VERSION 5.7 ;
  NOWIREEXTENSIONATPIN ON ;
  DIVIDERCHAR "/" ;
  BUSBITCHARS "[]" ;
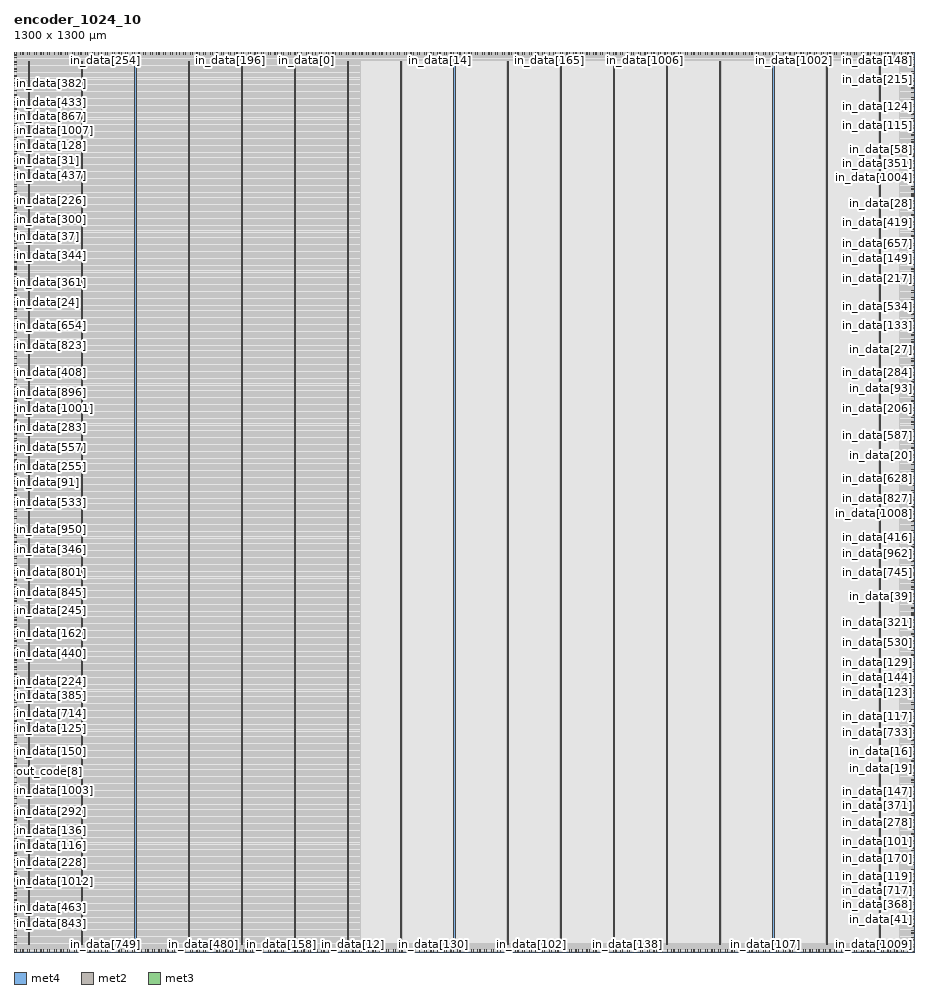
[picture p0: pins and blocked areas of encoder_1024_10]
MACRO encoder_1024_10
  CLASS BLOCK ;
  FOREIGN encoder_1024_10 ;
  ORIGIN 0.000 0.000 ;
  SIZE 1300.000 BY 1300.000 ;
  PIN VGND
    DIRECTION INOUT ;
    USE GROUND ;
    PORT
      LAYER met4 ;
        RECT 97.840 10.640 99.440 1286.800 ;
    END
    PORT
      LAYER met4 ;
        RECT 251.440 10.640 253.040 1286.800 ;
    END
    PORT
      LAYER met4 ;
        RECT 405.040 10.640 406.640 1286.800 ;
    END
    PORT
      LAYER met4 ;
        RECT 558.640 10.640 560.240 1286.800 ;
    END
    PORT
      LAYER met4 ;
        RECT 712.240 10.640 713.840 1286.800 ;
    END
    PORT
      LAYER met4 ;
        RECT 865.840 10.640 867.440 1286.800 ;
    END
    PORT
      LAYER met4 ;
        RECT 1019.440 10.640 1021.040 1286.800 ;
    END
    PORT
      LAYER met4 ;
        RECT 1173.040 10.640 1174.640 1286.800 ;
    END
  END VGND
  PIN VPWR
    DIRECTION INOUT ;
    USE POWER ;
    PORT
      LAYER met4 ;
        RECT 21.040 10.640 22.640 1286.800 ;
    END
    PORT
      LAYER met4 ;
        RECT 174.640 10.640 176.240 1286.800 ;
    END
    PORT
      LAYER met4 ;
        RECT 328.240 10.640 329.840 1286.800 ;
    END
    PORT
      LAYER met4 ;
        RECT 481.840 10.640 483.440 1286.800 ;
    END
    PORT
      LAYER met4 ;
        RECT 635.440 10.640 637.040 1286.800 ;
    END
    PORT
      LAYER met4 ;
        RECT 789.040 10.640 790.640 1286.800 ;
    END
    PORT
      LAYER met4 ;
        RECT 942.640 10.640 944.240 1286.800 ;
    END
    PORT
      LAYER met4 ;
        RECT 1096.240 10.640 1097.840 1286.800 ;
    END
    PORT
      LAYER met4 ;
        RECT 1249.840 10.640 1251.440 1286.800 ;
    END
  END VPWR
  PIN in_data[0]
    DIRECTION INPUT ;
    USE SIGNAL ;
    ANTENNAGATEAREA 0.426000 ;
    PORT
      LAYER met2 ;
        RECT 421.910 1296.000 422.190 1300.000 ;
    END
  END in_data[0]
  PIN in_data[1000]
    DIRECTION INPUT ;
    USE SIGNAL ;
    ANTENNAGATEAREA 0.742500 ;
    PORT
      LAYER met3 ;
        RECT 1296.000 10.240 1300.000 10.840 ;
    END
  END in_data[1000]
  PIN in_data[1001]
    DIRECTION INPUT ;
    USE SIGNAL ;
    ANTENNAGATEAREA 0.495000 ;
    PORT
      LAYER met3 ;
        RECT 0.000 785.440 4.000 786.040 ;
    END
  END in_data[1001]
  PIN in_data[1002]
    DIRECTION INPUT ;
    USE SIGNAL ;
    ANTENNAGATEAREA 0.742500 ;
    PORT
      LAYER met2 ;
        RECT 1127.090 1296.000 1127.370 1300.000 ;
    END
  END in_data[1002]
  PIN in_data[1003]
    DIRECTION INPUT ;
    USE SIGNAL ;
    ANTENNAGATEAREA 0.742500 ;
    PORT
      LAYER met3 ;
        RECT 0.000 244.840 4.000 245.440 ;
    END
  END in_data[1003]
  PIN in_data[1004]
    DIRECTION INPUT ;
    USE SIGNAL ;
    ANTENNAGATEAREA 0.742500 ;
    PORT
      LAYER met3 ;
        RECT 1296.000 1118.640 1300.000 1119.240 ;
    END
  END in_data[1004]
  PIN in_data[1005]
    DIRECTION INPUT ;
    USE SIGNAL ;
    ANTENNAGATEAREA 0.426000 ;
    PORT
      LAYER met3 ;
        RECT 0.000 601.840 4.000 602.440 ;
    END
  END in_data[1005]
  PIN in_data[1006]
    DIRECTION INPUT ;
    USE SIGNAL ;
    ANTENNAGATEAREA 0.495000 ;
    PORT
      LAYER met2 ;
        RECT 911.350 1296.000 911.630 1300.000 ;
    END
  END in_data[1006]
  PIN in_data[1007]
    DIRECTION INPUT ;
    USE SIGNAL ;
    ANTENNAGATEAREA 0.852000 ;
    PORT
      LAYER met3 ;
        RECT 0.000 1186.640 4.000 1187.240 ;
    END
  END in_data[1007]
  PIN in_data[1008]
    DIRECTION INPUT ;
    USE SIGNAL ;
    ANTENNAGATEAREA 0.247500 ;
    PORT
      LAYER met3 ;
        RECT 1296.000 632.440 1300.000 633.040 ;
    END
  END in_data[1008]
  PIN in_data[1009]
    DIRECTION INPUT ;
    USE SIGNAL ;
    ANTENNAGATEAREA 0.742500 ;
    PORT
      LAYER met2 ;
        RECT 1255.890 0.000 1256.170 4.000 ;
    END
  END in_data[1009]
  PIN in_data[100]
    DIRECTION INPUT ;
    USE SIGNAL ;
    ANTENNAGATEAREA 0.852000 ;
    PORT
      LAYER met2 ;
        RECT 0.090 1296.000 0.370 1300.000 ;
    END
  END in_data[100]
  PIN in_data[1010]
    DIRECTION INPUT ;
    USE SIGNAL ;
    ANTENNAGATEAREA 0.495000 ;
    PORT
      LAYER met3 ;
        RECT 1296.000 319.640 1300.000 320.240 ;
    END
  END in_data[1010]
  PIN in_data[1011]
    DIRECTION INPUT ;
    USE SIGNAL ;
    ANTENNAGATEAREA 0.742500 ;
    PORT
      LAYER met3 ;
        RECT 0.000 200.640 4.000 201.240 ;
    END
  END in_data[1011]
  PIN in_data[1012]
    DIRECTION INPUT ;
    USE SIGNAL ;
    ANTENNAGATEAREA 0.742500 ;
    PORT
      LAYER met3 ;
        RECT 0.000 102.040 4.000 102.640 ;
    END
  END in_data[1012]
  PIN in_data[1013]
    DIRECTION INPUT ;
    USE SIGNAL ;
    ANTENNAGATEAREA 0.742500 ;
    PORT
      LAYER met2 ;
        RECT 144.990 0.000 145.270 4.000 ;
    END
  END in_data[1013]
  PIN in_data[1014]
    DIRECTION INPUT ;
    USE SIGNAL ;
    ANTENNAGATEAREA 0.852000 ;
    PORT
      LAYER met2 ;
        RECT 1259.110 1296.000 1259.390 1300.000 ;
    END
  END in_data[1014]
  PIN in_data[1015]
    DIRECTION INPUT ;
    USE SIGNAL ;
    ANTENNAGATEAREA 0.247500 ;
    PORT
      LAYER met2 ;
        RECT 702.050 0.000 702.330 4.000 ;
    END
  END in_data[1015]
  PIN in_data[1016]
    DIRECTION INPUT ;
    USE SIGNAL ;
    ANTENNAGATEAREA 0.426000 ;
    PORT
      LAYER met3 ;
        RECT 1296.000 663.040 1300.000 663.640 ;
    END
  END in_data[1016]
  PIN in_data[1017]
    DIRECTION INPUT ;
    USE SIGNAL ;
    ANTENNAGATEAREA 0.742500 ;
    PORT
      LAYER met3 ;
        RECT 0.000 1037.040 4.000 1037.640 ;
    END
  END in_data[1017]
  PIN in_data[1018]
    DIRECTION INPUT ;
    USE SIGNAL ;
    ANTENNAGATEAREA 0.852000 ;
    PORT
      LAYER met2 ;
        RECT 32.290 1296.000 32.570 1300.000 ;
    END
  END in_data[1018]
  PIN in_data[1019]
    DIRECTION INPUT ;
    USE SIGNAL ;
    ANTENNAGATEAREA 0.495000 ;
    PORT
      LAYER met3 ;
        RECT 1296.000 873.840 1300.000 874.440 ;
    END
  END in_data[1019]
  PIN in_data[101]
    DIRECTION INPUT ;
    USE SIGNAL ;
    ANTENNAGATEAREA 0.742500 ;
    PORT
      LAYER met3 ;
        RECT 1296.000 159.840 1300.000 160.440 ;
    END
  END in_data[101]
  PIN in_data[1020]
    DIRECTION INPUT ;
    USE SIGNAL ;
    ANTENNAGATEAREA 0.742500 ;
    PORT
      LAYER met3 ;
        RECT 1296.000 51.040 1300.000 51.640 ;
    END
  END in_data[1020]
  PIN in_data[1021]
    DIRECTION INPUT ;
    USE SIGNAL ;
    ANTENNAGATEAREA 0.495000 ;
    PORT
      LAYER met3 ;
        RECT 0.000 748.040 4.000 748.640 ;
    END
  END in_data[1021]
  PIN in_data[1022]
    DIRECTION INPUT ;
    USE SIGNAL ;
    ANTENNAGATEAREA 0.742500 ;
    PORT
      LAYER met3 ;
        RECT 0.000 183.640 4.000 184.240 ;
    END
  END in_data[1022]
  PIN in_data[1023]
    DIRECTION INPUT ;
    USE SIGNAL ;
    ANTENNAGATEAREA 0.742500 ;
    PORT
      LAYER met3 ;
        RECT 1296.000 275.440 1300.000 276.040 ;
    END
  END in_data[1023]
  PIN in_data[102]
    DIRECTION INPUT ;
    USE SIGNAL ;
    ANTENNAGATEAREA 0.426000 ;
    PORT
      LAYER met2 ;
        RECT 747.130 0.000 747.410 4.000 ;
    END
  END in_data[102]
  PIN in_data[103]
    DIRECTION INPUT ;
    USE SIGNAL ;
    ANTENNAGATEAREA 0.742500 ;
    PORT
      LAYER met2 ;
        RECT 164.310 1296.000 164.590 1300.000 ;
    END
  END in_data[103]
  PIN in_data[104]
    DIRECTION INPUT ;
    USE SIGNAL ;
    ANTENNAGATEAREA 0.495000 ;
    PORT
      LAYER met2 ;
        RECT 1156.070 1296.000 1156.350 1300.000 ;
    END
  END in_data[104]
  PIN in_data[105]
    DIRECTION INPUT ;
    USE SIGNAL ;
    ANTENNAGATEAREA 0.426000 ;
    PORT
      LAYER met3 ;
        RECT 1296.000 880.640 1300.000 881.240 ;
    END
  END in_data[105]
  PIN in_data[106]
    DIRECTION INPUT ;
    USE SIGNAL ;
    ANTENNAGATEAREA 0.426000 ;
    PORT
      LAYER met3 ;
        RECT 1296.000 935.040 1300.000 935.640 ;
    END
  END in_data[106]
  PIN in_data[107]
    DIRECTION INPUT ;
    USE SIGNAL ;
    ANTENNAGATEAREA 0.742500 ;
    PORT
      LAYER met2 ;
        RECT 1085.230 0.000 1085.510 4.000 ;
    END
  END in_data[107]
  PIN in_data[108]
    DIRECTION INPUT ;
    USE SIGNAL ;
    ANTENNAGATEAREA 0.495000 ;
    PORT
      LAYER met3 ;
        RECT 0.000 625.640 4.000 626.240 ;
    END
  END in_data[108]
  PIN in_data[109]
    DIRECTION INPUT ;
    USE SIGNAL ;
    ANTENNAGATEAREA 0.742500 ;
    PORT
      LAYER met2 ;
        RECT 1143.190 0.000 1143.470 4.000 ;
    END
  END in_data[109]
  PIN in_data[10]
    DIRECTION INPUT ;
    USE SIGNAL ;
    ANTENNAGATEAREA 0.742500 ;
    PORT
      LAYER met2 ;
        RECT 1082.010 1296.000 1082.290 1300.000 ;
    END
  END in_data[10]
  PIN in_data[110]
    DIRECTION INPUT ;
    USE SIGNAL ;
    ANTENNAGATEAREA 0.742500 ;
    PORT
      LAYER met2 ;
        RECT 209.390 1296.000 209.670 1300.000 ;
    END
  END in_data[110]
  PIN in_data[111]
    DIRECTION INPUT ;
    USE SIGNAL ;
    ANTENNAGATEAREA 0.742500 ;
    PORT
      LAYER met2 ;
        RECT 231.930 0.000 232.210 4.000 ;
    END
  END in_data[111]
  PIN in_data[112]
    DIRECTION INPUT ;
    USE SIGNAL ;
    ANTENNAGATEAREA 0.742500 ;
    PORT
      LAYER met2 ;
        RECT 219.050 1296.000 219.330 1300.000 ;
    END
  END in_data[112]
  PIN in_data[113]
    DIRECTION INPUT ;
    USE SIGNAL ;
    ANTENNAGATEAREA 0.426000 ;
    PORT
      LAYER met2 ;
        RECT 895.250 1296.000 895.530 1300.000 ;
    END
  END in_data[113]
  PIN in_data[114]
    DIRECTION INPUT ;
    USE SIGNAL ;
    ANTENNAGATEAREA 0.742500 ;
    PORT
      LAYER met2 ;
        RECT 1291.310 0.000 1291.590 4.000 ;
    END
  END in_data[114]
  PIN in_data[115]
    DIRECTION INPUT ;
    USE SIGNAL ;
    ANTENNAGATEAREA 0.742500 ;
    PORT
      LAYER met3 ;
        RECT 1296.000 1193.440 1300.000 1194.040 ;
    END
  END in_data[115]
  PIN in_data[116]
    DIRECTION INPUT ;
    USE SIGNAL ;
    ANTENNAGATEAREA 0.852000 ;
    PORT
      LAYER met3 ;
        RECT 0.000 153.040 4.000 153.640 ;
    END
  END in_data[116]
  PIN in_data[117]
    DIRECTION INPUT ;
    USE SIGNAL ;
    ANTENNAGATEAREA 0.742500 ;
    PORT
      LAYER met3 ;
        RECT 1296.000 340.040 1300.000 340.640 ;
    END
  END in_data[117]
  PIN in_data[118]
    DIRECTION INPUT ;
    USE SIGNAL ;
    ANTENNAGATEAREA 0.247500 ;
    PORT
      LAYER met3 ;
        RECT 1296.000 724.240 1300.000 724.840 ;
    END
  END in_data[118]
  PIN in_data[119]
    DIRECTION INPUT ;
    USE SIGNAL ;
    ANTENNAGATEAREA 0.742500 ;
    PORT
      LAYER met3 ;
        RECT 1296.000 108.840 1300.000 109.440 ;
    END
  END in_data[119]
  PIN in_data[11]
    DIRECTION INPUT ;
    USE SIGNAL ;
    ANTENNAGATEAREA 0.495000 ;
    PORT
      LAYER met2 ;
        RECT 924.230 1296.000 924.510 1300.000 ;
    END
  END in_data[11]
  PIN in_data[120]
    DIRECTION INPUT ;
    USE SIGNAL ;
    ANTENNAGATEAREA 0.742500 ;
    PORT
      LAYER met2 ;
        RECT 1130.310 0.000 1130.590 4.000 ;
    END
  END in_data[120]
  PIN in_data[121]
    DIRECTION INPUT ;
    USE SIGNAL ;
    ANTENNAGATEAREA 0.852000 ;
    PORT
      LAYER met2 ;
        RECT 41.950 0.000 42.230 4.000 ;
    END
  END in_data[121]
  PIN in_data[122]
    DIRECTION INPUT ;
    USE SIGNAL ;
    ANTENNAGATEAREA 0.495000 ;
    PORT
      LAYER met3 ;
        RECT 1296.000 394.440 1300.000 395.040 ;
    END
  END in_data[122]
  PIN in_data[123]
    DIRECTION INPUT ;
    USE SIGNAL ;
    ANTENNAGATEAREA 0.495000 ;
    PORT
      LAYER met3 ;
        RECT 1296.000 374.040 1300.000 374.640 ;
    END
  END in_data[123]
  PIN in_data[124]
    DIRECTION INPUT ;
    USE SIGNAL ;
    ANTENNAGATEAREA 0.742500 ;
    PORT
      LAYER met3 ;
        RECT 1296.000 1220.640 1300.000 1221.240 ;
    END
  END in_data[124]
  PIN in_data[125]
    DIRECTION INPUT ;
    USE SIGNAL ;
    ANTENNAGATEAREA 0.742500 ;
    PORT
      LAYER met3 ;
        RECT 0.000 323.040 4.000 323.640 ;
    END
  END in_data[125]
  PIN in_data[126]
    DIRECTION INPUT ;
    USE SIGNAL ;
    ANTENNAGATEAREA 0.852000 ;
    PORT
      LAYER met2 ;
        RECT 1297.750 0.000 1298.030 4.000 ;
    END
  END in_data[126]
  PIN in_data[127]
    DIRECTION INPUT ;
    USE SIGNAL ;
    ANTENNAGATEAREA 0.495000 ;
    PORT
      LAYER met3 ;
        RECT 1296.000 1071.040 1300.000 1071.640 ;
    END
  END in_data[127]
  PIN in_data[128]
    DIRECTION INPUT ;
    USE SIGNAL ;
    ANTENNAGATEAREA 0.742500 ;
    PORT
      LAYER met3 ;
        RECT 0.000 1176.440 4.000 1177.040 ;
    END
  END in_data[128]
  PIN in_data[129]
    DIRECTION INPUT ;
    USE SIGNAL ;
    ANTENNAGATEAREA 0.495000 ;
    PORT
      LAYER met3 ;
        RECT 1296.000 418.240 1300.000 418.840 ;
    END
  END in_data[129]
  PIN in_data[12]
    DIRECTION INPUT ;
    USE SIGNAL ;
    ANTENNAGATEAREA 0.495000 ;
    PORT
      LAYER met2 ;
        RECT 489.530 0.000 489.810 4.000 ;
    END
  END in_data[12]
  PIN in_data[130]
    DIRECTION INPUT ;
    USE SIGNAL ;
    ANTENNAGATEAREA 0.426000 ;
    PORT
      LAYER met2 ;
        RECT 605.450 0.000 605.730 4.000 ;
    END
  END in_data[130]
  PIN in_data[131]
    DIRECTION INPUT ;
    USE SIGNAL ;
    ANTENNAGATEAREA 0.742500 ;
    PORT
      LAYER met2 ;
        RECT 1178.610 0.000 1178.890 4.000 ;
    END
  END in_data[131]
  PIN in_data[132]
    DIRECTION INPUT ;
    USE SIGNAL ;
    ANTENNAGATEAREA 0.247500 ;
    PORT
      LAYER met3 ;
        RECT 1296.000 761.640 1300.000 762.240 ;
    END
  END in_data[132]
  PIN in_data[133]
    DIRECTION INPUT ;
    USE SIGNAL ;
    ANTENNAGATEAREA 0.426000 ;
    PORT
      LAYER met3 ;
        RECT 1296.000 904.440 1300.000 905.040 ;
    END
  END in_data[133]
  PIN in_data[134]
    DIRECTION INPUT ;
    USE SIGNAL ;
    ANTENNAGATEAREA 0.742500 ;
    PORT
      LAYER met2 ;
        RECT 1075.570 0.000 1075.850 4.000 ;
    END
  END in_data[134]
  PIN in_data[135]
    DIRECTION INPUT ;
    USE SIGNAL ;
    ANTENNAGATEAREA 0.426000 ;
    PORT
      LAYER met2 ;
        RECT 1043.370 1296.000 1043.650 1300.000 ;
    END
  END in_data[135]
  PIN in_data[136]
    DIRECTION INPUT ;
    USE SIGNAL ;
    ANTENNAGATEAREA 0.852000 ;
    PORT
      LAYER met3 ;
        RECT 0.000 163.240 4.000 163.840 ;
    END
  END in_data[136]
  PIN in_data[137]
    DIRECTION INPUT ;
    USE SIGNAL ;
    ANTENNAGATEAREA 0.742500 ;
    PORT
      LAYER met3 ;
        RECT 1296.000 1288.640 1300.000 1289.240 ;
    END
  END in_data[137]
  PIN in_data[138]
    DIRECTION INPUT ;
    USE SIGNAL ;
    ANTENNAGATEAREA 0.495000 ;
    PORT
      LAYER met2 ;
        RECT 885.590 0.000 885.870 4.000 ;
    END
  END in_data[138]
  PIN in_data[139]
    DIRECTION INPUT ;
    USE SIGNAL ;
    ANTENNAGATEAREA 0.495000 ;
    PORT
      LAYER met2 ;
        RECT 360.730 1296.000 361.010 1300.000 ;
    END
  END in_data[139]
  PIN in_data[13]
    DIRECTION INPUT ;
    USE SIGNAL ;
    ANTENNAGATEAREA 0.742500 ;
    PORT
      LAYER met2 ;
        RECT 209.390 0.000 209.670 4.000 ;
    END
  END in_data[13]
  PIN in_data[140]
    DIRECTION INPUT ;
    USE SIGNAL ;
    ANTENNAGATEAREA 0.742500 ;
    PORT
      LAYER met3 ;
        RECT 0.000 448.840 4.000 449.440 ;
    END
  END in_data[140]
  PIN in_data[141]
    DIRECTION INPUT ;
    USE SIGNAL ;
    ANTENNAGATEAREA 0.742500 ;
    PORT
      LAYER met3 ;
        RECT 0.000 1213.840 4.000 1214.440 ;
    END
  END in_data[141]
  PIN in_data[142]
    DIRECTION INPUT ;
    USE SIGNAL ;
    ANTENNAGATEAREA 0.742500 ;
    PORT
      LAYER met2 ;
        RECT 41.950 1296.000 42.230 1300.000 ;
    END
  END in_data[142]
  PIN in_data[143]
    DIRECTION INPUT ;
    USE SIGNAL ;
    ANTENNAGATEAREA 0.742500 ;
    PORT
      LAYER met3 ;
        RECT 1296.000 329.840 1300.000 330.440 ;
    END
  END in_data[143]
  PIN in_data[144]
    DIRECTION INPUT ;
    USE SIGNAL ;
    ANTENNAGATEAREA 0.742500 ;
    PORT
      LAYER met3 ;
        RECT 1296.000 408.040 1300.000 408.640 ;
    END
  END in_data[144]
  PIN in_data[145]
    DIRECTION INPUT ;
    USE SIGNAL ;
    ANTENNAGATEAREA 0.742500 ;
    PORT
      LAYER met2 ;
        RECT 228.710 0.000 228.990 4.000 ;
    END
  END in_data[145]
  PIN in_data[146]
    DIRECTION INPUT ;
    USE SIGNAL ;
    ANTENNAGATEAREA 0.426000 ;
    PORT
      LAYER met2 ;
        RECT 463.770 1296.000 464.050 1300.000 ;
    END
  END in_data[146]
  PIN in_data[147]
    DIRECTION INPUT ;
    USE SIGNAL ;
    ANTENNAGATEAREA 0.742500 ;
    PORT
      LAYER met3 ;
        RECT 1296.000 231.240 1300.000 231.840 ;
    END
  END in_data[147]
  PIN in_data[148]
    DIRECTION INPUT ;
    USE SIGNAL ;
    ANTENNAGATEAREA 0.742500 ;
    PORT
      LAYER met2 ;
        RECT 1268.770 1296.000 1269.050 1300.000 ;
    END
  END in_data[148]
  PIN in_data[149]
    DIRECTION INPUT ;
    USE SIGNAL ;
    ANTENNAGATEAREA 0.495000 ;
    PORT
      LAYER met3 ;
        RECT 1296.000 1013.240 1300.000 1013.840 ;
    END
  END in_data[149]
  PIN in_data[14]
    DIRECTION INPUT ;
    USE SIGNAL ;
    ANTENNAGATEAREA 0.247500 ;
    PORT
      LAYER met2 ;
        RECT 615.110 1296.000 615.390 1300.000 ;
    END
  END in_data[14]
  PIN in_data[150]
    DIRECTION INPUT ;
    USE SIGNAL ;
    ANTENNAGATEAREA 0.742500 ;
    PORT
      LAYER met3 ;
        RECT 0.000 289.040 4.000 289.640 ;
    END
  END in_data[150]
  PIN in_data[151]
    DIRECTION INPUT ;
    USE SIGNAL ;
    ANTENNAGATEAREA 0.742500 ;
    PORT
      LAYER met2 ;
        RECT 1194.710 0.000 1194.990 4.000 ;
    END
  END in_data[151]
  PIN in_data[152]
    DIRECTION INPUT ;
    USE SIGNAL ;
    ANTENNAGATEAREA 0.495000 ;
    PORT
      LAYER met2 ;
        RECT 576.470 0.000 576.750 4.000 ;
    END
  END in_data[152]
  PIN in_data[153]
    DIRECTION INPUT ;
    USE SIGNAL ;
    ANTENNAGATEAREA 0.742500 ;
    PORT
      LAYER met2 ;
        RECT 1085.230 1296.000 1085.510 1300.000 ;
    END
  END in_data[153]
  PIN in_data[154]
    DIRECTION INPUT ;
    USE SIGNAL ;
    ANTENNAGATEAREA 0.426000 ;
    PORT
      LAYER met2 ;
        RECT 689.170 0.000 689.450 4.000 ;
    END
  END in_data[154]
  PIN in_data[155]
    DIRECTION INPUT ;
    USE SIGNAL ;
    ANTENNAGATEAREA 0.426000 ;
    PORT
      LAYER met3 ;
        RECT 1296.000 703.840 1300.000 704.440 ;
    END
  END in_data[155]
  PIN in_data[156]
    DIRECTION INPUT ;
    USE SIGNAL ;
    ANTENNAGATEAREA 0.742500 ;
    PORT
      LAYER met3 ;
        RECT 0.000 302.640 4.000 303.240 ;
    END
  END in_data[156]
  PIN in_data[157]
    DIRECTION INPUT ;
    USE SIGNAL ;
    ANTENNAGATEAREA 0.742500 ;
    PORT
      LAYER met2 ;
        RECT 64.490 1296.000 64.770 1300.000 ;
    END
  END in_data[157]
  PIN in_data[158]
    DIRECTION INPUT ;
    USE SIGNAL ;
    ANTENNAGATEAREA 0.742500 ;
    PORT
      LAYER met2 ;
        RECT 386.490 0.000 386.770 4.000 ;
    END
  END in_data[158]
  PIN in_data[159]
    DIRECTION INPUT ;
    USE SIGNAL ;
    ANTENNAGATEAREA 0.426000 ;
    PORT
      LAYER met3 ;
        RECT 1296.000 578.040 1300.000 578.640 ;
    END
  END in_data[159]
  PIN in_data[15]
    DIRECTION INPUT ;
    USE SIGNAL ;
    ANTENNAGATEAREA 0.426000 ;
    PORT
      LAYER met2 ;
        RECT 808.310 1296.000 808.590 1300.000 ;
    END
  END in_data[15]
  PIN in_data[160]
    DIRECTION INPUT ;
    USE SIGNAL ;
    ANTENNAGATEAREA 0.742500 ;
    PORT
      LAYER met2 ;
        RECT 248.030 0.000 248.310 4.000 ;
    END
  END in_data[160]
  PIN in_data[161]
    DIRECTION INPUT ;
    USE SIGNAL ;
    ANTENNAGATEAREA 0.495000 ;
    PORT
      LAYER met2 ;
        RECT 1024.050 1296.000 1024.330 1300.000 ;
    END
  END in_data[161]
  PIN in_data[162]
    DIRECTION INPUT ;
    USE SIGNAL ;
    ANTENNAGATEAREA 0.742500 ;
    PORT
      LAYER met3 ;
        RECT 0.000 459.040 4.000 459.640 ;
    END
  END in_data[162]
  PIN in_data[163]
    DIRECTION INPUT ;
    USE SIGNAL ;
    ANTENNAGATEAREA 0.742500 ;
    PORT
      LAYER met3 ;
        RECT 1296.000 248.240 1300.000 248.840 ;
    END
  END in_data[163]
  PIN in_data[164]
    DIRECTION INPUT ;
    USE SIGNAL ;
    ANTENNAGATEAREA 0.742500 ;
    PORT
      LAYER met2 ;
        RECT 376.830 0.000 377.110 4.000 ;
    END
  END in_data[164]
  PIN in_data[165]
    DIRECTION INPUT ;
    USE SIGNAL ;
    ANTENNAGATEAREA 0.247500 ;
    PORT
      LAYER met2 ;
        RECT 772.890 1296.000 773.170 1300.000 ;
    END
  END in_data[165]
  PIN in_data[166]
    DIRECTION INPUT ;
    USE SIGNAL ;
    ANTENNAGATEAREA 0.247500 ;
    PORT
      LAYER met2 ;
        RECT 811.530 1296.000 811.810 1300.000 ;
    END
  END in_data[166]
  PIN in_data[167]
    DIRECTION INPUT ;
    USE SIGNAL ;
    ANTENNAGATEAREA 0.742500 ;
    PORT
      LAYER met2 ;
        RECT 1091.670 0.000 1091.950 4.000 ;
    END
  END in_data[167]
  PIN in_data[168]
    DIRECTION INPUT ;
    USE SIGNAL ;
    ANTENNAGATEAREA 0.495000 ;
    PORT
      LAYER met3 ;
        RECT 1296.000 414.840 1300.000 415.440 ;
    END
  END in_data[168]
  PIN in_data[169]
    DIRECTION INPUT ;
    USE SIGNAL ;
    ANTENNAGATEAREA 0.742500 ;
    PORT
      LAYER met2 ;
        RECT 215.830 1296.000 216.110 1300.000 ;
    END
  END in_data[169]
  PIN in_data[16]
    DIRECTION INPUT ;
    USE SIGNAL ;
    ANTENNAGATEAREA 0.742500 ;
    PORT
      LAYER met3 ;
        RECT 1296.000 289.040 1300.000 289.640 ;
    END
  END in_data[16]
  PIN in_data[170]
    DIRECTION INPUT ;
    USE SIGNAL ;
    ANTENNAGATEAREA 0.742500 ;
    PORT
      LAYER met3 ;
        RECT 1296.000 146.240 1300.000 146.840 ;
    END
  END in_data[170]
  PIN in_data[171]
    DIRECTION INPUT ;
    USE SIGNAL ;
    ANTENNAGATEAREA 0.742500 ;
    PORT
      LAYER met2 ;
        RECT 1094.890 0.000 1095.170 4.000 ;
    END
  END in_data[171]
  PIN in_data[172]
    DIRECTION INPUT ;
    USE SIGNAL ;
    ANTENNAGATEAREA 0.426000 ;
    PORT
      LAYER met2 ;
        RECT 409.030 1296.000 409.310 1300.000 ;
    END
  END in_data[172]
  PIN in_data[173]
    DIRECTION INPUT ;
    USE SIGNAL ;
    ANTENNAGATEAREA 0.426000 ;
    PORT
      LAYER met3 ;
        RECT 0.000 686.840 4.000 687.440 ;
    END
  END in_data[173]
  PIN in_data[174]
    DIRECTION INPUT ;
    USE SIGNAL ;
    ANTENNAGATEAREA 0.742500 ;
    PORT
      LAYER met2 ;
        RECT 1204.370 1296.000 1204.650 1300.000 ;
    END
  END in_data[174]
  PIN in_data[175]
    DIRECTION INPUT ;
    USE SIGNAL ;
    ANTENNAGATEAREA 0.495000 ;
    PORT
      LAYER met3 ;
        RECT 1296.000 489.640 1300.000 490.240 ;
    END
  END in_data[175]
  PIN in_data[176]
    DIRECTION INPUT ;
    USE SIGNAL ;
    ANTENNAGATEAREA 0.742500 ;
    PORT
      LAYER met2 ;
        RECT 1297.750 1296.000 1298.030 1300.000 ;
    END
  END in_data[176]
  PIN in_data[177]
    DIRECTION INPUT ;
    USE SIGNAL ;
    ANTENNAGATEAREA 0.742500 ;
    PORT
      LAYER met3 ;
        RECT 0.000 1224.040 4.000 1224.640 ;
    END
  END in_data[177]
  PIN in_data[178]
    DIRECTION INPUT ;
    USE SIGNAL ;
    ANTENNAGATEAREA 0.742500 ;
    PORT
      LAYER met2 ;
        RECT 399.370 0.000 399.650 4.000 ;
    END
  END in_data[178]
  PIN in_data[179]
    DIRECTION INPUT ;
    USE SIGNAL ;
    ANTENNAGATEAREA 0.426000 ;
    PORT
      LAYER met3 ;
        RECT 0.000 856.840 4.000 857.440 ;
    END
  END in_data[179]
  PIN in_data[17]
    DIRECTION INPUT ;
    USE SIGNAL ;
    ANTENNAGATEAREA 0.742500 ;
    PORT
      LAYER met2 ;
        RECT 357.510 0.000 357.790 4.000 ;
    END
  END in_data[17]
  PIN in_data[180]
    DIRECTION INPUT ;
    USE SIGNAL ;
    ANTENNAGATEAREA 0.247500 ;
    PORT
      LAYER met2 ;
        RECT 573.250 1296.000 573.530 1300.000 ;
    END
  END in_data[180]
  PIN in_data[181]
    DIRECTION INPUT ;
    USE SIGNAL ;
    ANTENNAGATEAREA 0.742500 ;
    PORT
      LAYER met2 ;
        RECT 87.030 1296.000 87.310 1300.000 ;
    END
  END in_data[181]
  PIN in_data[182]
    DIRECTION INPUT ;
    USE SIGNAL ;
    ANTENNAGATEAREA 0.852000 ;
    PORT
      LAYER met2 ;
        RECT 1214.030 0.000 1214.310 4.000 ;
    END
  END in_data[182]
  PIN in_data[183]
    DIRECTION INPUT ;
    USE SIGNAL ;
    ANTENNAGATEAREA 0.426000 ;
    PORT
      LAYER met3 ;
        RECT 1296.000 642.640 1300.000 643.240 ;
    END
  END in_data[183]
  PIN in_data[184]
    DIRECTION INPUT ;
    USE SIGNAL ;
    ANTENNAGATEAREA 0.742500 ;
    PORT
      LAYER met2 ;
        RECT 425.130 0.000 425.410 4.000 ;
    END
  END in_data[184]
  PIN in_data[185]
    DIRECTION INPUT ;
    USE SIGNAL ;
    ANTENNAGATEAREA 0.426000 ;
    PORT
      LAYER met3 ;
        RECT 1296.000 975.840 1300.000 976.440 ;
    END
  END in_data[185]
  PIN in_data[186]
    DIRECTION INPUT ;
    USE SIGNAL ;
    ANTENNAGATEAREA 0.742500 ;
    PORT
      LAYER met3 ;
        RECT 0.000 1281.840 4.000 1282.440 ;
    END
  END in_data[186]
  PIN in_data[187]
    DIRECTION INPUT ;
    USE SIGNAL ;
    ANTENNAGATEAREA 0.495000 ;
    PORT
      LAYER met3 ;
        RECT 0.000 924.840 4.000 925.440 ;
    END
  END in_data[187]
  PIN in_data[188]
    DIRECTION INPUT ;
    USE SIGNAL ;
    ANTENNAGATEAREA 0.495000 ;
    PORT
      LAYER met2 ;
        RECT 679.510 0.000 679.790 4.000 ;
    END
  END in_data[188]
  PIN in_data[189]
    DIRECTION INPUT ;
    USE SIGNAL ;
    ANTENNAGATEAREA 0.852000 ;
    PORT
      LAYER met2 ;
        RECT 3.310 0.000 3.590 4.000 ;
    END
  END in_data[189]
  PIN in_data[18]
    DIRECTION INPUT ;
    USE SIGNAL ;
    ANTENNAGATEAREA 0.742500 ;
    PORT
      LAYER met2 ;
        RECT 151.430 0.000 151.710 4.000 ;
    END
  END in_data[18]
  PIN in_data[190]
    DIRECTION INPUT ;
    USE SIGNAL ;
    ANTENNAGATEAREA 0.742500 ;
    PORT
      LAYER met2 ;
        RECT 296.330 0.000 296.610 4.000 ;
    END
  END in_data[190]
  PIN in_data[191]
    DIRECTION INPUT ;
    USE SIGNAL ;
    ANTENNAGATEAREA 0.742500 ;
    PORT
      LAYER met2 ;
        RECT 264.130 0.000 264.410 4.000 ;
    END
  END in_data[191]
  PIN in_data[192]
    DIRECTION INPUT ;
    USE SIGNAL ;
    ANTENNAGATEAREA 0.742500 ;
    PORT
      LAYER met3 ;
        RECT 0.000 421.640 4.000 422.240 ;
    END
  END in_data[192]
  PIN in_data[193]
    DIRECTION INPUT ;
    USE SIGNAL ;
    ANTENNAGATEAREA 0.495000 ;
    PORT
      LAYER met2 ;
        RECT 1033.710 1296.000 1033.990 1300.000 ;
    END
  END in_data[193]
  PIN in_data[194]
    DIRECTION INPUT ;
    USE SIGNAL ;
    ANTENNAGATEAREA 0.247500 ;
    PORT
      LAYER met2 ;
        RECT 850.170 1296.000 850.450 1300.000 ;
    END
  END in_data[194]
  PIN in_data[195]
    DIRECTION INPUT ;
    USE SIGNAL ;
    ANTENNAGATEAREA 0.247500 ;
    PORT
      LAYER met2 ;
        RECT 734.250 1296.000 734.530 1300.000 ;
    END
  END in_data[195]
  PIN in_data[196]
    DIRECTION INPUT ;
    USE SIGNAL ;
    ANTENNAGATEAREA 0.495000 ;
    PORT
      LAYER met2 ;
        RECT 312.430 1296.000 312.710 1300.000 ;
    END
  END in_data[196]
  PIN in_data[197]
    DIRECTION INPUT ;
    USE SIGNAL ;
    ANTENNAGATEAREA 0.742500 ;
    PORT
      LAYER met3 ;
        RECT 1296.000 278.840 1300.000 279.440 ;
    END
  END in_data[197]
  PIN in_data[198]
    DIRECTION INPUT ;
    USE SIGNAL ;
    ANTENNAGATEAREA 0.742500 ;
    PORT
      LAYER met3 ;
        RECT 0.000 1156.040 4.000 1156.640 ;
    END
  END in_data[198]
  PIN in_data[199]
    DIRECTION INPUT ;
    USE SIGNAL ;
    ANTENNAGATEAREA 0.426000 ;
    PORT
      LAYER met2 ;
        RECT 370.390 1296.000 370.670 1300.000 ;
    END
  END in_data[199]
  PIN in_data[19]
    DIRECTION INPUT ;
    USE SIGNAL ;
    ANTENNAGATEAREA 0.742500 ;
    PORT
      LAYER met3 ;
        RECT 1296.000 265.240 1300.000 265.840 ;
    END
  END in_data[19]
  PIN in_data[1]
    DIRECTION INPUT ;
    USE SIGNAL ;
    ANTENNAGATEAREA 0.247500 ;
    PORT
      LAYER met2 ;
        RECT 479.870 1296.000 480.150 1300.000 ;
    END
  END in_data[1]
  PIN in_data[200]
    DIRECTION INPUT ;
    USE SIGNAL ;
    ANTENNAGATEAREA 0.247500 ;
    PORT
      LAYER met2 ;
        RECT 611.890 1296.000 612.170 1300.000 ;
    END
  END in_data[200]
  PIN in_data[201]
    DIRECTION INPUT ;
    USE SIGNAL ;
    ANTENNAGATEAREA 0.495000 ;
    PORT
      LAYER met2 ;
        RECT 473.430 0.000 473.710 4.000 ;
    END
  END in_data[201]
  PIN in_data[202]
    DIRECTION INPUT ;
    USE SIGNAL ;
    ANTENNAGATEAREA 0.742500 ;
    PORT
      LAYER met2 ;
        RECT 254.470 0.000 254.750 4.000 ;
    END
  END in_data[202]
  PIN in_data[203]
    DIRECTION INPUT ;
    USE SIGNAL ;
    ANTENNAGATEAREA 0.742500 ;
    PORT
      LAYER met2 ;
        RECT 125.670 1296.000 125.950 1300.000 ;
    END
  END in_data[203]
  PIN in_data[204]
    DIRECTION INPUT ;
    USE SIGNAL ;
    ANTENNAGATEAREA 0.426000 ;
    PORT
      LAYER met2 ;
        RECT 859.830 1296.000 860.110 1300.000 ;
    END
  END in_data[204]
  PIN in_data[205]
    DIRECTION INPUT ;
    USE SIGNAL ;
    ANTENNAGATEAREA 0.852000 ;
    PORT
      LAYER met2 ;
        RECT 1204.370 0.000 1204.650 4.000 ;
    END
  END in_data[205]
  PIN in_data[206]
    DIRECTION INPUT ;
    USE SIGNAL ;
    ANTENNAGATEAREA 0.426000 ;
    PORT
      LAYER met3 ;
        RECT 1296.000 785.440 1300.000 786.040 ;
    END
  END in_data[206]
  PIN in_data[207]
    DIRECTION INPUT ;
    USE SIGNAL ;
    ANTENNAGATEAREA 0.495000 ;
    PORT
      LAYER met2 ;
        RECT 827.630 0.000 827.910 4.000 ;
    END
  END in_data[207]
  PIN in_data[208]
    DIRECTION INPUT ;
    USE SIGNAL ;
    ANTENNAGATEAREA 0.742500 ;
    PORT
      LAYER met3 ;
        RECT 1296.000 1128.840 1300.000 1129.440 ;
    END
  END in_data[208]
  PIN in_data[209]
    DIRECTION INPUT ;
    USE SIGNAL ;
    ANTENNAGATEAREA 0.742500 ;
    PORT
      LAYER met3 ;
        RECT 0.000 1193.440 4.000 1194.040 ;
    END
  END in_data[209]
  PIN in_data[20]
    DIRECTION INPUT ;
    USE SIGNAL ;
    ANTENNAGATEAREA 0.247500 ;
    PORT
      LAYER met3 ;
        RECT 1296.000 717.440 1300.000 718.040 ;
    END
  END in_data[20]
  PIN in_data[210]
    DIRECTION INPUT ;
    USE SIGNAL ;
    ANTENNAGATEAREA 0.426000 ;
    PORT
      LAYER met2 ;
        RECT 1007.950 1296.000 1008.230 1300.000 ;
    END
  END in_data[210]
  PIN in_data[211]
    DIRECTION INPUT ;
    USE SIGNAL ;
    ANTENNAGATEAREA 0.426000 ;
    PORT
      LAYER met2 ;
        RECT 943.550 1296.000 943.830 1300.000 ;
    END
  END in_data[211]
  PIN in_data[212]
    DIRECTION INPUT ;
    USE SIGNAL ;
    ANTENNAGATEAREA 0.742500 ;
    PORT
      LAYER met3 ;
        RECT 0.000 1292.040 4.000 1292.640 ;
    END
  END in_data[212]
  PIN in_data[213]
    DIRECTION INPUT ;
    USE SIGNAL ;
    ANTENNAGATEAREA 0.742500 ;
    PORT
      LAYER met2 ;
        RECT 1149.630 0.000 1149.910 4.000 ;
    END
  END in_data[213]
  PIN in_data[214]
    DIRECTION INPUT ;
    USE SIGNAL ;
    ANTENNAGATEAREA 0.426000 ;
    PORT
      LAYER met3 ;
        RECT 1296.000 707.240 1300.000 707.840 ;
    END
  END in_data[214]
  PIN in_data[215]
    DIRECTION INPUT ;
    USE SIGNAL ;
    ANTENNAGATEAREA 0.742500 ;
    PORT
      LAYER met3 ;
        RECT 1296.000 1271.640 1300.000 1272.240 ;
    END
  END in_data[215]
  PIN in_data[216]
    DIRECTION INPUT ;
    USE SIGNAL ;
    ANTENNAGATEAREA 0.852000 ;
    PORT
      LAYER met2 ;
        RECT 170.750 0.000 171.030 4.000 ;
    END
  END in_data[216]
  PIN in_data[217]
    DIRECTION INPUT ;
    USE SIGNAL ;
    ANTENNAGATEAREA 0.495000 ;
    PORT
      LAYER met3 ;
        RECT 1296.000 972.440 1300.000 973.040 ;
    END
  END in_data[217]
  PIN in_data[218]
    DIRECTION INPUT ;
    USE SIGNAL ;
    ANTENNAGATEAREA 0.742500 ;
    PORT
      LAYER met3 ;
        RECT 1296.000 1281.840 1300.000 1282.440 ;
    END
  END in_data[218]
  PIN in_data[219]
    DIRECTION INPUT ;
    USE SIGNAL ;
    ANTENNAGATEAREA 0.426000 ;
    PORT
      LAYER met3 ;
        RECT 0.000 754.840 4.000 755.440 ;
    END
  END in_data[219]
  PIN in_data[21]
    DIRECTION INPUT ;
    USE SIGNAL ;
    ANTENNAGATEAREA 0.495000 ;
    PORT
      LAYER met3 ;
        RECT 1296.000 397.840 1300.000 398.440 ;
    END
  END in_data[21]
  PIN in_data[220]
    DIRECTION INPUT ;
    USE SIGNAL ;
    ANTENNAGATEAREA 0.426000 ;
    PORT
      LAYER met3 ;
        RECT 1296.000 775.240 1300.000 775.840 ;
    END
  END in_data[220]
  PIN in_data[221]
    DIRECTION INPUT ;
    USE SIGNAL ;
    ANTENNAGATEAREA 0.742500 ;
    PORT
      LAYER met2 ;
        RECT 1165.730 1296.000 1166.010 1300.000 ;
    END
  END in_data[221]
  PIN in_data[222]
    DIRECTION INPUT ;
    USE SIGNAL ;
    ANTENNAGATEAREA 0.426000 ;
    PORT
      LAYER met2 ;
        RECT 644.090 0.000 644.370 4.000 ;
    END
  END in_data[222]
  PIN in_data[223]
    DIRECTION INPUT ;
    USE SIGNAL ;
    ANTENNAGATEAREA 0.742500 ;
    PORT
      LAYER met2 ;
        RECT 312.430 0.000 312.710 4.000 ;
    END
  END in_data[223]
  PIN in_data[224]
    DIRECTION INPUT ;
    USE SIGNAL ;
    ANTENNAGATEAREA 0.742500 ;
    PORT
      LAYER met3 ;
        RECT 0.000 391.040 4.000 391.640 ;
    END
  END in_data[224]
  PIN in_data[225]
    DIRECTION INPUT ;
    USE SIGNAL ;
    ANTENNAGATEAREA 0.426000 ;
    PORT
      LAYER met2 ;
        RECT 724.590 1296.000 724.870 1300.000 ;
    END
  END in_data[225]
  PIN in_data[226]
    DIRECTION INPUT ;
    USE SIGNAL ;
    ANTENNAGATEAREA 0.742500 ;
    PORT
      LAYER met3 ;
        RECT 0.000 1084.640 4.000 1085.240 ;
    END
  END in_data[226]
  PIN in_data[227]
    DIRECTION INPUT ;
    USE SIGNAL ;
    ANTENNAGATEAREA 0.742500 ;
    PORT
      LAYER met2 ;
        RECT 341.410 0.000 341.690 4.000 ;
    END
  END in_data[227]
  PIN in_data[228]
    DIRECTION INPUT ;
    USE SIGNAL ;
    ANTENNAGATEAREA 0.742500 ;
    PORT
      LAYER met3 ;
        RECT 0.000 129.240 4.000 129.840 ;
    END
  END in_data[228]
  PIN in_data[229]
    DIRECTION INPUT ;
    USE SIGNAL ;
    ANTENNAGATEAREA 0.247500 ;
    PORT
      LAYER met2 ;
        RECT 547.490 1296.000 547.770 1300.000 ;
    END
  END in_data[229]
  PIN in_data[22]
    DIRECTION INPUT ;
    USE SIGNAL ;
    ANTENNAGATEAREA 0.426000 ;
    PORT
      LAYER met2 ;
        RECT 921.010 1296.000 921.290 1300.000 ;
    END
  END in_data[22]
  PIN in_data[230]
    DIRECTION INPUT ;
    USE SIGNAL ;
    ANTENNAGATEAREA 0.742500 ;
    PORT
      LAYER met3 ;
        RECT 1296.000 1251.240 1300.000 1251.840 ;
    END
  END in_data[230]
  PIN in_data[231]
    DIRECTION INPUT ;
    USE SIGNAL ;
    ANTENNAGATEAREA 0.742500 ;
    PORT
      LAYER met3 ;
        RECT 0.000 122.440 4.000 123.040 ;
    END
  END in_data[231]
  PIN in_data[232]
    DIRECTION INPUT ;
    USE SIGNAL ;
    ANTENNAGATEAREA 0.742500 ;
    PORT
      LAYER met2 ;
        RECT 1030.490 0.000 1030.770 4.000 ;
    END
  END in_data[232]
  PIN in_data[233]
    DIRECTION INPUT ;
    USE SIGNAL ;
    ANTENNAGATEAREA 0.742500 ;
    PORT
      LAYER met2 ;
        RECT 1207.590 1296.000 1207.870 1300.000 ;
    END
  END in_data[233]
  PIN in_data[234]
    DIRECTION INPUT ;
    USE SIGNAL ;
    ANTENNAGATEAREA 0.742500 ;
    PORT
      LAYER met2 ;
        RECT 1185.050 0.000 1185.330 4.000 ;
    END
  END in_data[234]
  PIN in_data[235]
    DIRECTION INPUT ;
    USE SIGNAL ;
    ANTENNAGATEAREA 0.742500 ;
    PORT
      LAYER met2 ;
        RECT 122.450 0.000 122.730 4.000 ;
    END
  END in_data[235]
  PIN in_data[236]
    DIRECTION INPUT ;
    USE SIGNAL ;
    ANTENNAGATEAREA 0.247500 ;
    PORT
      LAYER met2 ;
        RECT 528.170 1296.000 528.450 1300.000 ;
    END
  END in_data[236]
  PIN in_data[237]
    DIRECTION INPUT ;
    USE SIGNAL ;
    ANTENNAGATEAREA 0.742500 ;
    PORT
      LAYER met3 ;
        RECT 1296.000 102.040 1300.000 102.640 ;
    END
  END in_data[237]
  PIN in_data[238]
    DIRECTION INPUT ;
    USE SIGNAL ;
    ANTENNAGATEAREA 0.247500 ;
    PORT
      LAYER met2 ;
        RECT 611.890 0.000 612.170 4.000 ;
    END
  END in_data[238]
  PIN in_data[239]
    DIRECTION INPUT ;
    USE SIGNAL ;
    ANTENNAGATEAREA 0.495000 ;
    PORT
      LAYER met3 ;
        RECT 1296.000 911.240 1300.000 911.840 ;
    END
  END in_data[239]
  PIN in_data[23]
    DIRECTION INPUT ;
    USE SIGNAL ;
    ANTENNAGATEAREA 0.495000 ;
    PORT
      LAYER met2 ;
        RECT 1110.990 1296.000 1111.270 1300.000 ;
    END
  END in_data[23]
  PIN in_data[240]
    DIRECTION INPUT ;
    USE SIGNAL ;
    ANTENNAGATEAREA 0.852000 ;
    PORT
      LAYER met3 ;
        RECT 0.000 44.240 4.000 44.840 ;
    END
  END in_data[240]
  PIN in_data[241]
    DIRECTION INPUT ;
    USE SIGNAL ;
    ANTENNAGATEAREA 0.426000 ;
    PORT
      LAYER met2 ;
        RECT 653.750 0.000 654.030 4.000 ;
    END
  END in_data[241]
  PIN in_data[242]
    DIRECTION INPUT ;
    USE SIGNAL ;
    ANTENNAGATEAREA 0.495000 ;
    PORT
      LAYER met2 ;
        RECT 389.710 0.000 389.990 4.000 ;
    END
  END in_data[242]
  PIN in_data[243]
    DIRECTION INPUT ;
    USE SIGNAL ;
    ANTENNAGATEAREA 0.742500 ;
    PORT
      LAYER met3 ;
        RECT 0.000 1162.840 4.000 1163.440 ;
    END
  END in_data[243]
  PIN in_data[244]
    DIRECTION INPUT ;
    USE SIGNAL ;
    ANTENNAGATEAREA 0.742500 ;
    PORT
      LAYER met2 ;
        RECT 1020.830 0.000 1021.110 4.000 ;
    END
  END in_data[244]
  PIN in_data[245]
    DIRECTION INPUT ;
    USE SIGNAL ;
    ANTENNAGATEAREA 0.426000 ;
    PORT
      LAYER met3 ;
        RECT 0.000 493.040 4.000 493.640 ;
    END
  END in_data[245]
  PIN in_data[246]
    DIRECTION INPUT ;
    USE SIGNAL ;
    ANTENNAGATEAREA 0.247500 ;
    PORT
      LAYER met3 ;
        RECT 0.000 690.240 4.000 690.840 ;
    END
  END in_data[246]
  PIN in_data[247]
    DIRECTION INPUT ;
    USE SIGNAL ;
    ANTENNAGATEAREA 0.742500 ;
    PORT
      LAYER met3 ;
        RECT 0.000 1183.240 4.000 1183.840 ;
    END
  END in_data[247]
  PIN in_data[248]
    DIRECTION INPUT ;
    USE SIGNAL ;
    ANTENNAGATEAREA 0.742500 ;
    PORT
      LAYER met3 ;
        RECT 1296.000 1003.040 1300.000 1003.640 ;
    END
  END in_data[248]
  PIN in_data[249]
    DIRECTION INPUT ;
    USE SIGNAL ;
    ANTENNAGATEAREA 0.742500 ;
    PORT
      LAYER met2 ;
        RECT 19.410 1296.000 19.690 1300.000 ;
    END
  END in_data[249]
  PIN in_data[24]
    DIRECTION INPUT ;
    USE SIGNAL ;
    ANTENNAGATEAREA 0.742500 ;
    PORT
      LAYER met3 ;
        RECT 0.000 938.440 4.000 939.040 ;
    END
  END in_data[24]
  PIN in_data[250]
    DIRECTION INPUT ;
    USE SIGNAL ;
    ANTENNAGATEAREA 0.495000 ;
    PORT
      LAYER met3 ;
        RECT 0.000 1016.640 4.000 1017.240 ;
    END
  END in_data[250]
  PIN in_data[251]
    DIRECTION INPUT ;
    USE SIGNAL ;
    ANTENNAGATEAREA 0.742500 ;
    PORT
      LAYER met3 ;
        RECT 1296.000 1020.040 1300.000 1020.640 ;
    END
  END in_data[251]
  PIN in_data[252]
    DIRECTION INPUT ;
    USE SIGNAL ;
    ANTENNAGATEAREA 0.495000 ;
    PORT
      LAYER met3 ;
        RECT 1296.000 425.040 1300.000 425.640 ;
    END
  END in_data[252]
  PIN in_data[253]
    DIRECTION INPUT ;
    USE SIGNAL ;
    ANTENNAGATEAREA 0.742500 ;
    PORT
      LAYER met2 ;
        RECT 1136.750 1296.000 1137.030 1300.000 ;
    END
  END in_data[253]
  PIN in_data[254]
    DIRECTION INPUT ;
    USE SIGNAL ;
    ANTENNAGATEAREA 0.742500 ;
    PORT
      LAYER met2 ;
        RECT 132.110 1296.000 132.390 1300.000 ;
    END
  END in_data[254]
  PIN in_data[255]
    DIRECTION INPUT ;
    USE SIGNAL ;
    ANTENNAGATEAREA 0.247500 ;
    PORT
      LAYER met3 ;
        RECT 0.000 700.440 4.000 701.040 ;
    END
  END in_data[255]
  PIN in_data[256]
    DIRECTION INPUT ;
    USE SIGNAL ;
    ANTENNAGATEAREA 0.247500 ;
    PORT
      LAYER met3 ;
        RECT 0.000 816.040 4.000 816.640 ;
    END
  END in_data[256]
  PIN in_data[257]
    DIRECTION INPUT ;
    USE SIGNAL ;
    ANTENNAGATEAREA 0.742500 ;
    PORT
      LAYER met2 ;
        RECT 1139.970 1296.000 1140.250 1300.000 ;
    END
  END in_data[257]
  PIN in_data[258]
    DIRECTION INPUT ;
    USE SIGNAL ;
    ANTENNAGATEAREA 0.742500 ;
    PORT
      LAYER met2 ;
        RECT 74.150 1296.000 74.430 1300.000 ;
    END
  END in_data[258]
  PIN in_data[259]
    DIRECTION INPUT ;
    USE SIGNAL ;
    ANTENNAGATEAREA 0.426000 ;
    PORT
      LAYER met2 ;
        RECT 322.090 0.000 322.370 4.000 ;
    END
  END in_data[259]
  PIN in_data[25]
    DIRECTION INPUT ;
    USE SIGNAL ;
    ANTENNAGATEAREA 0.742500 ;
    PORT
      LAYER met3 ;
        RECT 1296.000 1210.440 1300.000 1211.040 ;
    END
  END in_data[25]
  PIN in_data[260]
    DIRECTION INPUT ;
    USE SIGNAL ;
    ANTENNAGATEAREA 0.495000 ;
    PORT
      LAYER met3 ;
        RECT 0.000 1077.840 4.000 1078.440 ;
    END
  END in_data[260]
  PIN in_data[261]
    DIRECTION INPUT ;
    USE SIGNAL ;
    ANTENNAGATEAREA 0.495000 ;
    PORT
      LAYER met3 ;
        RECT 1296.000 574.640 1300.000 575.240 ;
    END
  END in_data[261]
  PIN in_data[262]
    DIRECTION INPUT ;
    USE SIGNAL ;
    ANTENNAGATEAREA 0.247500 ;
    PORT
      LAYER met2 ;
        RECT 444.450 0.000 444.730 4.000 ;
    END
  END in_data[262]
  PIN in_data[263]
    DIRECTION INPUT ;
    USE SIGNAL ;
    ANTENNAGATEAREA 0.247500 ;
    PORT
      LAYER met3 ;
        RECT 0.000 537.240 4.000 537.840 ;
    END
  END in_data[263]
  PIN in_data[264]
    DIRECTION INPUT ;
    USE SIGNAL ;
    ANTENNAGATEAREA 0.495000 ;
    PORT
      LAYER met2 ;
        RECT 756.790 1296.000 757.070 1300.000 ;
    END
  END in_data[264]
  PIN in_data[265]
    DIRECTION INPUT ;
    USE SIGNAL ;
    ANTENNAGATEAREA 0.426000 ;
    PORT
      LAYER met3 ;
        RECT 0.000 935.040 4.000 935.640 ;
    END
  END in_data[265]
  PIN in_data[266]
    DIRECTION INPUT ;
    USE SIGNAL ;
    ANTENNAGATEAREA 0.247500 ;
    PORT
      LAYER met2 ;
        RECT 483.090 1296.000 483.370 1300.000 ;
    END
  END in_data[266]
  PIN in_data[267]
    DIRECTION INPUT ;
    USE SIGNAL ;
    ANTENNAGATEAREA 0.852000 ;
    PORT
      LAYER met2 ;
        RECT 1233.350 1296.000 1233.630 1300.000 ;
    END
  END in_data[267]
  PIN in_data[268]
    DIRECTION INPUT ;
    USE SIGNAL ;
    ANTENNAGATEAREA 0.495000 ;
    PORT
      LAYER met3 ;
        RECT 0.000 329.840 4.000 330.440 ;
    END
  END in_data[268]
  PIN in_data[269]
    DIRECTION INPUT ;
    USE SIGNAL ;
    ANTENNAGATEAREA 0.495000 ;
    PORT
      LAYER met2 ;
        RECT 264.130 1296.000 264.410 1300.000 ;
    END
  END in_data[269]
  PIN in_data[26]
    DIRECTION INPUT ;
    USE SIGNAL ;
    ANTENNAGATEAREA 0.742500 ;
    PORT
      LAYER met2 ;
        RECT 988.630 0.000 988.910 4.000 ;
    END
  END in_data[26]
  PIN in_data[270]
    DIRECTION INPUT ;
    USE SIGNAL ;
    ANTENNAGATEAREA 0.742500 ;
    PORT
      LAYER met2 ;
        RECT 998.290 0.000 998.570 4.000 ;
    END
  END in_data[270]
  PIN in_data[271]
    DIRECTION INPUT ;
    USE SIGNAL ;
    ANTENNAGATEAREA 0.852000 ;
    PORT
      LAYER met3 ;
        RECT 1296.000 1213.840 1300.000 1214.440 ;
    END
  END in_data[271]
  PIN in_data[272]
    DIRECTION INPUT ;
    USE SIGNAL ;
    ANTENNAGATEAREA 0.495000 ;
    PORT
      LAYER met3 ;
        RECT 0.000 234.640 4.000 235.240 ;
    END
  END in_data[272]
  PIN in_data[273]
    DIRECTION INPUT ;
    USE SIGNAL ;
    ANTENNAGATEAREA 0.742500 ;
    PORT
      LAYER met2 ;
        RECT 90.250 0.000 90.530 4.000 ;
    END
  END in_data[273]
  PIN in_data[274]
    DIRECTION INPUT ;
    USE SIGNAL ;
    ANTENNAGATEAREA 0.742500 ;
    PORT
      LAYER met3 ;
        RECT 0.000 159.840 4.000 160.440 ;
    END
  END in_data[274]
  PIN in_data[275]
    DIRECTION INPUT ;
    USE SIGNAL ;
    ANTENNAGATEAREA 0.495000 ;
    PORT
      LAYER met2 ;
        RECT 196.510 1296.000 196.790 1300.000 ;
    END
  END in_data[275]
  PIN in_data[276]
    DIRECTION INPUT ;
    USE SIGNAL ;
    ANTENNAGATEAREA 0.742500 ;
    PORT
      LAYER met2 ;
        RECT 914.570 1296.000 914.850 1300.000 ;
    END
  END in_data[276]
  PIN in_data[277]
    DIRECTION INPUT ;
    USE SIGNAL ;
    ANTENNAGATEAREA 0.742500 ;
    PORT
      LAYER met3 ;
        RECT 0.000 95.240 4.000 95.840 ;
    END
  END in_data[277]
  PIN in_data[278]
    DIRECTION INPUT ;
    USE SIGNAL ;
    ANTENNAGATEAREA 0.742500 ;
    PORT
      LAYER met3 ;
        RECT 1296.000 187.040 1300.000 187.640 ;
    END
  END in_data[278]
  PIN in_data[279]
    DIRECTION INPUT ;
    USE SIGNAL ;
    ANTENNAGATEAREA 0.742500 ;
    PORT
      LAYER met3 ;
        RECT 0.000 1275.040 4.000 1275.640 ;
    END
  END in_data[279]
  PIN in_data[27]
    DIRECTION INPUT ;
    USE SIGNAL ;
    ANTENNAGATEAREA 0.426000 ;
    PORT
      LAYER met3 ;
        RECT 1296.000 870.440 1300.000 871.040 ;
    END
  END in_data[27]
  PIN in_data[280]
    DIRECTION INPUT ;
    USE SIGNAL ;
    ANTENNAGATEAREA 0.742500 ;
    PORT
      LAYER met3 ;
        RECT 1296.000 1105.040 1300.000 1105.640 ;
    END
  END in_data[280]
  PIN in_data[281]
    DIRECTION INPUT ;
    USE SIGNAL ;
    ANTENNAGATEAREA 0.247500 ;
    PORT
      LAYER met3 ;
        RECT 0.000 707.240 4.000 707.840 ;
    END
  END in_data[281]
  PIN in_data[282]
    DIRECTION INPUT ;
    USE SIGNAL ;
    ANTENNAGATEAREA 0.426000 ;
    PORT
      LAYER met3 ;
        RECT 0.000 965.640 4.000 966.240 ;
    END
  END in_data[282]
  PIN in_data[283]
    DIRECTION INPUT ;
    USE SIGNAL ;
    ANTENNAGATEAREA 0.247500 ;
    PORT
      LAYER met3 ;
        RECT 0.000 768.440 4.000 769.040 ;
    END
  END in_data[283]
  PIN in_data[284]
    DIRECTION INPUT ;
    USE SIGNAL ;
    ANTENNAGATEAREA 0.742500 ;
    PORT
      LAYER met3 ;
        RECT 1296.000 836.440 1300.000 837.040 ;
    END
  END in_data[284]
  PIN in_data[285]
    DIRECTION INPUT ;
    USE SIGNAL ;
    ANTENNAGATEAREA 0.247500 ;
    PORT
      LAYER met2 ;
        RECT 557.150 0.000 557.430 4.000 ;
    END
  END in_data[285]
  PIN in_data[286]
    DIRECTION INPUT ;
    USE SIGNAL ;
    ANTENNAGATEAREA 0.426000 ;
    PORT
      LAYER met2 ;
        RECT 586.130 1296.000 586.410 1300.000 ;
    END
  END in_data[286]
  PIN in_data[287]
    DIRECTION INPUT ;
    USE SIGNAL ;
    ANTENNAGATEAREA 0.247500 ;
    PORT
      LAYER met2 ;
        RECT 602.230 0.000 602.510 4.000 ;
    END
  END in_data[287]
  PIN in_data[288]
    DIRECTION INPUT ;
    USE SIGNAL ;
    ANTENNAGATEAREA 0.742500 ;
    PORT
      LAYER met3 ;
        RECT 1296.000 1094.840 1300.000 1095.440 ;
    END
  END in_data[288]
  PIN in_data[289]
    DIRECTION INPUT ;
    USE SIGNAL ;
    ANTENNAGATEAREA 0.742500 ;
    PORT
      LAYER met3 ;
        RECT 1296.000 377.440 1300.000 378.040 ;
    END
  END in_data[289]
  PIN in_data[28]
    DIRECTION INPUT ;
    USE SIGNAL ;
    ANTENNAGATEAREA 0.742500 ;
    PORT
      LAYER met3 ;
        RECT 1296.000 1081.240 1300.000 1081.840 ;
    END
  END in_data[28]
  PIN in_data[290]
    DIRECTION INPUT ;
    USE SIGNAL ;
    ANTENNAGATEAREA 0.742500 ;
    PORT
      LAYER met2 ;
        RECT 982.190 1296.000 982.470 1300.000 ;
    END
  END in_data[290]
  PIN in_data[291]
    DIRECTION INPUT ;
    USE SIGNAL ;
    ANTENNAGATEAREA 0.495000 ;
    PORT
      LAYER met2 ;
        RECT 869.490 0.000 869.770 4.000 ;
    END
  END in_data[291]
  PIN in_data[292]
    DIRECTION INPUT ;
    USE SIGNAL ;
    ANTENNAGATEAREA 0.742500 ;
    PORT
      LAYER met3 ;
        RECT 0.000 214.240 4.000 214.840 ;
    END
  END in_data[292]
  PIN in_data[293]
    DIRECTION INPUT ;
    USE SIGNAL ;
    ANTENNAGATEAREA 0.742500 ;
    PORT
      LAYER met2 ;
        RECT 116.010 1296.000 116.290 1300.000 ;
    END
  END in_data[293]
  PIN in_data[294]
    DIRECTION INPUT ;
    USE SIGNAL ;
    ANTENNAGATEAREA 0.426000 ;
    PORT
      LAYER met3 ;
        RECT 0.000 839.840 4.000 840.440 ;
    END
  END in_data[294]
  PIN in_data[295]
    DIRECTION INPUT ;
    USE SIGNAL ;
    ANTENNAGATEAREA 0.495000 ;
    PORT
      LAYER met3 ;
        RECT 1296.000 812.640 1300.000 813.240 ;
    END
  END in_data[295]
  PIN in_data[296]
    DIRECTION INPUT ;
    USE SIGNAL ;
    ANTENNAGATEAREA 0.742500 ;
    PORT
      LAYER met3 ;
        RECT 0.000 112.240 4.000 112.840 ;
    END
  END in_data[296]
  PIN in_data[297]
    DIRECTION INPUT ;
    USE SIGNAL ;
    ANTENNAGATEAREA 0.247500 ;
    PORT
      LAYER met3 ;
        RECT 0.000 656.240 4.000 656.840 ;
    END
  END in_data[297]
  PIN in_data[298]
    DIRECTION INPUT ;
    USE SIGNAL ;
    ANTENNAGATEAREA 0.426000 ;
    PORT
      LAYER met2 ;
        RECT 669.850 0.000 670.130 4.000 ;
    END
  END in_data[298]
  PIN in_data[299]
    DIRECTION INPUT ;
    USE SIGNAL ;
    ANTENNAGATEAREA 0.742500 ;
    PORT
      LAYER met2 ;
        RECT 991.850 1296.000 992.130 1300.000 ;
    END
  END in_data[299]
  PIN in_data[29]
    DIRECTION INPUT ;
    USE SIGNAL ;
    ANTENNAGATEAREA 0.247500 ;
    PORT
      LAYER met3 ;
        RECT 0.000 809.240 4.000 809.840 ;
    END
  END in_data[29]
  PIN in_data[2]
    DIRECTION INPUT ;
    USE SIGNAL ;
    ANTENNAGATEAREA 0.426000 ;
    PORT
      LAYER met3 ;
        RECT 1296.000 863.640 1300.000 864.240 ;
    END
  END in_data[2]
  PIN in_data[300]
    DIRECTION INPUT ;
    USE SIGNAL ;
    ANTENNAGATEAREA 0.742500 ;
    PORT
      LAYER met3 ;
        RECT 0.000 1057.440 4.000 1058.040 ;
    END
  END in_data[300]
  PIN in_data[301]
    DIRECTION INPUT ;
    USE SIGNAL ;
    ANTENNAGATEAREA 0.742500 ;
    PORT
      LAYER met2 ;
        RECT 943.550 0.000 943.830 4.000 ;
    END
  END in_data[301]
  PIN in_data[302]
    DIRECTION INPUT ;
    USE SIGNAL ;
    ANTENNAGATEAREA 0.742500 ;
    PORT
      LAYER met3 ;
        RECT 1296.000 268.640 1300.000 269.240 ;
    END
  END in_data[302]
  PIN in_data[303]
    DIRECTION INPUT ;
    USE SIGNAL ;
    ANTENNAGATEAREA 0.495000 ;
    PORT
      LAYER met3 ;
        RECT 1296.000 567.840 1300.000 568.440 ;
    END
  END in_data[303]
  PIN in_data[304]
    DIRECTION INPUT ;
    USE SIGNAL ;
    ANTENNAGATEAREA 0.742500 ;
    PORT
      LAYER met2 ;
        RECT 840.510 1296.000 840.790 1300.000 ;
    END
  END in_data[304]
  PIN in_data[305]
    DIRECTION INPUT ;
    USE SIGNAL ;
    ANTENNAGATEAREA 0.247500 ;
    PORT
      LAYER met2 ;
        RECT 508.850 0.000 509.130 4.000 ;
    END
  END in_data[305]
  PIN in_data[306]
    DIRECTION INPUT ;
    USE SIGNAL ;
    ANTENNAGATEAREA 0.742500 ;
    PORT
      LAYER met2 ;
        RECT 904.910 0.000 905.190 4.000 ;
    END
  END in_data[306]
  PIN in_data[307]
    DIRECTION INPUT ;
    USE SIGNAL ;
    ANTENNAGATEAREA 0.426000 ;
    PORT
      LAYER met3 ;
        RECT 0.000 873.840 4.000 874.440 ;
    END
  END in_data[307]
  PIN in_data[308]
    DIRECTION INPUT ;
    USE SIGNAL ;
    ANTENNAGATEAREA 0.247500 ;
    PORT
      LAYER met3 ;
        RECT 0.000 567.840 4.000 568.440 ;
    END
  END in_data[308]
  PIN in_data[309]
    DIRECTION INPUT ;
    USE SIGNAL ;
    ANTENNAGATEAREA 0.852000 ;
    PORT
      LAYER met3 ;
        RECT 1296.000 1173.040 1300.000 1173.640 ;
    END
  END in_data[309]
  PIN in_data[30]
    DIRECTION INPUT ;
    USE SIGNAL ;
    ANTENNAGATEAREA 0.247500 ;
    PORT
      LAYER met2 ;
        RECT 640.870 1296.000 641.150 1300.000 ;
    END
  END in_data[30]
  PIN in_data[310]
    DIRECTION INPUT ;
    USE SIGNAL ;
    ANTENNAGATEAREA 0.742500 ;
    PORT
      LAYER met2 ;
        RECT 949.990 0.000 950.270 4.000 ;
    END
  END in_data[310]
  PIN in_data[311]
    DIRECTION INPUT ;
    USE SIGNAL ;
    ANTENNAGATEAREA 0.426000 ;
    PORT
      LAYER met3 ;
        RECT 0.000 479.440 4.000 480.040 ;
    END
  END in_data[311]
  PIN in_data[312]
    DIRECTION INPUT ;
    USE SIGNAL ;
    ANTENNAGATEAREA 0.742500 ;
    PORT
      LAYER met3 ;
        RECT 0.000 224.440 4.000 225.040 ;
    END
  END in_data[312]
  PIN in_data[313]
    DIRECTION INPUT ;
    USE SIGNAL ;
    ANTENNAGATEAREA 0.742500 ;
    PORT
      LAYER met2 ;
        RECT 875.930 1296.000 876.210 1300.000 ;
    END
  END in_data[313]
  PIN in_data[314]
    DIRECTION INPUT ;
    USE SIGNAL ;
    ANTENNAGATEAREA 0.426000 ;
    PORT
      LAYER met2 ;
        RECT 360.730 0.000 361.010 4.000 ;
    END
  END in_data[314]
  PIN in_data[315]
    DIRECTION INPUT ;
    USE SIGNAL ;
    ANTENNAGATEAREA 0.852000 ;
    PORT
      LAYER met2 ;
        RECT 1246.230 0.000 1246.510 4.000 ;
    END
  END in_data[315]
  PIN in_data[316]
    DIRECTION INPUT ;
    USE SIGNAL ;
    ANTENNAGATEAREA 0.426000 ;
    PORT
      LAYER met3 ;
        RECT 0.000 499.840 4.000 500.440 ;
    END
  END in_data[316]
  PIN in_data[317]
    DIRECTION INPUT ;
    USE SIGNAL ;
    ANTENNAGATEAREA 0.247500 ;
    PORT
      LAYER met2 ;
        RECT 541.050 0.000 541.330 4.000 ;
    END
  END in_data[317]
  PIN in_data[318]
    DIRECTION INPUT ;
    USE SIGNAL ;
    ANTENNAGATEAREA 0.495000 ;
    PORT
      LAYER met3 ;
        RECT 0.000 1067.640 4.000 1068.240 ;
    END
  END in_data[318]
  PIN in_data[319]
    DIRECTION INPUT ;
    USE SIGNAL ;
    ANTENNAGATEAREA 0.426000 ;
    PORT
      LAYER met2 ;
        RECT 660.190 1296.000 660.470 1300.000 ;
    END
  END in_data[319]
  PIN in_data[31]
    DIRECTION INPUT ;
    USE SIGNAL ;
    ANTENNAGATEAREA 0.495000 ;
    PORT
      LAYER met3 ;
        RECT 0.000 1142.440 4.000 1143.040 ;
    END
  END in_data[31]
  PIN in_data[320]
    DIRECTION INPUT ;
    USE SIGNAL ;
    ANTENNAGATEAREA 0.742500 ;
    PORT
      LAYER met2 ;
        RECT 273.790 1296.000 274.070 1300.000 ;
    END
  END in_data[320]
  PIN in_data[321]
    DIRECTION INPUT ;
    USE SIGNAL ;
    ANTENNAGATEAREA 0.495000 ;
    PORT
      LAYER met3 ;
        RECT 1296.000 476.040 1300.000 476.640 ;
    END
  END in_data[321]
  PIN in_data[322]
    DIRECTION INPUT ;
    USE SIGNAL ;
    ANTENNAGATEAREA 0.495000 ;
    PORT
      LAYER met3 ;
        RECT 0.000 914.640 4.000 915.240 ;
    END
  END in_data[322]
  PIN in_data[323]
    DIRECTION INPUT ;
    USE SIGNAL ;
    ANTENNAGATEAREA 0.742500 ;
    PORT
      LAYER met2 ;
        RECT 927.450 0.000 927.730 4.000 ;
    END
  END in_data[323]
  PIN in_data[324]
    DIRECTION INPUT ;
    USE SIGNAL ;
    ANTENNAGATEAREA 0.742500 ;
    PORT
      LAYER met3 ;
        RECT 1296.000 1091.440 1300.000 1092.040 ;
    END
  END in_data[324]
  PIN in_data[325]
    DIRECTION INPUT ;
    USE SIGNAL ;
    ANTENNAGATEAREA 0.426000 ;
    PORT
      LAYER met2 ;
        RECT 727.810 1296.000 728.090 1300.000 ;
    END
  END in_data[325]
  PIN in_data[326]
    DIRECTION INPUT ;
    USE SIGNAL ;
    ANTENNAGATEAREA 0.742500 ;
    PORT
      LAYER met3 ;
        RECT 1296.000 945.240 1300.000 945.840 ;
    END
  END in_data[326]
  PIN in_data[327]
    DIRECTION INPUT ;
    USE SIGNAL ;
    ANTENNAGATEAREA 0.426000 ;
    PORT
      LAYER met2 ;
        RECT 380.050 0.000 380.330 4.000 ;
    END
  END in_data[327]
  PIN in_data[328]
    DIRECTION INPUT ;
    USE SIGNAL ;
    ANTENNAGATEAREA 0.426000 ;
    PORT
      LAYER met2 ;
        RECT 351.070 0.000 351.350 4.000 ;
    END
  END in_data[328]
  PIN in_data[329]
    DIRECTION INPUT ;
    USE SIGNAL ;
    ANTENNAGATEAREA 0.742500 ;
    PORT
      LAYER met2 ;
        RECT 1110.990 0.000 1111.270 4.000 ;
    END
  END in_data[329]
  PIN in_data[32]
    DIRECTION INPUT ;
    USE SIGNAL ;
    ANTENNAGATEAREA 0.495000 ;
    PORT
      LAYER met3 ;
        RECT 0.000 561.040 4.000 561.640 ;
    END
  END in_data[32]
  PIN in_data[330]
    DIRECTION INPUT ;
    USE SIGNAL ;
    ANTENNAGATEAREA 0.495000 ;
    PORT
      LAYER met3 ;
        RECT 1296.000 469.240 1300.000 469.840 ;
    END
  END in_data[330]
  PIN in_data[331]
    DIRECTION INPUT ;
    USE SIGNAL ;
    ANTENNAGATEAREA 0.495000 ;
    PORT
      LAYER met2 ;
        RECT 937.110 0.000 937.390 4.000 ;
    END
  END in_data[331]
  PIN in_data[332]
    DIRECTION INPUT ;
    USE SIGNAL ;
    ANTENNAGATEAREA 0.426000 ;
    PORT
      LAYER met2 ;
        RECT 470.210 1296.000 470.490 1300.000 ;
    END
  END in_data[332]
  PIN in_data[333]
    DIRECTION INPUT ;
    USE SIGNAL ;
    ANTENNAGATEAREA 0.247500 ;
    PORT
      LAYER met2 ;
        RECT 531.390 0.000 531.670 4.000 ;
    END
  END in_data[333]
  PIN in_data[334]
    DIRECTION INPUT ;
    USE SIGNAL ;
    ANTENNAGATEAREA 0.742500 ;
    PORT
      LAYER met3 ;
        RECT 0.000 1026.840 4.000 1027.440 ;
    END
  END in_data[334]
  PIN in_data[335]
    DIRECTION INPUT ;
    USE SIGNAL ;
    ANTENNAGATEAREA 0.742500 ;
    PORT
      LAYER met2 ;
        RECT 77.370 1296.000 77.650 1300.000 ;
    END
  END in_data[335]
  PIN in_data[336]
    DIRECTION INPUT ;
    USE SIGNAL ;
    ANTENNAGATEAREA 0.742500 ;
    PORT
      LAYER met3 ;
        RECT 1296.000 156.440 1300.000 157.040 ;
    END
  END in_data[336]
  PIN in_data[337]
    DIRECTION INPUT ;
    USE SIGNAL ;
    ANTENNAGATEAREA 0.426000 ;
    PORT
      LAYER met3 ;
        RECT 0.000 431.840 4.000 432.440 ;
    END
  END in_data[337]
  PIN in_data[338]
    DIRECTION INPUT ;
    USE SIGNAL ;
    ANTENNAGATEAREA 0.495000 ;
    PORT
      LAYER met2 ;
        RECT 962.870 0.000 963.150 4.000 ;
    END
  END in_data[338]
  PIN in_data[339]
    DIRECTION INPUT ;
    USE SIGNAL ;
    ANTENNAGATEAREA 0.495000 ;
    PORT
      LAYER met3 ;
        RECT 1296.000 336.640 1300.000 337.240 ;
    END
  END in_data[339]
  PIN in_data[33]
    DIRECTION INPUT ;
    USE SIGNAL ;
    ANTENNAGATEAREA 0.742500 ;
    PORT
      LAYER met2 ;
        RECT 186.850 1296.000 187.130 1300.000 ;
    END
  END in_data[33]
  PIN in_data[340]
    DIRECTION INPUT ;
    USE SIGNAL ;
    ANTENNAGATEAREA 0.426000 ;
    PORT
      LAYER met2 ;
        RECT 444.450 1296.000 444.730 1300.000 ;
    END
  END in_data[340]
  PIN in_data[341]
    DIRECTION INPUT ;
    USE SIGNAL ;
    ANTENNAGATEAREA 0.495000 ;
    PORT
      LAYER met3 ;
        RECT 0.000 312.840 4.000 313.440 ;
    END
  END in_data[341]
  PIN in_data[342]
    DIRECTION INPUT ;
    USE SIGNAL ;
    ANTENNAGATEAREA 0.426000 ;
    PORT
      LAYER met2 ;
        RECT 708.490 1296.000 708.770 1300.000 ;
    END
  END in_data[342]
  PIN in_data[343]
    DIRECTION INPUT ;
    USE SIGNAL ;
    ANTENNAGATEAREA 0.426000 ;
    PORT
      LAYER met3 ;
        RECT 0.000 516.840 4.000 517.440 ;
    END
  END in_data[343]
  PIN in_data[344]
    DIRECTION INPUT ;
    USE SIGNAL ;
    ANTENNAGATEAREA 0.742500 ;
    PORT
      LAYER met3 ;
        RECT 0.000 1006.440 4.000 1007.040 ;
    END
  END in_data[344]
  PIN in_data[345]
    DIRECTION INPUT ;
    USE SIGNAL ;
    ANTENNAGATEAREA 0.742500 ;
    PORT
      LAYER met3 ;
        RECT 0.000 105.440 4.000 106.040 ;
    END
  END in_data[345]
  PIN in_data[346]
    DIRECTION INPUT ;
    USE SIGNAL ;
    ANTENNAGATEAREA 0.247500 ;
    PORT
      LAYER met3 ;
        RECT 0.000 581.440 4.000 582.040 ;
    END
  END in_data[346]
  PIN in_data[347]
    DIRECTION INPUT ;
    USE SIGNAL ;
    ANTENNAGATEAREA 0.495000 ;
    PORT
      LAYER met2 ;
        RECT 302.770 1296.000 303.050 1300.000 ;
    END
  END in_data[347]
  PIN in_data[348]
    DIRECTION INPUT ;
    USE SIGNAL ;
    ANTENNAGATEAREA 0.495000 ;
    PORT
      LAYER met2 ;
        RECT 846.950 1296.000 847.230 1300.000 ;
    END
  END in_data[348]
  PIN in_data[349]
    DIRECTION INPUT ;
    USE SIGNAL ;
    ANTENNAGATEAREA 0.742500 ;
    PORT
      LAYER met3 ;
        RECT 0.000 71.440 4.000 72.040 ;
    END
  END in_data[349]
  PIN in_data[34]
    DIRECTION INPUT ;
    USE SIGNAL ;
    ANTENNAGATEAREA 0.495000 ;
    PORT
      LAYER met3 ;
        RECT 0.000 588.240 4.000 588.840 ;
    END
  END in_data[34]
  PIN in_data[350]
    DIRECTION INPUT ;
    USE SIGNAL ;
    ANTENNAGATEAREA 0.742500 ;
    PORT
      LAYER met3 ;
        RECT 1296.000 129.240 1300.000 129.840 ;
    END
  END in_data[350]
  PIN in_data[351]
    DIRECTION INPUT ;
    USE SIGNAL ;
    ANTENNAGATEAREA 0.742500 ;
    PORT
      LAYER met3 ;
        RECT 1296.000 1139.040 1300.000 1139.640 ;
    END
  END in_data[351]
  PIN in_data[352]
    DIRECTION INPUT ;
    USE SIGNAL ;
    ANTENNAGATEAREA 0.247500 ;
    PORT
      LAYER met2 ;
        RECT 570.030 0.000 570.310 4.000 ;
    END
  END in_data[352]
  PIN in_data[353]
    DIRECTION INPUT ;
    USE SIGNAL ;
    ANTENNAGATEAREA 0.426000 ;
    PORT
      LAYER met3 ;
        RECT 0.000 540.640 4.000 541.240 ;
    END
  END in_data[353]
  PIN in_data[354]
    DIRECTION INPUT ;
    USE SIGNAL ;
    ANTENNAGATEAREA 0.742500 ;
    PORT
      LAYER met3 ;
        RECT 0.000 231.240 4.000 231.840 ;
    END
  END in_data[354]
  PIN in_data[355]
    DIRECTION INPUT ;
    USE SIGNAL ;
    ANTENNAGATEAREA 0.426000 ;
    PORT
      LAYER met3 ;
        RECT 1296.000 605.240 1300.000 605.840 ;
    END
  END in_data[355]
  PIN in_data[356]
    DIRECTION INPUT ;
    USE SIGNAL ;
    ANTENNAGATEAREA 0.495000 ;
    PORT
      LAYER met3 ;
        RECT 1296.000 350.240 1300.000 350.840 ;
    END
  END in_data[356]
  PIN in_data[357]
    DIRECTION INPUT ;
    USE SIGNAL ;
    ANTENNAGATEAREA 0.742500 ;
    PORT
      LAYER met3 ;
        RECT 0.000 1264.840 4.000 1265.440 ;
    END
  END in_data[357]
  PIN in_data[358]
    DIRECTION INPUT ;
    USE SIGNAL ;
    ANTENNAGATEAREA 0.852000 ;
    PORT
      LAYER met2 ;
        RECT 1243.010 1296.000 1243.290 1300.000 ;
    END
  END in_data[358]
  PIN in_data[359]
    DIRECTION INPUT ;
    USE SIGNAL ;
    ANTENNAGATEAREA 0.852000 ;
    PORT
      LAYER met2 ;
        RECT 1214.030 1296.000 1214.310 1300.000 ;
    END
  END in_data[359]
  PIN in_data[35]
    DIRECTION INPUT ;
    USE SIGNAL ;
    ANTENNAGATEAREA 0.426000 ;
    PORT
      LAYER met3 ;
        RECT 0.000 928.240 4.000 928.840 ;
    END
  END in_data[35]
  PIN in_data[360]
    DIRECTION INPUT ;
    USE SIGNAL ;
    ANTENNAGATEAREA 0.495000 ;
    PORT
      LAYER met3 ;
        RECT 1296.000 771.840 1300.000 772.440 ;
    END
  END in_data[360]
  PIN in_data[361]
    DIRECTION INPUT ;
    USE SIGNAL ;
    ANTENNAGATEAREA 0.495000 ;
    PORT
      LAYER met3 ;
        RECT 0.000 955.440 4.000 956.040 ;
    END
  END in_data[361]
  PIN in_data[362]
    DIRECTION INPUT ;
    USE SIGNAL ;
    ANTENNAGATEAREA 0.742500 ;
    PORT
      LAYER met2 ;
        RECT 1040.150 0.000 1040.430 4.000 ;
    END
  END in_data[362]
  PIN in_data[363]
    DIRECTION INPUT ;
    USE SIGNAL ;
    ANTENNAGATEAREA 0.495000 ;
    PORT
      LAYER met3 ;
        RECT 1296.000 894.240 1300.000 894.840 ;
    END
  END in_data[363]
  PIN in_data[364]
    DIRECTION INPUT ;
    USE SIGNAL ;
    ANTENNAGATEAREA 0.426000 ;
    PORT
      LAYER met2 ;
        RECT 460.550 1296.000 460.830 1300.000 ;
    END
  END in_data[364]
  PIN in_data[365]
    DIRECTION INPUT ;
    USE SIGNAL ;
    ANTENNAGATEAREA 0.742500 ;
    PORT
      LAYER met2 ;
        RECT 1188.270 1296.000 1188.550 1300.000 ;
    END
  END in_data[365]
  PIN in_data[366]
    DIRECTION INPUT ;
    USE SIGNAL ;
    ANTENNAGATEAREA 0.426000 ;
    PORT
      LAYER met2 ;
        RECT 705.270 1296.000 705.550 1300.000 ;
    END
  END in_data[366]
  PIN in_data[367]
    DIRECTION INPUT ;
    USE SIGNAL ;
    ANTENNAGATEAREA 0.495000 ;
    PORT
      LAYER met2 ;
        RECT 821.190 1296.000 821.470 1300.000 ;
    END
  END in_data[367]
  PIN in_data[368]
    DIRECTION INPUT ;
    USE SIGNAL ;
    ANTENNAGATEAREA 0.852000 ;
    PORT
      LAYER met3 ;
        RECT 1296.000 68.040 1300.000 68.640 ;
    END
  END in_data[368]
  PIN in_data[369]
    DIRECTION INPUT ;
    USE SIGNAL ;
    ANTENNAGATEAREA 0.742500 ;
    PORT
      LAYER met2 ;
        RECT 1159.290 1296.000 1159.570 1300.000 ;
    END
  END in_data[369]
  PIN in_data[36]
    DIRECTION INPUT ;
    USE SIGNAL ;
    ANTENNAGATEAREA 0.742500 ;
    PORT
      LAYER met3 ;
        RECT 0.000 170.040 4.000 170.640 ;
    END
  END in_data[36]
  PIN in_data[370]
    DIRECTION INPUT ;
    USE SIGNAL ;
    ANTENNAGATEAREA 0.742500 ;
    PORT
      LAYER met2 ;
        RECT 1017.610 0.000 1017.890 4.000 ;
    END
  END in_data[370]
  PIN in_data[371]
    DIRECTION INPUT ;
    USE SIGNAL ;
    ANTENNAGATEAREA 0.742500 ;
    PORT
      LAYER met3 ;
        RECT 1296.000 210.840 1300.000 211.440 ;
    END
  END in_data[371]
  PIN in_data[372]
    DIRECTION INPUT ;
    USE SIGNAL ;
    ANTENNAGATEAREA 0.742500 ;
    PORT
      LAYER met2 ;
        RECT 283.450 1296.000 283.730 1300.000 ;
    END
  END in_data[372]
  PIN in_data[373]
    DIRECTION INPUT ;
    USE SIGNAL ;
    ANTENNAGATEAREA 0.742500 ;
    PORT
      LAYER met2 ;
        RECT 982.190 0.000 982.470 4.000 ;
    END
  END in_data[373]
  PIN in_data[374]
    DIRECTION INPUT ;
    USE SIGNAL ;
    ANTENNAGATEAREA 0.426000 ;
    PORT
      LAYER met2 ;
        RECT 737.470 1296.000 737.750 1300.000 ;
    END
  END in_data[374]
  PIN in_data[375]
    DIRECTION INPUT ;
    USE SIGNAL ;
    ANTENNAGATEAREA 0.426000 ;
    PORT
      LAYER met2 ;
        RECT 679.510 1296.000 679.790 1300.000 ;
    END
  END in_data[375]
  PIN in_data[376]
    DIRECTION INPUT ;
    USE SIGNAL ;
    ANTENNAGATEAREA 0.742500 ;
    PORT
      LAYER met3 ;
        RECT 1296.000 1074.440 1300.000 1075.040 ;
    END
  END in_data[376]
  PIN in_data[377]
    DIRECTION INPUT ;
    USE SIGNAL ;
    ANTENNAGATEAREA 0.742500 ;
    PORT
      LAYER met2 ;
        RECT 254.470 1296.000 254.750 1300.000 ;
    END
  END in_data[377]
  PIN in_data[378]
    DIRECTION INPUT ;
    USE SIGNAL ;
    ANTENNAGATEAREA 0.426000 ;
    PORT
      LAYER met2 ;
        RECT 454.110 1296.000 454.390 1300.000 ;
    END
  END in_data[378]
  PIN in_data[379]
    DIRECTION INPUT ;
    USE SIGNAL ;
    ANTENNAGATEAREA 0.426000 ;
    PORT
      LAYER met2 ;
        RECT 508.850 1296.000 509.130 1300.000 ;
    END
  END in_data[379]
  PIN in_data[37]
    DIRECTION INPUT ;
    USE SIGNAL ;
    ANTENNAGATEAREA 0.495000 ;
    PORT
      LAYER met3 ;
        RECT 0.000 1033.640 4.000 1034.240 ;
    END
  END in_data[37]
  PIN in_data[380]
    DIRECTION INPUT ;
    USE SIGNAL ;
    ANTENNAGATEAREA 0.742500 ;
    PORT
      LAYER met2 ;
        RECT 244.810 1296.000 245.090 1300.000 ;
    END
  END in_data[380]
  PIN in_data[381]
    DIRECTION INPUT ;
    USE SIGNAL ;
    ANTENNAGATEAREA 0.742500 ;
    PORT
      LAYER met2 ;
        RECT 1027.270 0.000 1027.550 4.000 ;
    END
  END in_data[381]
  PIN in_data[382]
    DIRECTION INPUT ;
    USE SIGNAL ;
    ANTENNAGATEAREA 0.742500 ;
    PORT
      LAYER met3 ;
        RECT 0.000 1254.640 4.000 1255.240 ;
    END
  END in_data[382]
  PIN in_data[383]
    DIRECTION INPUT ;
    USE SIGNAL ;
    ANTENNAGATEAREA 0.426000 ;
    PORT
      LAYER met3 ;
        RECT 1296.000 622.240 1300.000 622.840 ;
    END
  END in_data[383]
  PIN in_data[384]
    DIRECTION INPUT ;
    USE SIGNAL ;
    ANTENNAGATEAREA 0.426000 ;
    PORT
      LAYER met2 ;
        RECT 428.350 0.000 428.630 4.000 ;
    END
  END in_data[384]
  PIN in_data[385]
    DIRECTION INPUT ;
    USE SIGNAL ;
    ANTENNAGATEAREA 0.426000 ;
    PORT
      LAYER met3 ;
        RECT 0.000 380.840 4.000 381.440 ;
    END
  END in_data[385]
  PIN in_data[386]
    DIRECTION INPUT ;
    USE SIGNAL ;
    ANTENNAGATEAREA 0.742500 ;
    PORT
      LAYER met2 ;
        RECT 1197.930 1296.000 1198.210 1300.000 ;
    END
  END in_data[386]
  PIN in_data[387]
    DIRECTION INPUT ;
    USE SIGNAL ;
    ANTENNAGATEAREA 0.742500 ;
    PORT
      LAYER met2 ;
        RECT 1062.690 0.000 1062.970 4.000 ;
    END
  END in_data[387]
  PIN in_data[388]
    DIRECTION INPUT ;
    USE SIGNAL ;
    ANTENNAGATEAREA 0.742500 ;
    PORT
      LAYER met3 ;
        RECT 1296.000 309.440 1300.000 310.040 ;
    END
  END in_data[388]
  PIN in_data[389]
    DIRECTION INPUT ;
    USE SIGNAL ;
    ANTENNAGATEAREA 0.247500 ;
    PORT
      LAYER met3 ;
        RECT 0.000 618.840 4.000 619.440 ;
    END
  END in_data[389]
  PIN in_data[38]
    DIRECTION INPUT ;
    USE SIGNAL ;
    ANTENNAGATEAREA 0.247500 ;
    PORT
      LAYER met3 ;
        RECT 0.000 727.640 4.000 728.240 ;
    END
  END in_data[38]
  PIN in_data[390]
    DIRECTION INPUT ;
    USE SIGNAL ;
    ANTENNAGATEAREA 0.495000 ;
    PORT
      LAYER met3 ;
        RECT 0.000 221.040 4.000 221.640 ;
    END
  END in_data[390]
  PIN in_data[391]
    DIRECTION INPUT ;
    USE SIGNAL ;
    ANTENNAGATEAREA 0.426000 ;
    PORT
      LAYER met2 ;
        RECT 431.570 1296.000 431.850 1300.000 ;
    END
  END in_data[391]
  PIN in_data[392]
    DIRECTION INPUT ;
    USE SIGNAL ;
    ANTENNAGATEAREA 0.426000 ;
    PORT
      LAYER met2 ;
        RECT 737.470 0.000 737.750 4.000 ;
    END
  END in_data[392]
  PIN in_data[393]
    DIRECTION INPUT ;
    USE SIGNAL ;
    ANTENNAGATEAREA 0.426000 ;
    PORT
      LAYER met2 ;
        RECT 792.210 0.000 792.490 4.000 ;
    END
  END in_data[393]
  PIN in_data[394]
    DIRECTION INPUT ;
    USE SIGNAL ;
    ANTENNAGATEAREA 0.247500 ;
    PORT
      LAYER met2 ;
        RECT 631.210 1296.000 631.490 1300.000 ;
    END
  END in_data[394]
  PIN in_data[395]
    DIRECTION INPUT ;
    USE SIGNAL ;
    ANTENNAGATEAREA 0.247500 ;
    PORT
      LAYER met2 ;
        RECT 592.570 0.000 592.850 4.000 ;
    END
  END in_data[395]
  PIN in_data[396]
    DIRECTION INPUT ;
    USE SIGNAL ;
    ANTENNAGATEAREA 0.852000 ;
    PORT
      LAYER met2 ;
        RECT 1249.450 1296.000 1249.730 1300.000 ;
    END
  END in_data[396]
  PIN in_data[397]
    DIRECTION INPUT ;
    USE SIGNAL ;
    ANTENNAGATEAREA 0.742500 ;
    PORT
      LAYER met3 ;
        RECT 1296.000 98.640 1300.000 99.240 ;
    END
  END in_data[397]
  PIN in_data[398]
    DIRECTION INPUT ;
    USE SIGNAL ;
    ANTENNAGATEAREA 0.495000 ;
    PORT
      LAYER met2 ;
        RECT 850.170 0.000 850.450 4.000 ;
    END
  END in_data[398]
  PIN in_data[399]
    DIRECTION INPUT ;
    USE SIGNAL ;
    ANTENNAGATEAREA 0.247500 ;
    PORT
      LAYER met3 ;
        RECT 0.000 608.640 4.000 609.240 ;
    END
  END in_data[399]
  PIN in_data[39]
    DIRECTION INPUT ;
    USE SIGNAL ;
    ANTENNAGATEAREA 0.495000 ;
    PORT
      LAYER met3 ;
        RECT 1296.000 513.440 1300.000 514.040 ;
    END
  END in_data[39]
  PIN in_data[3]
    DIRECTION INPUT ;
    USE SIGNAL ;
    ANTENNAGATEAREA 0.742500 ;
    PORT
      LAYER met2 ;
        RECT 29.070 0.000 29.350 4.000 ;
    END
  END in_data[3]
  PIN in_data[400]
    DIRECTION INPUT ;
    USE SIGNAL ;
    ANTENNAGATEAREA 0.495000 ;
    PORT
      LAYER met2 ;
        RECT 318.870 1296.000 319.150 1300.000 ;
    END
  END in_data[400]
  PIN in_data[401]
    DIRECTION INPUT ;
    USE SIGNAL ;
    ANTENNAGATEAREA 0.426000 ;
    PORT
      LAYER met2 ;
        RECT 788.990 1296.000 789.270 1300.000 ;
    END
  END in_data[401]
  PIN in_data[402]
    DIRECTION INPUT ;
    USE SIGNAL ;
    ANTENNAGATEAREA 0.426000 ;
    PORT
      LAYER met3 ;
        RECT 0.000 520.240 4.000 520.840 ;
    END
  END in_data[402]
  PIN in_data[403]
    DIRECTION INPUT ;
    USE SIGNAL ;
    ANTENNAGATEAREA 0.742500 ;
    PORT
      LAYER met3 ;
        RECT 1296.000 1203.640 1300.000 1204.240 ;
    END
  END in_data[403]
  PIN in_data[404]
    DIRECTION INPUT ;
    USE SIGNAL ;
    ANTENNAGATEAREA 0.426000 ;
    PORT
      LAYER met3 ;
        RECT 1296.000 826.240 1300.000 826.840 ;
    END
  END in_data[404]
  PIN in_data[405]
    DIRECTION INPUT ;
    USE SIGNAL ;
    ANTENNAGATEAREA 0.495000 ;
    PORT
      LAYER met3 ;
        RECT 1296.000 965.640 1300.000 966.240 ;
    END
  END in_data[405]
  PIN in_data[406]
    DIRECTION INPUT ;
    USE SIGNAL ;
    ANTENNAGATEAREA 0.247500 ;
    PORT
      LAYER met3 ;
        RECT 0.000 710.640 4.000 711.240 ;
    END
  END in_data[406]
  PIN in_data[407]
    DIRECTION INPUT ;
    USE SIGNAL ;
    ANTENNAGATEAREA 0.495000 ;
    PORT
      LAYER met3 ;
        RECT 0.000 343.440 4.000 344.040 ;
    END
  END in_data[407]
  PIN in_data[408]
    DIRECTION INPUT ;
    USE SIGNAL ;
    ANTENNAGATEAREA 0.426000 ;
    PORT
      LAYER met3 ;
        RECT 0.000 836.440 4.000 837.040 ;
    END
  END in_data[408]
  PIN in_data[409]
    DIRECTION INPUT ;
    USE SIGNAL ;
    ANTENNAGATEAREA 0.742500 ;
    PORT
      LAYER met2 ;
        RECT 161.090 0.000 161.370 4.000 ;
    END
  END in_data[409]
  PIN in_data[40]
    DIRECTION INPUT ;
    USE SIGNAL ;
    ANTENNAGATEAREA 0.742500 ;
    PORT
      LAYER met2 ;
        RECT 202.950 0.000 203.230 4.000 ;
    END
  END in_data[40]
  PIN in_data[410]
    DIRECTION INPUT ;
    USE SIGNAL ;
    ANTENNAGATEAREA 0.247500 ;
    PORT
      LAYER met3 ;
        RECT 0.000 676.640 4.000 677.240 ;
    END
  END in_data[410]
  PIN in_data[411]
    DIRECTION INPUT ;
    USE SIGNAL ;
    ANTENNAGATEAREA 0.426000 ;
    PORT
      LAYER met2 ;
        RECT 779.330 1296.000 779.610 1300.000 ;
    END
  END in_data[411]
  PIN in_data[412]
    DIRECTION INPUT ;
    USE SIGNAL ;
    ANTENNAGATEAREA 0.742500 ;
    PORT
      LAYER met3 ;
        RECT 1296.000 1043.840 1300.000 1044.440 ;
    END
  END in_data[412]
  PIN in_data[413]
    DIRECTION INPUT ;
    USE SIGNAL ;
    ANTENNAGATEAREA 0.495000 ;
    PORT
      LAYER met3 ;
        RECT 0.000 877.240 4.000 877.840 ;
    END
  END in_data[413]
  PIN in_data[414]
    DIRECTION INPUT ;
    USE SIGNAL ;
    ANTENNAGATEAREA 0.742500 ;
    PORT
      LAYER met3 ;
        RECT 1296.000 1224.040 1300.000 1224.640 ;
    END
  END in_data[414]
  PIN in_data[415]
    DIRECTION INPUT ;
    USE SIGNAL ;
    ANTENNAGATEAREA 0.426000 ;
    PORT
      LAYER met2 ;
        RECT 650.530 0.000 650.810 4.000 ;
    END
  END in_data[415]
  PIN in_data[416]
    DIRECTION INPUT ;
    USE SIGNAL ;
    ANTENNAGATEAREA 0.426000 ;
    PORT
      LAYER met3 ;
        RECT 1296.000 598.440 1300.000 599.040 ;
    END
  END in_data[416]
  PIN in_data[417]
    DIRECTION INPUT ;
    USE SIGNAL ;
    ANTENNAGATEAREA 0.426000 ;
    PORT
      LAYER met3 ;
        RECT 0.000 918.040 4.000 918.640 ;
    END
  END in_data[417]
  PIN in_data[418]
    DIRECTION INPUT ;
    USE SIGNAL ;
    ANTENNAGATEAREA 0.742500 ;
    PORT
      LAYER met2 ;
        RECT 87.030 0.000 87.310 4.000 ;
    END
  END in_data[418]
  PIN in_data[419]
    DIRECTION INPUT ;
    USE SIGNAL ;
    ANTENNAGATEAREA 0.742500 ;
    PORT
      LAYER met3 ;
        RECT 1296.000 1064.240 1300.000 1064.840 ;
    END
  END in_data[419]
  PIN in_data[41]
    DIRECTION INPUT ;
    USE SIGNAL ;
    ANTENNAGATEAREA 0.852000 ;
    PORT
      LAYER met3 ;
        RECT 1296.000 57.840 1300.000 58.440 ;
    END
  END in_data[41]
  PIN in_data[420]
    DIRECTION INPUT ;
    USE SIGNAL ;
    ANTENNAGATEAREA 0.742500 ;
    PORT
      LAYER met2 ;
        RECT 1094.890 1296.000 1095.170 1300.000 ;
    END
  END in_data[420]
  PIN in_data[421]
    DIRECTION INPUT ;
    USE SIGNAL ;
    ANTENNAGATEAREA 0.495000 ;
    PORT
      LAYER met3 ;
        RECT 0.000 986.040 4.000 986.640 ;
    END
  END in_data[421]
  PIN in_data[422]
    DIRECTION INPUT ;
    USE SIGNAL ;
    ANTENNAGATEAREA 0.742500 ;
    PORT
      LAYER met2 ;
        RECT 180.410 1296.000 180.690 1300.000 ;
    END
  END in_data[422]
  PIN in_data[423]
    DIRECTION INPUT ;
    USE SIGNAL ;
    ANTENNAGATEAREA 0.852000 ;
    PORT
      LAYER met2 ;
        RECT 1233.350 0.000 1233.630 4.000 ;
    END
  END in_data[423]
  PIN in_data[424]
    DIRECTION INPUT ;
    USE SIGNAL ;
    ANTENNAGATEAREA 0.852000 ;
    PORT
      LAYER met3 ;
        RECT 1296.000 91.840 1300.000 92.440 ;
    END
  END in_data[424]
  PIN in_data[425]
    DIRECTION INPUT ;
    USE SIGNAL ;
    ANTENNAGATEAREA 0.742500 ;
    PORT
      LAYER met2 ;
        RECT 972.530 0.000 972.810 4.000 ;
    END
  END in_data[425]
  PIN in_data[426]
    DIRECTION INPUT ;
    USE SIGNAL ;
    ANTENNAGATEAREA 0.495000 ;
    PORT
      LAYER met3 ;
        RECT 1296.000 533.840 1300.000 534.440 ;
    END
  END in_data[426]
  PIN in_data[427]
    DIRECTION INPUT ;
    USE SIGNAL ;
    ANTENNAGATEAREA 0.742500 ;
    PORT
      LAYER met2 ;
        RECT 93.470 1296.000 93.750 1300.000 ;
    END
  END in_data[427]
  PIN in_data[428]
    DIRECTION INPUT ;
    USE SIGNAL ;
    ANTENNAGATEAREA 0.426000 ;
    PORT
      LAYER met2 ;
        RECT 528.170 0.000 528.450 4.000 ;
    END
  END in_data[428]
  PIN in_data[429]
    DIRECTION INPUT ;
    USE SIGNAL ;
    ANTENNAGATEAREA 0.742500 ;
    PORT
      LAYER met2 ;
        RECT 1014.390 1296.000 1014.670 1300.000 ;
    END
  END in_data[429]
  PIN in_data[42]
    DIRECTION INPUT ;
    USE SIGNAL ;
    ANTENNAGATEAREA 0.247500 ;
    PORT
      LAYER met2 ;
        RECT 714.930 1296.000 715.210 1300.000 ;
    END
  END in_data[42]
  PIN in_data[430]
    DIRECTION INPUT ;
    USE SIGNAL ;
    ANTENNAGATEAREA 0.742500 ;
    PORT
      LAYER met3 ;
        RECT 1296.000 1009.840 1300.000 1010.440 ;
    END
  END in_data[430]
  PIN in_data[431]
    DIRECTION INPUT ;
    USE SIGNAL ;
    ANTENNAGATEAREA 0.742500 ;
    PORT
      LAYER met2 ;
        RECT 1053.030 1296.000 1053.310 1300.000 ;
    END
  END in_data[431]
  PIN in_data[432]
    DIRECTION INPUT ;
    USE SIGNAL ;
    ANTENNAGATEAREA 0.852000 ;
    PORT
      LAYER met3 ;
        RECT 1296.000 1298.840 1300.000 1299.440 ;
    END
  END in_data[432]
  PIN in_data[433]
    DIRECTION INPUT ;
    USE SIGNAL ;
    ANTENNAGATEAREA 0.742500 ;
    PORT
      LAYER met3 ;
        RECT 0.000 1227.440 4.000 1228.040 ;
    END
  END in_data[433]
  PIN in_data[434]
    DIRECTION INPUT ;
    USE SIGNAL ;
    ANTENNAGATEAREA 0.426000 ;
    PORT
      LAYER met2 ;
        RECT 457.330 0.000 457.610 4.000 ;
    END
  END in_data[434]
  PIN in_data[435]
    DIRECTION INPUT ;
    USE SIGNAL ;
    ANTENNAGATEAREA 0.742500 ;
    PORT
      LAYER met3 ;
        RECT 0.000 34.040 4.000 34.640 ;
    END
  END in_data[435]
  PIN in_data[436]
    DIRECTION INPUT ;
    USE SIGNAL ;
    ANTENNAGATEAREA 0.426000 ;
    PORT
      LAYER met2 ;
        RECT 434.790 1296.000 435.070 1300.000 ;
    END
  END in_data[436]
  PIN in_data[437]
    DIRECTION INPUT ;
    USE SIGNAL ;
    ANTENNAGATEAREA 0.495000 ;
    PORT
      LAYER met3 ;
        RECT 0.000 1132.240 4.000 1132.840 ;
    END
  END in_data[437]
  PIN in_data[438]
    DIRECTION INPUT ;
    USE SIGNAL ;
    ANTENNAGATEAREA 0.247500 ;
    PORT
      LAYER met2 ;
        RECT 602.230 1296.000 602.510 1300.000 ;
    END
  END in_data[438]
  PIN in_data[439]
    DIRECTION INPUT ;
    USE SIGNAL ;
    ANTENNAGATEAREA 0.495000 ;
    PORT
      LAYER met2 ;
        RECT 334.970 0.000 335.250 4.000 ;
    END
  END in_data[439]
  PIN in_data[43]
    DIRECTION INPUT ;
    USE SIGNAL ;
    ANTENNAGATEAREA 0.742500 ;
    PORT
      LAYER met3 ;
        RECT 0.000 193.840 4.000 194.440 ;
    END
  END in_data[43]
  PIN in_data[440]
    DIRECTION INPUT ;
    USE SIGNAL ;
    ANTENNAGATEAREA 0.495000 ;
    PORT
      LAYER met3 ;
        RECT 0.000 442.040 4.000 442.640 ;
    END
  END in_data[440]
  PIN in_data[441]
    DIRECTION INPUT ;
    USE SIGNAL ;
    ANTENNAGATEAREA 0.852000 ;
    PORT
      LAYER met3 ;
        RECT 1296.000 61.240 1300.000 61.840 ;
    END
  END in_data[441]
  PIN in_data[442]
    DIRECTION INPUT ;
    USE SIGNAL ;
    ANTENNAGATEAREA 0.426000 ;
    PORT
      LAYER met2 ;
        RECT 380.050 1296.000 380.330 1300.000 ;
    END
  END in_data[442]
  PIN in_data[443]
    DIRECTION INPUT ;
    USE SIGNAL ;
    ANTENNAGATEAREA 0.495000 ;
    PORT
      LAYER met2 ;
        RECT 322.090 1296.000 322.370 1300.000 ;
    END
  END in_data[443]
  PIN in_data[444]
    DIRECTION INPUT ;
    USE SIGNAL ;
    ANTENNAGATEAREA 0.247500 ;
    PORT
      LAYER met2 ;
        RECT 605.450 1296.000 605.730 1300.000 ;
    END
  END in_data[444]
  PIN in_data[445]
    DIRECTION INPUT ;
    USE SIGNAL ;
    ANTENNAGATEAREA 0.247500 ;
    PORT
      LAYER met2 ;
        RECT 553.930 1296.000 554.210 1300.000 ;
    END
  END in_data[445]
  PIN in_data[446]
    DIRECTION INPUT ;
    USE SIGNAL ;
    ANTENNAGATEAREA 0.426000 ;
    PORT
      LAYER met3 ;
        RECT 1296.000 656.240 1300.000 656.840 ;
    END
  END in_data[446]
  PIN in_data[447]
    DIRECTION INPUT ;
    USE SIGNAL ;
    ANTENNAGATEAREA 0.495000 ;
    PORT
      LAYER met2 ;
        RECT 367.170 0.000 367.450 4.000 ;
    END
  END in_data[447]
  PIN in_data[448]
    DIRECTION INPUT ;
    USE SIGNAL ;
    ANTENNAGATEAREA 0.495000 ;
    PORT
      LAYER met2 ;
        RECT 869.490 1296.000 869.770 1300.000 ;
    END
  END in_data[448]
  PIN in_data[449]
    DIRECTION INPUT ;
    USE SIGNAL ;
    ANTENNAGATEAREA 0.426000 ;
    PORT
      LAYER met2 ;
        RECT 502.410 0.000 502.690 4.000 ;
    END
  END in_data[449]
  PIN in_data[44]
    DIRECTION INPUT ;
    USE SIGNAL ;
    ANTENNAGATEAREA 0.742500 ;
    PORT
      LAYER met3 ;
        RECT 0.000 438.640 4.000 439.240 ;
    END
  END in_data[44]
  PIN in_data[450]
    DIRECTION INPUT ;
    USE SIGNAL ;
    ANTENNAGATEAREA 0.742500 ;
    PORT
      LAYER met3 ;
        RECT 1296.000 217.640 1300.000 218.240 ;
    END
  END in_data[450]
  PIN in_data[451]
    DIRECTION INPUT ;
    USE SIGNAL ;
    ANTENNAGATEAREA 0.495000 ;
    PORT
      LAYER met2 ;
        RECT 930.670 1296.000 930.950 1300.000 ;
    END
  END in_data[451]
  PIN in_data[452]
    DIRECTION INPUT ;
    USE SIGNAL ;
    ANTENNAGATEAREA 0.742500 ;
    PORT
      LAYER met3 ;
        RECT 0.000 1203.640 4.000 1204.240 ;
    END
  END in_data[452]
  PIN in_data[453]
    DIRECTION INPUT ;
    USE SIGNAL ;
    ANTENNAGATEAREA 0.426000 ;
    PORT
      LAYER met2 ;
        RECT 547.490 0.000 547.770 4.000 ;
    END
  END in_data[453]
  PIN in_data[454]
    DIRECTION INPUT ;
    USE SIGNAL ;
    ANTENNAGATEAREA 0.742500 ;
    PORT
      LAYER met3 ;
        RECT 0.000 1115.240 4.000 1115.840 ;
    END
  END in_data[454]
  PIN in_data[455]
    DIRECTION INPUT ;
    USE SIGNAL ;
    ANTENNAGATEAREA 0.742500 ;
    PORT
      LAYER met3 ;
        RECT 0.000 1217.240 4.000 1217.840 ;
    END
  END in_data[455]
  PIN in_data[456]
    DIRECTION INPUT ;
    USE SIGNAL ;
    ANTENNAGATEAREA 0.742500 ;
    PORT
      LAYER met3 ;
        RECT 1296.000 999.640 1300.000 1000.240 ;
    END
  END in_data[456]
  PIN in_data[457]
    DIRECTION INPUT ;
    USE SIGNAL ;
    ANTENNAGATEAREA 0.426000 ;
    PORT
      LAYER met2 ;
        RECT 660.190 0.000 660.470 4.000 ;
    END
  END in_data[457]
  PIN in_data[458]
    DIRECTION INPUT ;
    USE SIGNAL ;
    ANTENNAGATEAREA 0.247500 ;
    PORT
      LAYER met3 ;
        RECT 0.000 578.040 4.000 578.640 ;
    END
  END in_data[458]
  PIN in_data[459]
    DIRECTION INPUT ;
    USE SIGNAL ;
    ANTENNAGATEAREA 0.742500 ;
    PORT
      LAYER met2 ;
        RECT 1065.910 0.000 1066.190 4.000 ;
    END
  END in_data[459]
  PIN in_data[45]
    DIRECTION INPUT ;
    USE SIGNAL ;
    ANTENNAGATEAREA 0.426000 ;
    PORT
      LAYER met2 ;
        RECT 425.130 1296.000 425.410 1300.000 ;
    END
  END in_data[45]
  PIN in_data[460]
    DIRECTION INPUT ;
    USE SIGNAL ;
    ANTENNAGATEAREA 0.742500 ;
    PORT
      LAYER met2 ;
        RECT 38.730 1296.000 39.010 1300.000 ;
    END
  END in_data[460]
  PIN in_data[461]
    DIRECTION INPUT ;
    USE SIGNAL ;
    ANTENNAGATEAREA 0.426000 ;
    PORT
      LAYER met3 ;
        RECT 0.000 805.840 4.000 806.440 ;
    END
  END in_data[461]
  PIN in_data[462]
    DIRECTION INPUT ;
    USE SIGNAL ;
    ANTENNAGATEAREA 0.742500 ;
    PORT
      LAYER met3 ;
        RECT 1296.000 227.840 1300.000 228.440 ;
    END
  END in_data[462]
  PIN in_data[463]
    DIRECTION INPUT ;
    USE SIGNAL ;
    ANTENNAGATEAREA 0.742500 ;
    PORT
      LAYER met3 ;
        RECT 0.000 64.640 4.000 65.240 ;
    END
  END in_data[463]
  PIN in_data[464]
    DIRECTION INPUT ;
    USE SIGNAL ;
    ANTENNAGATEAREA 0.247500 ;
    PORT
      LAYER met2 ;
        RECT 582.910 1296.000 583.190 1300.000 ;
    END
  END in_data[464]
  PIN in_data[465]
    DIRECTION INPUT ;
    USE SIGNAL ;
    ANTENNAGATEAREA 0.742500 ;
    PORT
      LAYER met2 ;
        RECT 949.990 1296.000 950.270 1300.000 ;
    END
  END in_data[465]
  PIN in_data[466]
    DIRECTION INPUT ;
    USE SIGNAL ;
    ANTENNAGATEAREA 0.742500 ;
    PORT
      LAYER met2 ;
        RECT 1139.970 0.000 1140.250 4.000 ;
    END
  END in_data[466]
  PIN in_data[467]
    DIRECTION INPUT ;
    USE SIGNAL ;
    ANTENNAGATEAREA 0.247500 ;
    PORT
      LAYER met3 ;
        RECT 0.000 737.840 4.000 738.440 ;
    END
  END in_data[467]
  PIN in_data[468]
    DIRECTION INPUT ;
    USE SIGNAL ;
    ANTENNAGATEAREA 0.247500 ;
    PORT
      LAYER met2 ;
        RECT 531.390 1296.000 531.670 1300.000 ;
    END
  END in_data[468]
  PIN in_data[469]
    DIRECTION INPUT ;
    USE SIGNAL ;
    ANTENNAGATEAREA 0.426000 ;
    PORT
      LAYER met2 ;
        RECT 409.030 0.000 409.310 4.000 ;
    END
  END in_data[469]
  PIN in_data[46]
    DIRECTION INPUT ;
    USE SIGNAL ;
    ANTENNAGATEAREA 0.852000 ;
    PORT
      LAYER met2 ;
        RECT 106.350 0.000 106.630 4.000 ;
    END
  END in_data[46]
  PIN in_data[470]
    DIRECTION INPUT ;
    USE SIGNAL ;
    ANTENNAGATEAREA 0.426000 ;
    PORT
      LAYER met2 ;
        RECT 473.430 1296.000 473.710 1300.000 ;
    END
  END in_data[470]
  PIN in_data[471]
    DIRECTION INPUT ;
    USE SIGNAL ;
    ANTENNAGATEAREA 0.742500 ;
    PORT
      LAYER met2 ;
        RECT 180.410 0.000 180.690 4.000 ;
    END
  END in_data[471]
  PIN in_data[472]
    DIRECTION INPUT ;
    USE SIGNAL ;
    ANTENNAGATEAREA 0.426000 ;
    PORT
      LAYER met2 ;
        RECT 656.970 1296.000 657.250 1300.000 ;
    END
  END in_data[472]
  PIN in_data[473]
    DIRECTION INPUT ;
    USE SIGNAL ;
    ANTENNAGATEAREA 0.852000 ;
    PORT
      LAYER met3 ;
        RECT 1296.000 37.440 1300.000 38.040 ;
    END
  END in_data[473]
  PIN in_data[474]
    DIRECTION INPUT ;
    USE SIGNAL ;
    ANTENNAGATEAREA 0.742500 ;
    PORT
      LAYER met3 ;
        RECT 0.000 173.440 4.000 174.040 ;
    END
  END in_data[474]
  PIN in_data[475]
    DIRECTION INPUT ;
    USE SIGNAL ;
    ANTENNAGATEAREA 0.426000 ;
    PORT
      LAYER met2 ;
        RECT 463.770 0.000 464.050 4.000 ;
    END
  END in_data[475]
  PIN in_data[476]
    DIRECTION INPUT ;
    USE SIGNAL ;
    ANTENNAGATEAREA 0.247500 ;
    PORT
      LAYER met2 ;
        RECT 586.130 0.000 586.410 4.000 ;
    END
  END in_data[476]
  PIN in_data[477]
    DIRECTION INPUT ;
    USE SIGNAL ;
    ANTENNAGATEAREA 0.495000 ;
    PORT
      LAYER met3 ;
        RECT 1296.000 387.640 1300.000 388.240 ;
    END
  END in_data[477]
  PIN in_data[478]
    DIRECTION INPUT ;
    USE SIGNAL ;
    ANTENNAGATEAREA 0.742500 ;
    PORT
      LAYER met3 ;
        RECT 0.000 30.640 4.000 31.240 ;
    END
  END in_data[478]
  PIN in_data[479]
    DIRECTION INPUT ;
    USE SIGNAL ;
    ANTENNAGATEAREA 0.852000 ;
    PORT
      LAYER met2 ;
        RECT 1178.610 1296.000 1178.890 1300.000 ;
    END
  END in_data[479]
  PIN in_data[47]
    DIRECTION INPUT ;
    USE SIGNAL ;
    ANTENNAGATEAREA 0.247500 ;
    PORT
      LAYER met2 ;
        RECT 512.070 1296.000 512.350 1300.000 ;
    END
  END in_data[47]
  PIN in_data[480]
    DIRECTION INPUT ;
    USE SIGNAL ;
    ANTENNAGATEAREA 0.495000 ;
    PORT
      LAYER met2 ;
        RECT 273.790 0.000 274.070 4.000 ;
    END
  END in_data[480]
  PIN in_data[481]
    DIRECTION INPUT ;
    USE SIGNAL ;
    ANTENNAGATEAREA 0.742500 ;
    PORT
      LAYER met2 ;
        RECT 1172.170 0.000 1172.450 4.000 ;
    END
  END in_data[481]
  PIN in_data[482]
    DIRECTION INPUT ;
    USE SIGNAL ;
    ANTENNAGATEAREA 0.426000 ;
    PORT
      LAYER met2 ;
        RECT 785.770 0.000 786.050 4.000 ;
    END
  END in_data[482]
  PIN in_data[483]
    DIRECTION INPUT ;
    USE SIGNAL ;
    ANTENNAGATEAREA 0.247500 ;
    PORT
      LAYER met3 ;
        RECT 0.000 571.240 4.000 571.840 ;
    END
  END in_data[483]
  PIN in_data[484]
    DIRECTION INPUT ;
    USE SIGNAL ;
    ANTENNAGATEAREA 0.742500 ;
    PORT
      LAYER met3 ;
        RECT 0.000 132.640 4.000 133.240 ;
    END
  END in_data[484]
  PIN in_data[485]
    DIRECTION INPUT ;
    USE SIGNAL ;
    ANTENNAGATEAREA 0.742500 ;
    PORT
      LAYER met2 ;
        RECT 80.590 0.000 80.870 4.000 ;
    END
  END in_data[485]
  PIN in_data[486]
    DIRECTION INPUT ;
    USE SIGNAL ;
    ANTENNAGATEAREA 0.495000 ;
    PORT
      LAYER met2 ;
        RECT 238.370 1296.000 238.650 1300.000 ;
    END
  END in_data[486]
  PIN in_data[487]
    DIRECTION INPUT ;
    USE SIGNAL ;
    ANTENNAGATEAREA 0.247500 ;
    PORT
      LAYER met2 ;
        RECT 550.710 0.000 550.990 4.000 ;
    END
  END in_data[487]
  PIN in_data[488]
    DIRECTION INPUT ;
    USE SIGNAL ;
    ANTENNAGATEAREA 0.426000 ;
    PORT
      LAYER met2 ;
        RECT 492.750 1296.000 493.030 1300.000 ;
    END
  END in_data[488]
  PIN in_data[489]
    DIRECTION INPUT ;
    USE SIGNAL ;
    ANTENNAGATEAREA 0.426000 ;
    PORT
      LAYER met3 ;
        RECT 1296.000 652.840 1300.000 653.440 ;
    END
  END in_data[489]
  PIN in_data[48]
    DIRECTION INPUT ;
    USE SIGNAL ;
    ANTENNAGATEAREA 0.426000 ;
    PORT
      LAYER met2 ;
        RECT 689.170 1296.000 689.450 1300.000 ;
    END
  END in_data[48]
  PIN in_data[490]
    DIRECTION INPUT ;
    USE SIGNAL ;
    ANTENNAGATEAREA 0.426000 ;
    PORT
      LAYER met3 ;
        RECT 1296.000 608.640 1300.000 609.240 ;
    END
  END in_data[490]
  PIN in_data[491]
    DIRECTION INPUT ;
    USE SIGNAL ;
    ANTENNAGATEAREA 0.742500 ;
    PORT
      LAYER met3 ;
        RECT 0.000 1152.640 4.000 1153.240 ;
    END
  END in_data[491]
  PIN in_data[492]
    DIRECTION INPUT ;
    USE SIGNAL ;
    ANTENNAGATEAREA 0.742500 ;
    PORT
      LAYER met3 ;
        RECT 0.000 1047.240 4.000 1047.840 ;
    END
  END in_data[492]
  PIN in_data[493]
    DIRECTION INPUT ;
    USE SIGNAL ;
    ANTENNAGATEAREA 0.742500 ;
    PORT
      LAYER met2 ;
        RECT 3.310 1296.000 3.590 1300.000 ;
    END
  END in_data[493]
  PIN in_data[494]
    DIRECTION INPUT ;
    USE SIGNAL ;
    ANTENNAGATEAREA 0.852000 ;
    PORT
      LAYER met3 ;
        RECT 1296.000 1261.440 1300.000 1262.040 ;
    END
  END in_data[494]
  PIN in_data[495]
    DIRECTION INPUT ;
    USE SIGNAL ;
    ANTENNAGATEAREA 0.742500 ;
    PORT
      LAYER met2 ;
        RECT 1049.810 0.000 1050.090 4.000 ;
    END
  END in_data[495]
  PIN in_data[496]
    DIRECTION INPUT ;
    USE SIGNAL ;
    ANTENNAGATEAREA 0.247500 ;
    PORT
      LAYER met2 ;
        RECT 576.470 1296.000 576.750 1300.000 ;
    END
  END in_data[496]
  PIN in_data[497]
    DIRECTION INPUT ;
    USE SIGNAL ;
    ANTENNAGATEAREA 0.742500 ;
    PORT
      LAYER met2 ;
        RECT 77.370 0.000 77.650 4.000 ;
    END
  END in_data[497]
  PIN in_data[498]
    DIRECTION INPUT ;
    USE SIGNAL ;
    ANTENNAGATEAREA 0.742500 ;
    PORT
      LAYER met3 ;
        RECT 1296.000 244.840 1300.000 245.440 ;
    END
  END in_data[498]
  PIN in_data[499]
    DIRECTION INPUT ;
    USE SIGNAL ;
    ANTENNAGATEAREA 0.852000 ;
    PORT
      LAYER met3 ;
        RECT 1296.000 20.440 1300.000 21.040 ;
    END
  END in_data[499]
  PIN in_data[49]
    DIRECTION INPUT ;
    USE SIGNAL ;
    ANTENNAGATEAREA 0.495000 ;
    PORT
      LAYER met3 ;
        RECT 0.000 506.640 4.000 507.240 ;
    END
  END in_data[49]
  PIN in_data[4]
    DIRECTION INPUT ;
    USE SIGNAL ;
    ANTENNAGATEAREA 0.742500 ;
    PORT
      LAYER met2 ;
        RECT 212.610 0.000 212.890 4.000 ;
    END
  END in_data[4]
  PIN in_data[500]
    DIRECTION INPUT ;
    USE SIGNAL ;
    ANTENNAGATEAREA 0.852000 ;
    PORT
      LAYER met3 ;
        RECT 1296.000 30.640 1300.000 31.240 ;
    END
  END in_data[500]
  PIN in_data[501]
    DIRECTION INPUT ;
    USE SIGNAL ;
    ANTENNAGATEAREA 0.426000 ;
    PORT
      LAYER met3 ;
        RECT 0.000 765.040 4.000 765.640 ;
    END
  END in_data[501]
  PIN in_data[502]
    DIRECTION INPUT ;
    USE SIGNAL ;
    ANTENNAGATEAREA 0.742500 ;
    PORT
      LAYER met2 ;
        RECT 1091.670 1296.000 1091.950 1300.000 ;
    END
  END in_data[502]
  PIN in_data[503]
    DIRECTION INPUT ;
    USE SIGNAL ;
    ANTENNAGATEAREA 0.852000 ;
    PORT
      LAYER met3 ;
        RECT 0.000 54.440 4.000 55.040 ;
    END
  END in_data[503]
  PIN in_data[504]
    DIRECTION INPUT ;
    USE SIGNAL ;
    ANTENNAGATEAREA 0.426000 ;
    PORT
      LAYER met2 ;
        RECT 763.230 1296.000 763.510 1300.000 ;
    END
  END in_data[504]
  PIN in_data[505]
    DIRECTION INPUT ;
    USE SIGNAL ;
    ANTENNAGATEAREA 0.426000 ;
    PORT
      LAYER met3 ;
        RECT 1296.000 805.840 1300.000 806.440 ;
    END
  END in_data[505]
  PIN in_data[506]
    DIRECTION INPUT ;
    USE SIGNAL ;
    ANTENNAGATEAREA 0.742500 ;
    PORT
      LAYER met2 ;
        RECT 1104.550 1296.000 1104.830 1300.000 ;
    END
  END in_data[506]
  PIN in_data[507]
    DIRECTION INPUT ;
    USE SIGNAL ;
    ANTENNAGATEAREA 0.495000 ;
    PORT
      LAYER met2 ;
        RECT 367.170 1296.000 367.450 1300.000 ;
    END
  END in_data[507]
  PIN in_data[508]
    DIRECTION INPUT ;
    USE SIGNAL ;
    ANTENNAGATEAREA 0.742500 ;
    PORT
      LAYER met2 ;
        RECT 151.430 1296.000 151.710 1300.000 ;
    END
  END in_data[508]
  PIN in_data[509]
    DIRECTION INPUT ;
    USE SIGNAL ;
    ANTENNAGATEAREA 0.742500 ;
    PORT
      LAYER met3 ;
        RECT 1296.000 360.440 1300.000 361.040 ;
    END
  END in_data[509]
  PIN in_data[50]
    DIRECTION INPUT ;
    USE SIGNAL ;
    ANTENNAGATEAREA 0.426000 ;
    PORT
      LAYER met3 ;
        RECT 0.000 989.440 4.000 990.040 ;
    END
  END in_data[50]
  PIN in_data[510]
    DIRECTION INPUT ;
    USE SIGNAL ;
    ANTENNAGATEAREA 0.742500 ;
    PORT
      LAYER met3 ;
        RECT 1296.000 238.040 1300.000 238.640 ;
    END
  END in_data[510]
  PIN in_data[511]
    DIRECTION INPUT ;
    USE SIGNAL ;
    ANTENNAGATEAREA 0.426000 ;
    PORT
      LAYER met2 ;
        RECT 521.730 1296.000 522.010 1300.000 ;
    END
  END in_data[511]
  PIN in_data[512]
    DIRECTION INPUT ;
    USE SIGNAL ;
    ANTENNAGATEAREA 0.247500 ;
    PORT
      LAYER met3 ;
        RECT 1296.000 615.440 1300.000 616.040 ;
    END
  END in_data[512]
  PIN in_data[513]
    DIRECTION INPUT ;
    USE SIGNAL ;
    ANTENNAGATEAREA 0.495000 ;
    PORT
      LAYER met3 ;
        RECT 1296.000 190.440 1300.000 191.040 ;
    END
  END in_data[513]
  PIN in_data[514]
    DIRECTION INPUT ;
    USE SIGNAL ;
    ANTENNAGATEAREA 0.990000 ;
    PORT
      LAYER met2 ;
        RECT 1188.270 0.000 1188.550 4.000 ;
    END
  END in_data[514]
  PIN in_data[515]
    DIRECTION INPUT ;
    USE SIGNAL ;
    ANTENNAGATEAREA 0.990000 ;
    PORT
      LAYER met2 ;
        RECT 9.750 0.000 10.030 4.000 ;
    END
  END in_data[515]
  PIN in_data[516]
    DIRECTION INPUT ;
    USE SIGNAL ;
    ANTENNAGATEAREA 0.742500 ;
    PORT
      LAYER met3 ;
        RECT 0.000 680.040 4.000 680.640 ;
    END
  END in_data[516]
  PIN in_data[517]
    DIRECTION INPUT ;
    USE SIGNAL ;
    ANTENNAGATEAREA 0.990000 ;
    PORT
      LAYER met2 ;
        RECT 190.070 0.000 190.350 4.000 ;
    END
  END in_data[517]
  PIN in_data[518]
    DIRECTION INPUT ;
    USE SIGNAL ;
    ANTENNAGATEAREA 0.495000 ;
    PORT
      LAYER met3 ;
        RECT 1296.000 931.640 1300.000 932.240 ;
    END
  END in_data[518]
  PIN in_data[519]
    DIRECTION INPUT ;
    USE SIGNAL ;
    ANTENNAGATEAREA 0.742500 ;
    PORT
      LAYER met3 ;
        RECT 0.000 319.640 4.000 320.240 ;
    END
  END in_data[519]
  PIN in_data[51]
    DIRECTION INPUT ;
    USE SIGNAL ;
    ANTENNAGATEAREA 0.742500 ;
    PORT
      LAYER met2 ;
        RECT 106.350 1296.000 106.630 1300.000 ;
    END
  END in_data[51]
  PIN in_data[520]
    DIRECTION INPUT ;
    USE SIGNAL ;
    ANTENNAGATEAREA 0.426000 ;
    PORT
      LAYER met2 ;
        RECT 615.110 0.000 615.390 4.000 ;
    END
  END in_data[520]
  PIN in_data[521]
    DIRECTION INPUT ;
    USE SIGNAL ;
    ANTENNAGATEAREA 0.426000 ;
    PORT
      LAYER met3 ;
        RECT 1296.000 686.840 1300.000 687.440 ;
    END
  END in_data[521]
  PIN in_data[522]
    DIRECTION INPUT ;
    USE SIGNAL ;
    ANTENNAGATEAREA 0.852000 ;
    PORT
      LAYER met2 ;
        RECT 67.710 1296.000 67.990 1300.000 ;
    END
  END in_data[522]
  PIN in_data[523]
    DIRECTION INPUT ;
    USE SIGNAL ;
    ANTENNAGATEAREA 0.495000 ;
    PORT
      LAYER met3 ;
        RECT 0.000 482.840 4.000 483.440 ;
    END
  END in_data[523]
  PIN in_data[524]
    DIRECTION INPUT ;
    USE SIGNAL ;
    ANTENNAGATEAREA 0.247500 ;
    PORT
      LAYER met2 ;
        RECT 718.150 0.000 718.430 4.000 ;
    END
  END in_data[524]
  PIN in_data[525]
    DIRECTION INPUT ;
    USE SIGNAL ;
    ANTENNAGATEAREA 0.742500 ;
    PORT
      LAYER met3 ;
        RECT 0.000 91.840 4.000 92.440 ;
    END
  END in_data[525]
  PIN in_data[526]
    DIRECTION INPUT ;
    USE SIGNAL ;
    ANTENNAGATEAREA 0.852000 ;
    PORT
      LAYER met2 ;
        RECT 122.450 1296.000 122.730 1300.000 ;
    END
  END in_data[526]
  PIN in_data[527]
    DIRECTION INPUT ;
    USE SIGNAL ;
    ANTENNAGATEAREA 0.852000 ;
    PORT
      LAYER met3 ;
        RECT 0.000 1244.440 4.000 1245.040 ;
    END
  END in_data[527]
  PIN in_data[528]
    DIRECTION INPUT ;
    USE SIGNAL ;
    ANTENNAGATEAREA 0.426000 ;
    PORT
      LAYER met3 ;
        RECT 1296.000 455.640 1300.000 456.240 ;
    END
  END in_data[528]
  PIN in_data[529]
    DIRECTION INPUT ;
    USE SIGNAL ;
    ANTENNAGATEAREA 0.426000 ;
    PORT
      LAYER met3 ;
        RECT 1296.000 438.640 1300.000 439.240 ;
    END
  END in_data[529]
  PIN in_data[52]
    DIRECTION INPUT ;
    USE SIGNAL ;
    ANTENNAGATEAREA 0.742500 ;
    PORT
      LAYER met2 ;
        RECT 331.750 0.000 332.030 4.000 ;
    END
  END in_data[52]
  PIN in_data[530]
    DIRECTION INPUT ;
    USE SIGNAL ;
    ANTENNAGATEAREA 0.426000 ;
    PORT
      LAYER met3 ;
        RECT 1296.000 435.240 1300.000 435.840 ;
    END
  END in_data[530]
  PIN in_data[531]
    DIRECTION INPUT ;
    USE SIGNAL ;
    ANTENNAGATEAREA 0.426000 ;
    PORT
      LAYER met3 ;
        RECT 1296.000 833.040 1300.000 833.640 ;
    END
  END in_data[531]
  PIN in_data[532]
    DIRECTION INPUT ;
    USE SIGNAL ;
    ANTENNAGATEAREA 0.495000 ;
    PORT
      LAYER met2 ;
        RECT 959.650 1296.000 959.930 1300.000 ;
    END
  END in_data[532]
  PIN in_data[533]
    DIRECTION INPUT ;
    USE SIGNAL ;
    ANTENNAGATEAREA 0.426000 ;
    PORT
      LAYER met3 ;
        RECT 0.000 649.440 4.000 650.040 ;
    END
  END in_data[533]
  PIN in_data[534]
    DIRECTION INPUT ;
    USE SIGNAL ;
    ANTENNAGATEAREA 0.495000 ;
    PORT
      LAYER met3 ;
        RECT 1296.000 921.440 1300.000 922.040 ;
    END
  END in_data[534]
  PIN in_data[535]
    DIRECTION INPUT ;
    USE SIGNAL ;
    ANTENNAGATEAREA 0.247500 ;
    PORT
      LAYER met2 ;
        RECT 734.250 0.000 734.530 4.000 ;
    END
  END in_data[535]
  PIN in_data[536]
    DIRECTION INPUT ;
    USE SIGNAL ;
    ANTENNAGATEAREA 0.495000 ;
    PORT
      LAYER met2 ;
        RECT 502.410 1296.000 502.690 1300.000 ;
    END
  END in_data[536]
  PIN in_data[537]
    DIRECTION INPUT ;
    USE SIGNAL ;
    ANTENNAGATEAREA 0.247500 ;
    PORT
      LAYER met2 ;
        RECT 631.210 0.000 631.490 4.000 ;
    END
  END in_data[537]
  PIN in_data[538]
    DIRECTION INPUT ;
    USE SIGNAL ;
    ANTENNAGATEAREA 0.495000 ;
    PORT
      LAYER met2 ;
        RECT 344.630 0.000 344.910 4.000 ;
    END
  END in_data[538]
  PIN in_data[539]
    DIRECTION INPUT ;
    USE SIGNAL ;
    ANTENNAGATEAREA 0.742500 ;
    PORT
      LAYER met3 ;
        RECT 0.000 149.640 4.000 150.240 ;
    END
  END in_data[539]
  PIN in_data[53]
    DIRECTION INPUT ;
    USE SIGNAL ;
    ANTENNAGATEAREA 0.742500 ;
    PORT
      LAYER met3 ;
        RECT 1296.000 1247.840 1300.000 1248.440 ;
    END
  END in_data[53]
  PIN in_data[540]
    DIRECTION INPUT ;
    USE SIGNAL ;
    ANTENNAGATEAREA 0.495000 ;
    PORT
      LAYER met2 ;
        RECT 978.970 1296.000 979.250 1300.000 ;
    END
  END in_data[540]
  PIN in_data[541]
    DIRECTION INPUT ;
    USE SIGNAL ;
    ANTENNAGATEAREA 0.495000 ;
    PORT
      LAYER met3 ;
        RECT 1296.000 258.440 1300.000 259.040 ;
    END
  END in_data[541]
  PIN in_data[542]
    DIRECTION INPUT ;
    USE SIGNAL ;
    ANTENNAGATEAREA 0.426000 ;
    PORT
      LAYER met2 ;
        RECT 892.030 1296.000 892.310 1300.000 ;
    END
  END in_data[542]
  PIN in_data[543]
    DIRECTION INPUT ;
    USE SIGNAL ;
    ANTENNAGATEAREA 0.742500 ;
    PORT
      LAYER met2 ;
        RECT 244.810 0.000 245.090 4.000 ;
    END
  END in_data[543]
  PIN in_data[544]
    DIRECTION INPUT ;
    USE SIGNAL ;
    ANTENNAGATEAREA 0.742500 ;
    PORT
      LAYER met2 ;
        RECT 173.970 0.000 174.250 4.000 ;
    END
  END in_data[544]
  PIN in_data[545]
    DIRECTION INPUT ;
    USE SIGNAL ;
    ANTENNAGATEAREA 0.742500 ;
    PORT
      LAYER met3 ;
        RECT 1296.000 149.640 1300.000 150.240 ;
    END
  END in_data[545]
  PIN in_data[546]
    DIRECTION INPUT ;
    USE SIGNAL ;
    ANTENNAGATEAREA 0.742500 ;
    PORT
      LAYER met3 ;
        RECT 1296.000 1122.040 1300.000 1122.640 ;
    END
  END in_data[546]
  PIN in_data[547]
    DIRECTION INPUT ;
    USE SIGNAL ;
    ANTENNAGATEAREA 0.495000 ;
    PORT
      LAYER met2 ;
        RECT 557.150 1296.000 557.430 1300.000 ;
    END
  END in_data[547]
  PIN in_data[548]
    DIRECTION INPUT ;
    USE SIGNAL ;
    ANTENNAGATEAREA 0.742500 ;
    PORT
      LAYER met3 ;
        RECT 0.000 996.240 4.000 996.840 ;
    END
  END in_data[548]
  PIN in_data[549]
    DIRECTION INPUT ;
    USE SIGNAL ;
    ANTENNAGATEAREA 0.495000 ;
    PORT
      LAYER met3 ;
        RECT 0.000 489.640 4.000 490.240 ;
    END
  END in_data[549]
  PIN in_data[54]
    DIRECTION INPUT ;
    USE SIGNAL ;
    ANTENNAGATEAREA 0.742500 ;
    PORT
      LAYER met2 ;
        RECT 1007.950 0.000 1008.230 4.000 ;
    END
  END in_data[54]
  PIN in_data[550]
    DIRECTION INPUT ;
    USE SIGNAL ;
    ANTENNAGATEAREA 0.742500 ;
    PORT
      LAYER met3 ;
        RECT 1296.000 136.040 1300.000 136.640 ;
    END
  END in_data[550]
  PIN in_data[551]
    DIRECTION INPUT ;
    USE SIGNAL ;
    ANTENNAGATEAREA 0.426000 ;
    PORT
      LAYER met2 ;
        RECT 885.590 1296.000 885.870 1300.000 ;
    END
  END in_data[551]
  PIN in_data[552]
    DIRECTION INPUT ;
    USE SIGNAL ;
    ANTENNAGATEAREA 0.742500 ;
    PORT
      LAYER met3 ;
        RECT 0.000 258.440 4.000 259.040 ;
    END
  END in_data[552]
  PIN in_data[553]
    DIRECTION INPUT ;
    USE SIGNAL ;
    ANTENNAGATEAREA 0.742500 ;
    PORT
      LAYER met2 ;
        RECT 1252.670 0.000 1252.950 4.000 ;
    END
  END in_data[553]
  PIN in_data[554]
    DIRECTION INPUT ;
    USE SIGNAL ;
    ANTENNAGATEAREA 0.852000 ;
    PORT
      LAYER met2 ;
        RECT 96.690 1296.000 96.970 1300.000 ;
    END
  END in_data[554]
  PIN in_data[555]
    DIRECTION INPUT ;
    USE SIGNAL ;
    ANTENNAGATEAREA 0.426000 ;
    PORT
      LAYER met2 ;
        RECT 792.210 1296.000 792.490 1300.000 ;
    END
  END in_data[555]
  PIN in_data[556]
    DIRECTION INPUT ;
    USE SIGNAL ;
    ANTENNAGATEAREA 0.426000 ;
    PORT
      LAYER met3 ;
        RECT 0.000 629.040 4.000 629.640 ;
    END
  END in_data[556]
  PIN in_data[557]
    DIRECTION INPUT ;
    USE SIGNAL ;
    ANTENNAGATEAREA 0.495000 ;
    PORT
      LAYER met3 ;
        RECT 0.000 717.440 4.000 718.040 ;
    END
  END in_data[557]
  PIN in_data[558]
    DIRECTION INPUT ;
    USE SIGNAL ;
    ANTENNAGATEAREA 0.742500 ;
    PORT
      LAYER met2 ;
        RECT 228.710 1296.000 228.990 1300.000 ;
    END
  END in_data[558]
  PIN in_data[559]
    DIRECTION INPUT ;
    USE SIGNAL ;
    ANTENNAGATEAREA 0.426000 ;
    PORT
      LAYER met2 ;
        RECT 795.430 0.000 795.710 4.000 ;
    END
  END in_data[559]
  PIN in_data[55]
    DIRECTION INPUT ;
    USE SIGNAL ;
    ANTENNAGATEAREA 0.495000 ;
    PORT
      LAYER met2 ;
        RECT 766.450 0.000 766.730 4.000 ;
    END
  END in_data[55]
  PIN in_data[560]
    DIRECTION INPUT ;
    USE SIGNAL ;
    ANTENNAGATEAREA 0.742500 ;
    PORT
      LAYER met2 ;
        RECT 193.290 0.000 193.570 4.000 ;
    END
  END in_data[560]
  PIN in_data[561]
    DIRECTION INPUT ;
    USE SIGNAL ;
    ANTENNAGATEAREA 0.495000 ;
    PORT
      LAYER met3 ;
        RECT 1296.000 992.840 1300.000 993.440 ;
    END
  END in_data[561]
  PIN in_data[562]
    DIRECTION INPUT ;
    USE SIGNAL ;
    ANTENNAGATEAREA 0.742500 ;
    PORT
      LAYER met2 ;
        RECT 1114.210 1296.000 1114.490 1300.000 ;
    END
  END in_data[562]
  PIN in_data[563]
    DIRECTION INPUT ;
    USE SIGNAL ;
    ANTENNAGATEAREA 0.742500 ;
    PORT
      LAYER met2 ;
        RECT 1291.310 1296.000 1291.590 1300.000 ;
    END
  END in_data[563]
  PIN in_data[564]
    DIRECTION INPUT ;
    USE SIGNAL ;
    ANTENNAGATEAREA 0.742500 ;
    PORT
      LAYER met3 ;
        RECT 1296.000 221.040 1300.000 221.640 ;
    END
  END in_data[564]
  PIN in_data[565]
    DIRECTION INPUT ;
    USE SIGNAL ;
    ANTENNAGATEAREA 0.426000 ;
    PORT
      LAYER met3 ;
        RECT 0.000 646.040 4.000 646.640 ;
    END
  END in_data[565]
  PIN in_data[566]
    DIRECTION INPUT ;
    USE SIGNAL ;
    ANTENNAGATEAREA 0.742500 ;
    PORT
      LAYER met3 ;
        RECT 1296.000 170.040 1300.000 170.640 ;
    END
  END in_data[566]
  PIN in_data[567]
    DIRECTION INPUT ;
    USE SIGNAL ;
    ANTENNAGATEAREA 0.426000 ;
    PORT
      LAYER met2 ;
        RECT 782.550 1296.000 782.830 1300.000 ;
    END
  END in_data[567]
  PIN in_data[568]
    DIRECTION INPUT ;
    USE SIGNAL ;
    ANTENNAGATEAREA 0.742500 ;
    PORT
      LAYER met3 ;
        RECT 0.000 353.640 4.000 354.240 ;
    END
  END in_data[568]
  PIN in_data[569]
    DIRECTION INPUT ;
    USE SIGNAL ;
    ANTENNAGATEAREA 0.852000 ;
    PORT
      LAYER met3 ;
        RECT 0.000 1166.240 4.000 1166.840 ;
    END
  END in_data[569]
  PIN in_data[56]
    DIRECTION INPUT ;
    USE SIGNAL ;
    ANTENNAGATEAREA 0.852000 ;
    PORT
      LAYER met2 ;
        RECT 1288.090 1296.000 1288.370 1300.000 ;
    END
  END in_data[56]
  PIN in_data[570]
    DIRECTION INPUT ;
    USE SIGNAL ;
    ANTENNAGATEAREA 0.852000 ;
    PORT
      LAYER met2 ;
        RECT 38.730 0.000 39.010 4.000 ;
    END
  END in_data[570]
  PIN in_data[571]
    DIRECTION INPUT ;
    USE SIGNAL ;
    ANTENNAGATEAREA 0.426000 ;
    PORT
      LAYER met3 ;
        RECT 1296.000 737.840 1300.000 738.440 ;
    END
  END in_data[571]
  PIN in_data[572]
    DIRECTION INPUT ;
    USE SIGNAL ;
    ANTENNAGATEAREA 0.495000 ;
    PORT
      LAYER met2 ;
        RECT 991.850 0.000 992.130 4.000 ;
    END
  END in_data[572]
  PIN in_data[573]
    DIRECTION INPUT ;
    USE SIGNAL ;
    ANTENNAGATEAREA 0.426000 ;
    PORT
      LAYER met3 ;
        RECT 0.000 697.040 4.000 697.640 ;
    END
  END in_data[573]
  PIN in_data[574]
    DIRECTION INPUT ;
    USE SIGNAL ;
    ANTENNAGATEAREA 0.742500 ;
    PORT
      LAYER met3 ;
        RECT 0.000 282.240 4.000 282.840 ;
    END
  END in_data[574]
  PIN in_data[575]
    DIRECTION INPUT ;
    USE SIGNAL ;
    ANTENNAGATEAREA 0.247500 ;
    PORT
      LAYER met2 ;
        RECT 753.570 0.000 753.850 4.000 ;
    END
  END in_data[575]
  PIN in_data[576]
    DIRECTION INPUT ;
    USE SIGNAL ;
    ANTENNAGATEAREA 0.742500 ;
    PORT
      LAYER met2 ;
        RECT 1252.670 1296.000 1252.950 1300.000 ;
    END
  END in_data[576]
  PIN in_data[577]
    DIRECTION INPUT ;
    USE SIGNAL ;
    ANTENNAGATEAREA 0.742500 ;
    PORT
      LAYER met2 ;
        RECT 1271.990 0.000 1272.270 4.000 ;
    END
  END in_data[577]
  PIN in_data[578]
    DIRECTION INPUT ;
    USE SIGNAL ;
    ANTENNAGATEAREA 0.742500 ;
    PORT
      LAYER met2 ;
        RECT 1281.650 1296.000 1281.930 1300.000 ;
    END
  END in_data[578]
  PIN in_data[579]
    DIRECTION INPUT ;
    USE SIGNAL ;
    ANTENNAGATEAREA 0.742500 ;
    PORT
      LAYER met2 ;
        RECT 1130.310 1296.000 1130.590 1300.000 ;
    END
  END in_data[579]
  PIN in_data[57]
    DIRECTION INPUT ;
    USE SIGNAL ;
    ANTENNAGATEAREA 0.495000 ;
    PORT
      LAYER met2 ;
        RECT 479.870 0.000 480.150 4.000 ;
    END
  END in_data[57]
  PIN in_data[580]
    DIRECTION INPUT ;
    USE SIGNAL ;
    ANTENNAGATEAREA 0.742500 ;
    PORT
      LAYER met2 ;
        RECT 225.490 1296.000 225.770 1300.000 ;
    END
  END in_data[580]
  PIN in_data[581]
    DIRECTION INPUT ;
    USE SIGNAL ;
    ANTENNAGATEAREA 0.426000 ;
    PORT
      LAYER met3 ;
        RECT 1296.000 486.240 1300.000 486.840 ;
    END
  END in_data[581]
  PIN in_data[582]
    DIRECTION INPUT ;
    USE SIGNAL ;
    ANTENNAGATEAREA 0.426000 ;
    PORT
      LAYER met3 ;
        RECT 1296.000 846.640 1300.000 847.240 ;
    END
  END in_data[582]
  PIN in_data[583]
    DIRECTION INPUT ;
    USE SIGNAL ;
    ANTENNAGATEAREA 0.852000 ;
    PORT
      LAYER met2 ;
        RECT 61.270 0.000 61.550 4.000 ;
    END
  END in_data[583]
  PIN in_data[584]
    DIRECTION INPUT ;
    USE SIGNAL ;
    ANTENNAGATEAREA 0.426000 ;
    PORT
      LAYER met2 ;
        RECT 624.770 1296.000 625.050 1300.000 ;
    END
  END in_data[584]
  PIN in_data[585]
    DIRECTION INPUT ;
    USE SIGNAL ;
    ANTENNAGATEAREA 0.495000 ;
    PORT
      LAYER met3 ;
        RECT 0.000 397.840 4.000 398.440 ;
    END
  END in_data[585]
  PIN in_data[586]
    DIRECTION INPUT ;
    USE SIGNAL ;
    ANTENNAGATEAREA 0.495000 ;
    PORT
      LAYER met3 ;
        RECT 0.000 884.040 4.000 884.640 ;
    END
  END in_data[586]
  PIN in_data[587]
    DIRECTION INPUT ;
    USE SIGNAL ;
    ANTENNAGATEAREA 0.426000 ;
    PORT
      LAYER met3 ;
        RECT 1296.000 734.440 1300.000 735.040 ;
    END
  END in_data[587]
  PIN in_data[588]
    DIRECTION INPUT ;
    USE SIGNAL ;
    ANTENNAGATEAREA 0.742500 ;
    PORT
      LAYER met2 ;
        RECT 351.070 1296.000 351.350 1300.000 ;
    END
  END in_data[588]
  PIN in_data[589]
    DIRECTION INPUT ;
    USE SIGNAL ;
    ANTENNAGATEAREA 0.742500 ;
    PORT
      LAYER met3 ;
        RECT 0.000 1043.840 4.000 1044.440 ;
    END
  END in_data[589]
  PIN in_data[58]
    DIRECTION INPUT ;
    USE SIGNAL ;
    ANTENNAGATEAREA 0.742500 ;
    PORT
      LAYER met3 ;
        RECT 1296.000 1159.440 1300.000 1160.040 ;
    END
  END in_data[58]
  PIN in_data[590]
    DIRECTION INPUT ;
    USE SIGNAL ;
    ANTENNAGATEAREA 0.742500 ;
    PORT
      LAYER met3 ;
        RECT 1296.000 71.440 1300.000 72.040 ;
    END
  END in_data[590]
  PIN in_data[591]
    DIRECTION INPUT ;
    USE SIGNAL ;
    ANTENNAGATEAREA 0.247500 ;
    PORT
      LAYER met3 ;
        RECT 1296.000 595.040 1300.000 595.640 ;
    END
  END in_data[591]
  PIN in_data[592]
    DIRECTION INPUT ;
    USE SIGNAL ;
    ANTENNAGATEAREA 0.495000 ;
    PORT
      LAYER met3 ;
        RECT 1296.000 326.440 1300.000 327.040 ;
    END
  END in_data[592]
  PIN in_data[593]
    DIRECTION INPUT ;
    USE SIGNAL ;
    ANTENNAGATEAREA 0.742500 ;
    PORT
      LAYER met3 ;
        RECT 0.000 1023.440 4.000 1024.040 ;
    END
  END in_data[593]
  PIN in_data[594]
    DIRECTION INPUT ;
    USE SIGNAL ;
    ANTENNAGATEAREA 0.495000 ;
    PORT
      LAYER met3 ;
        RECT 0.000 850.040 4.000 850.640 ;
    END
  END in_data[594]
  PIN in_data[595]
    DIRECTION INPUT ;
    USE SIGNAL ;
    ANTENNAGATEAREA 0.742500 ;
    PORT
      LAYER met3 ;
        RECT 0.000 969.040 4.000 969.640 ;
    END
  END in_data[595]
  PIN in_data[596]
    DIRECTION INPUT ;
    USE SIGNAL ;
    ANTENNAGATEAREA 0.852000 ;
    PORT
      LAYER met3 ;
        RECT 0.000 51.040 4.000 51.640 ;
    END
  END in_data[596]
  PIN in_data[597]
    DIRECTION INPUT ;
    USE SIGNAL ;
    ANTENNAGATEAREA 0.742500 ;
    PORT
      LAYER met2 ;
        RECT 1223.690 0.000 1223.970 4.000 ;
    END
  END in_data[597]
  PIN in_data[598]
    DIRECTION INPUT ;
    USE SIGNAL ;
    ANTENNAGATEAREA 0.426000 ;
    PORT
      LAYER met2 ;
        RECT 644.090 1296.000 644.370 1300.000 ;
    END
  END in_data[598]
  PIN in_data[599]
    DIRECTION INPUT ;
    USE SIGNAL ;
    ANTENNAGATEAREA 0.742500 ;
    PORT
      LAYER met2 ;
        RECT 154.650 1296.000 154.930 1300.000 ;
    END
  END in_data[599]
  PIN in_data[59]
    DIRECTION INPUT ;
    USE SIGNAL ;
    ANTENNAGATEAREA 0.742500 ;
    PORT
      LAYER met3 ;
        RECT 1296.000 1292.040 1300.000 1292.640 ;
    END
  END in_data[59]
  PIN in_data[5]
    DIRECTION INPUT ;
    USE SIGNAL ;
    ANTENNAGATEAREA 0.742500 ;
    PORT
      LAYER met3 ;
        RECT 0.000 1261.440 4.000 1262.040 ;
    END
  END in_data[5]
  PIN in_data[600]
    DIRECTION INPUT ;
    USE SIGNAL ;
    ANTENNAGATEAREA 0.742500 ;
    PORT
      LAYER met2 ;
        RECT 1114.210 0.000 1114.490 4.000 ;
    END
  END in_data[600]
  PIN in_data[601]
    DIRECTION INPUT ;
    USE SIGNAL ;
    ANTENNAGATEAREA 0.742500 ;
    PORT
      LAYER met2 ;
        RECT 1046.590 1296.000 1046.870 1300.000 ;
    END
  END in_data[601]
  PIN in_data[602]
    DIRECTION INPUT ;
    USE SIGNAL ;
    ANTENNAGATEAREA 0.426000 ;
    PORT
      LAYER met2 ;
        RECT 518.510 1296.000 518.790 1300.000 ;
    END
  END in_data[602]
  PIN in_data[603]
    DIRECTION INPUT ;
    USE SIGNAL ;
    ANTENNAGATEAREA 0.426000 ;
    PORT
      LAYER met3 ;
        RECT 1296.000 404.640 1300.000 405.240 ;
    END
  END in_data[603]
  PIN in_data[604]
    DIRECTION INPUT ;
    USE SIGNAL ;
    ANTENNAGATEAREA 0.247500 ;
    PORT
      LAYER met2 ;
        RECT 692.390 0.000 692.670 4.000 ;
    END
  END in_data[604]
  PIN in_data[605]
    DIRECTION INPUT ;
    USE SIGNAL ;
    ANTENNAGATEAREA 0.247500 ;
    PORT
      LAYER met2 ;
        RECT 714.930 0.000 715.210 4.000 ;
    END
  END in_data[605]
  PIN in_data[606]
    DIRECTION INPUT ;
    USE SIGNAL ;
    ANTENNAGATEAREA 0.247500 ;
    PORT
      LAYER met2 ;
        RECT 756.790 0.000 757.070 4.000 ;
    END
  END in_data[606]
  PIN in_data[607]
    DIRECTION INPUT ;
    USE SIGNAL ;
    ANTENNAGATEAREA 0.247500 ;
    PORT
      LAYER met3 ;
        RECT 1296.000 557.640 1300.000 558.240 ;
    END
  END in_data[607]
  PIN in_data[608]
    DIRECTION INPUT ;
    USE SIGNAL ;
    ANTENNAGATEAREA 0.742500 ;
    PORT
      LAYER met3 ;
        RECT 0.000 979.240 4.000 979.840 ;
    END
  END in_data[608]
  PIN in_data[609]
    DIRECTION INPUT ;
    USE SIGNAL ;
    ANTENNAGATEAREA 0.742500 ;
    PORT
      LAYER met3 ;
        RECT 1296.000 176.840 1300.000 177.440 ;
    END
  END in_data[609]
  PIN in_data[60]
    DIRECTION INPUT ;
    USE SIGNAL ;
    ANTENNAGATEAREA 0.426000 ;
    PORT
      LAYER met3 ;
        RECT 0.000 860.240 4.000 860.840 ;
    END
  END in_data[60]
  PIN in_data[610]
    DIRECTION INPUT ;
    USE SIGNAL ;
    ANTENNAGATEAREA 0.495000 ;
    PORT
      LAYER met3 ;
        RECT 0.000 867.040 4.000 867.640 ;
    END
  END in_data[610]
  PIN in_data[611]
    DIRECTION INPUT ;
    USE SIGNAL ;
    ANTENNAGATEAREA 0.426000 ;
    PORT
      LAYER met2 ;
        RECT 827.630 1296.000 827.910 1300.000 ;
    END
  END in_data[611]
  PIN in_data[612]
    DIRECTION INPUT ;
    USE SIGNAL ;
    ANTENNAGATEAREA 0.495000 ;
    PORT
      LAYER met2 ;
        RECT 888.810 0.000 889.090 4.000 ;
    END
  END in_data[612]
  PIN in_data[613]
    DIRECTION INPUT ;
    USE SIGNAL ;
    ANTENNAGATEAREA 0.495000 ;
    PORT
      LAYER met3 ;
        RECT 0.000 846.640 4.000 847.240 ;
    END
  END in_data[613]
  PIN in_data[614]
    DIRECTION INPUT ;
    USE SIGNAL ;
    ANTENNAGATEAREA 0.742500 ;
    PORT
      LAYER met2 ;
        RECT 83.810 1296.000 84.090 1300.000 ;
    END
  END in_data[614]
  PIN in_data[615]
    DIRECTION INPUT ;
    USE SIGNAL ;
    ANTENNAGATEAREA 0.742500 ;
    PORT
      LAYER met3 ;
        RECT 1296.000 1241.040 1300.000 1241.640 ;
    END
  END in_data[615]
  PIN in_data[616]
    DIRECTION INPUT ;
    USE SIGNAL ;
    ANTENNAGATEAREA 0.495000 ;
    PORT
      LAYER met3 ;
        RECT 1296.000 924.840 1300.000 925.440 ;
    END
  END in_data[616]
  PIN in_data[617]
    DIRECTION INPUT ;
    USE SIGNAL ;
    ANTENNAGATEAREA 0.426000 ;
    PORT
      LAYER met3 ;
        RECT 1296.000 635.840 1300.000 636.440 ;
    END
  END in_data[617]
  PIN in_data[618]
    DIRECTION INPUT ;
    USE SIGNAL ;
    ANTENNAGATEAREA 0.247500 ;
    PORT
      LAYER met2 ;
        RECT 669.850 1296.000 670.130 1300.000 ;
    END
  END in_data[618]
  PIN in_data[619]
    DIRECTION INPUT ;
    USE SIGNAL ;
    ANTENNAGATEAREA 0.495000 ;
    PORT
      LAYER met3 ;
        RECT 1296.000 941.840 1300.000 942.440 ;
    END
  END in_data[619]
  PIN in_data[61]
    DIRECTION INPUT ;
    USE SIGNAL ;
    ANTENNAGATEAREA 0.495000 ;
    PORT
      LAYER met2 ;
        RECT 521.730 0.000 522.010 4.000 ;
    END
  END in_data[61]
  PIN in_data[620]
    DIRECTION INPUT ;
    USE SIGNAL ;
    ANTENNAGATEAREA 0.742500 ;
    PORT
      LAYER met3 ;
        RECT 0.000 115.640 4.000 116.240 ;
    END
  END in_data[620]
  PIN in_data[621]
    DIRECTION INPUT ;
    USE SIGNAL ;
    ANTENNAGATEAREA 0.495000 ;
    PORT
      LAYER met3 ;
        RECT 0.000 958.840 4.000 959.440 ;
    END
  END in_data[621]
  PIN in_data[622]
    DIRECTION INPUT ;
    USE SIGNAL ;
    ANTENNAGATEAREA 0.426000 ;
    PORT
      LAYER met2 ;
        RECT 698.830 0.000 699.110 4.000 ;
    END
  END in_data[622]
  PIN in_data[623]
    DIRECTION INPUT ;
    USE SIGNAL ;
    ANTENNAGATEAREA 0.852000 ;
    PORT
      LAYER met2 ;
        RECT 48.390 0.000 48.670 4.000 ;
    END
  END in_data[623]
  PIN in_data[624]
    DIRECTION INPUT ;
    USE SIGNAL ;
    ANTENNAGATEAREA 0.426000 ;
    PORT
      LAYER met3 ;
        RECT 1296.000 856.840 1300.000 857.440 ;
    END
  END in_data[624]
  PIN in_data[625]
    DIRECTION INPUT ;
    USE SIGNAL ;
    ANTENNAGATEAREA 0.742500 ;
    PORT
      LAYER met2 ;
        RECT 389.710 1296.000 389.990 1300.000 ;
    END
  END in_data[625]
  PIN in_data[626]
    DIRECTION INPUT ;
    USE SIGNAL ;
    ANTENNAGATEAREA 0.426000 ;
    PORT
      LAYER met2 ;
        RECT 663.410 0.000 663.690 4.000 ;
    END
  END in_data[626]
  PIN in_data[627]
    DIRECTION INPUT ;
    USE SIGNAL ;
    ANTENNAGATEAREA 0.426000 ;
    PORT
      LAYER met2 ;
        RECT 866.270 1296.000 866.550 1300.000 ;
    END
  END in_data[627]
  PIN in_data[628]
    DIRECTION INPUT ;
    USE SIGNAL ;
    ANTENNAGATEAREA 0.426000 ;
    PORT
      LAYER met3 ;
        RECT 1296.000 683.440 1300.000 684.040 ;
    END
  END in_data[628]
  PIN in_data[629]
    DIRECTION INPUT ;
    USE SIGNAL ;
    ANTENNAGATEAREA 0.742500 ;
    PORT
      LAYER met3 ;
        RECT 1296.000 40.840 1300.000 41.440 ;
    END
  END in_data[629]
  PIN in_data[62]
    DIRECTION INPUT ;
    USE SIGNAL ;
    ANTENNAGATEAREA 0.426000 ;
    PORT
      LAYER met3 ;
        RECT 1296.000 816.040 1300.000 816.640 ;
    END
  END in_data[62]
  PIN in_data[630]
    DIRECTION INPUT ;
    USE SIGNAL ;
    ANTENNAGATEAREA 0.426000 ;
    PORT
      LAYER met3 ;
        RECT 0.000 612.040 4.000 612.640 ;
    END
  END in_data[630]
  PIN in_data[631]
    DIRECTION INPUT ;
    USE SIGNAL ;
    ANTENNAGATEAREA 0.742500 ;
    PORT
      LAYER met3 ;
        RECT 0.000 1098.240 4.000 1098.840 ;
    END
  END in_data[631]
  PIN in_data[632]
    DIRECTION INPUT ;
    USE SIGNAL ;
    ANTENNAGATEAREA 0.495000 ;
    PORT
      LAYER met2 ;
        RECT 917.790 0.000 918.070 4.000 ;
    END
  END in_data[632]
  PIN in_data[633]
    DIRECTION INPUT ;
    USE SIGNAL ;
    ANTENNAGATEAREA 0.495000 ;
    PORT
      LAYER met2 ;
        RECT 483.090 0.000 483.370 4.000 ;
    END
  END in_data[633]
  PIN in_data[634]
    DIRECTION INPUT ;
    USE SIGNAL ;
    ANTENNAGATEAREA 0.742500 ;
    PORT
      LAYER met2 ;
        RECT 206.170 1296.000 206.450 1300.000 ;
    END
  END in_data[634]
  PIN in_data[635]
    DIRECTION INPUT ;
    USE SIGNAL ;
    ANTENNAGATEAREA 0.852000 ;
    PORT
      LAYER met2 ;
        RECT 12.970 0.000 13.250 4.000 ;
    END
  END in_data[635]
  PIN in_data[636]
    DIRECTION INPUT ;
    USE SIGNAL ;
    ANTENNAGATEAREA 0.495000 ;
    PORT
      LAYER met2 ;
        RECT 879.150 1296.000 879.430 1300.000 ;
    END
  END in_data[636]
  PIN in_data[637]
    DIRECTION INPUT ;
    USE SIGNAL ;
    ANTENNAGATEAREA 0.426000 ;
    PORT
      LAYER met3 ;
        RECT 1296.000 754.840 1300.000 755.440 ;
    END
  END in_data[637]
  PIN in_data[638]
    DIRECTION INPUT ;
    USE SIGNAL ;
    ANTENNAGATEAREA 0.495000 ;
    PORT
      LAYER met2 ;
        RECT 972.530 1296.000 972.810 1300.000 ;
    END
  END in_data[638]
  PIN in_data[639]
    DIRECTION INPUT ;
    USE SIGNAL ;
    ANTENNAGATEAREA 0.495000 ;
    PORT
      LAYER met2 ;
        RECT 376.830 1296.000 377.110 1300.000 ;
    END
  END in_data[639]
  PIN in_data[63]
    DIRECTION INPUT ;
    USE SIGNAL ;
    ANTENNAGATEAREA 0.742500 ;
    PORT
      LAYER met2 ;
        RECT 1133.530 0.000 1133.810 4.000 ;
    END
  END in_data[63]
  PIN in_data[640]
    DIRECTION INPUT ;
    USE SIGNAL ;
    ANTENNAGATEAREA 0.852000 ;
    PORT
      LAYER met2 ;
        RECT 22.630 1296.000 22.910 1300.000 ;
    END
  END in_data[640]
  PIN in_data[641]
    DIRECTION INPUT ;
    USE SIGNAL ;
    ANTENNAGATEAREA 0.426000 ;
    PORT
      LAYER met3 ;
        RECT 1296.000 503.240 1300.000 503.840 ;
    END
  END in_data[641]
  PIN in_data[642]
    DIRECTION INPUT ;
    USE SIGNAL ;
    ANTENNAGATEAREA 0.426000 ;
    PORT
      LAYER met3 ;
        RECT 1296.000 588.240 1300.000 588.840 ;
    END
  END in_data[642]
  PIN in_data[643]
    DIRECTION INPUT ;
    USE SIGNAL ;
    ANTENNAGATEAREA 0.426000 ;
    PORT
      LAYER met3 ;
        RECT 1296.000 795.640 1300.000 796.240 ;
    END
  END in_data[643]
  PIN in_data[644]
    DIRECTION INPUT ;
    USE SIGNAL ;
    ANTENNAGATEAREA 0.742500 ;
    PORT
      LAYER met3 ;
        RECT 0.000 1145.840 4.000 1146.440 ;
    END
  END in_data[644]
  PIN in_data[645]
    DIRECTION INPUT ;
    USE SIGNAL ;
    ANTENNAGATEAREA 0.742500 ;
    PORT
      LAYER met3 ;
        RECT 1296.000 1179.840 1300.000 1180.440 ;
    END
  END in_data[645]
  PIN in_data[646]
    DIRECTION INPUT ;
    USE SIGNAL ;
    ANTENNAGATEAREA 0.426000 ;
    PORT
      LAYER met3 ;
        RECT 0.000 659.640 4.000 660.240 ;
    END
  END in_data[646]
  PIN in_data[647]
    DIRECTION INPUT ;
    USE SIGNAL ;
    ANTENNAGATEAREA 0.426000 ;
    PORT
      LAYER met2 ;
        RECT 940.330 1296.000 940.610 1300.000 ;
    END
  END in_data[647]
  PIN in_data[648]
    DIRECTION INPUT ;
    USE SIGNAL ;
    ANTENNAGATEAREA 0.742500 ;
    PORT
      LAYER met2 ;
        RECT 257.690 0.000 257.970 4.000 ;
    END
  END in_data[648]
  PIN in_data[649]
    DIRECTION INPUT ;
    USE SIGNAL ;
    ANTENNAGATEAREA 0.742500 ;
    PORT
      LAYER met2 ;
        RECT 1194.710 1296.000 1194.990 1300.000 ;
    END
  END in_data[649]
  PIN in_data[64]
    DIRECTION INPUT ;
    USE SIGNAL ;
    ANTENNAGATEAREA 0.426000 ;
    PORT
      LAYER met3 ;
        RECT 1296.000 727.640 1300.000 728.240 ;
    END
  END in_data[64]
  PIN in_data[650]
    DIRECTION INPUT ;
    USE SIGNAL ;
    ANTENNAGATEAREA 0.495000 ;
    PORT
      LAYER met2 ;
        RECT 1072.350 1296.000 1072.630 1300.000 ;
    END
  END in_data[650]
  PIN in_data[651]
    DIRECTION INPUT ;
    USE SIGNAL ;
    ANTENNAGATEAREA 0.742500 ;
    PORT
      LAYER met3 ;
        RECT 1296.000 1190.040 1300.000 1190.640 ;
    END
  END in_data[651]
  PIN in_data[652]
    DIRECTION INPUT ;
    USE SIGNAL ;
    ANTENNAGATEAREA 0.742500 ;
    PORT
      LAYER met3 ;
        RECT 0.000 1237.640 4.000 1238.240 ;
    END
  END in_data[652]
  PIN in_data[653]
    DIRECTION INPUT ;
    USE SIGNAL ;
    ANTENNAGATEAREA 0.495000 ;
    PORT
      LAYER met2 ;
        RECT 1062.690 1296.000 1062.970 1300.000 ;
    END
  END in_data[653]
  PIN in_data[654]
    DIRECTION INPUT ;
    USE SIGNAL ;
    ANTENNAGATEAREA 0.495000 ;
    PORT
      LAYER met3 ;
        RECT 0.000 904.440 4.000 905.040 ;
    END
  END in_data[654]
  PIN in_data[655]
    DIRECTION INPUT ;
    USE SIGNAL ;
    ANTENNAGATEAREA 0.495000 ;
    PORT
      LAYER met2 ;
        RECT 331.750 1296.000 332.030 1300.000 ;
    END
  END in_data[655]
  PIN in_data[656]
    DIRECTION INPUT ;
    USE SIGNAL ;
    ANTENNAGATEAREA 0.742500 ;
    PORT
      LAYER met2 ;
        RECT 1175.390 1296.000 1175.670 1300.000 ;
    END
  END in_data[656]
  PIN in_data[657]
    DIRECTION INPUT ;
    USE SIGNAL ;
    ANTENNAGATEAREA 0.495000 ;
    PORT
      LAYER met3 ;
        RECT 1296.000 1033.640 1300.000 1034.240 ;
    END
  END in_data[657]
  PIN in_data[658]
    DIRECTION INPUT ;
    USE SIGNAL ;
    ANTENNAGATEAREA 0.495000 ;
    PORT
      LAYER met3 ;
        RECT 1296.000 955.440 1300.000 956.040 ;
    END
  END in_data[658]
  PIN in_data[659]
    DIRECTION INPUT ;
    USE SIGNAL ;
    ANTENNAGATEAREA 0.495000 ;
    PORT
      LAYER met2 ;
        RECT 396.150 1296.000 396.430 1300.000 ;
    END
  END in_data[659]
  PIN in_data[65]
    DIRECTION INPUT ;
    USE SIGNAL ;
    ANTENNAGATEAREA 0.426000 ;
    PORT
      LAYER met3 ;
        RECT 0.000 591.640 4.000 592.240 ;
    END
  END in_data[65]
  PIN in_data[660]
    DIRECTION INPUT ;
    USE SIGNAL ;
    ANTENNAGATEAREA 0.742500 ;
    PORT
      LAYER met2 ;
        RECT 1072.350 0.000 1072.630 4.000 ;
    END
  END in_data[660]
  PIN in_data[661]
    DIRECTION INPUT ;
    USE SIGNAL ;
    ANTENNAGATEAREA 0.426000 ;
    PORT
      LAYER met2 ;
        RECT 595.790 0.000 596.070 4.000 ;
    END
  END in_data[661]
  PIN in_data[662]
    DIRECTION INPUT ;
    USE SIGNAL ;
    ANTENNAGATEAREA 0.426000 ;
    PORT
      LAYER met3 ;
        RECT 1296.000 744.640 1300.000 745.240 ;
    END
  END in_data[662]
  PIN in_data[663]
    DIRECTION INPUT ;
    USE SIGNAL ;
    ANTENNAGATEAREA 0.495000 ;
    PORT
      LAYER met2 ;
        RECT 1027.270 1296.000 1027.550 1300.000 ;
    END
  END in_data[663]
  PIN in_data[664]
    DIRECTION INPUT ;
    USE SIGNAL ;
    ANTENNAGATEAREA 0.426000 ;
    PORT
      LAYER met2 ;
        RECT 563.590 1296.000 563.870 1300.000 ;
    END
  END in_data[664]
  PIN in_data[665]
    DIRECTION INPUT ;
    USE SIGNAL ;
    ANTENNAGATEAREA 0.426000 ;
    PORT
      LAYER met3 ;
        RECT 1296.000 506.640 1300.000 507.240 ;
    END
  END in_data[665]
  PIN in_data[666]
    DIRECTION INPUT ;
    USE SIGNAL ;
    ANTENNAGATEAREA 0.495000 ;
    PORT
      LAYER met2 ;
        RECT 969.310 1296.000 969.590 1300.000 ;
    END
  END in_data[666]
  PIN in_data[667]
    DIRECTION INPUT ;
    USE SIGNAL ;
    ANTENNAGATEAREA 0.426000 ;
    PORT
      LAYER met2 ;
        RECT 743.910 1296.000 744.190 1300.000 ;
    END
  END in_data[667]
  PIN in_data[668]
    DIRECTION INPUT ;
    USE SIGNAL ;
    ANTENNAGATEAREA 0.742500 ;
    PORT
      LAYER met2 ;
        RECT 293.110 0.000 293.390 4.000 ;
    END
  END in_data[668]
  PIN in_data[669]
    DIRECTION INPUT ;
    USE SIGNAL ;
    ANTENNAGATEAREA 0.742500 ;
    PORT
      LAYER met3 ;
        RECT 0.000 1173.040 4.000 1173.640 ;
    END
  END in_data[669]
  PIN in_data[66]
    DIRECTION INPUT ;
    USE SIGNAL ;
    ANTENNAGATEAREA 0.495000 ;
    PORT
      LAYER met2 ;
        RECT 772.890 0.000 773.170 4.000 ;
    END
  END in_data[66]
  PIN in_data[670]
    DIRECTION INPUT ;
    USE SIGNAL ;
    ANTENNAGATEAREA 0.852000 ;
    PORT
      LAYER met2 ;
        RECT 51.610 1296.000 51.890 1300.000 ;
    END
  END in_data[670]
  PIN in_data[671]
    DIRECTION INPUT ;
    USE SIGNAL ;
    ANTENNAGATEAREA 0.495000 ;
    PORT
      LAYER met3 ;
        RECT 1296.000 428.440 1300.000 429.040 ;
    END
  END in_data[671]
  PIN in_data[672]
    DIRECTION INPUT ;
    USE SIGNAL ;
    ANTENNAGATEAREA 0.852000 ;
    PORT
      LAYER met3 ;
        RECT 0.000 81.640 4.000 82.240 ;
    END
  END in_data[672]
  PIN in_data[673]
    DIRECTION INPUT ;
    USE SIGNAL ;
    ANTENNAGATEAREA 0.426000 ;
    PORT
      LAYER met3 ;
        RECT 1296.000 516.840 1300.000 517.440 ;
    END
  END in_data[673]
  PIN in_data[674]
    DIRECTION INPUT ;
    USE SIGNAL ;
    ANTENNAGATEAREA 0.247500 ;
    PORT
      LAYER met2 ;
        RECT 650.530 1296.000 650.810 1300.000 ;
    END
  END in_data[674]
  PIN in_data[675]
    DIRECTION INPUT ;
    USE SIGNAL ;
    ANTENNAGATEAREA 0.742500 ;
    PORT
      LAYER met2 ;
        RECT 1185.050 1296.000 1185.330 1300.000 ;
    END
  END in_data[675]
  PIN in_data[676]
    DIRECTION INPUT ;
    USE SIGNAL ;
    ANTENNAGATEAREA 0.495000 ;
    PORT
      LAYER met3 ;
        RECT 0.000 418.240 4.000 418.840 ;
    END
  END in_data[676]
  PIN in_data[677]
    DIRECTION INPUT ;
    USE SIGNAL ;
    ANTENNAGATEAREA 0.495000 ;
    PORT
      LAYER met3 ;
        RECT 1296.000 890.840 1300.000 891.440 ;
    END
  END in_data[677]
  PIN in_data[678]
    DIRECTION INPUT ;
    USE SIGNAL ;
    ANTENNAGATEAREA 0.495000 ;
    PORT
      LAYER met2 ;
        RECT 441.230 1296.000 441.510 1300.000 ;
    END
  END in_data[678]
  PIN in_data[679]
    DIRECTION INPUT ;
    USE SIGNAL ;
    ANTENNAGATEAREA 0.495000 ;
    PORT
      LAYER met3 ;
        RECT 0.000 462.440 4.000 463.040 ;
    END
  END in_data[679]
  PIN in_data[67]
    DIRECTION INPUT ;
    USE SIGNAL ;
    ANTENNAGATEAREA 0.742500 ;
    PORT
      LAYER met3 ;
        RECT 1296.000 1023.440 1300.000 1024.040 ;
    END
  END in_data[67]
  PIN in_data[680]
    DIRECTION INPUT ;
    USE SIGNAL ;
    ANTENNAGATEAREA 0.495000 ;
    PORT
      LAYER met2 ;
        RECT 962.870 1296.000 963.150 1300.000 ;
    END
  END in_data[680]
  PIN in_data[681]
    DIRECTION INPUT ;
    USE SIGNAL ;
    ANTENNAGATEAREA 0.742500 ;
    PORT
      LAYER met3 ;
        RECT 0.000 241.440 4.000 242.040 ;
    END
  END in_data[681]
  PIN in_data[682]
    DIRECTION INPUT ;
    USE SIGNAL ;
    ANTENNAGATEAREA 0.742500 ;
    PORT
      LAYER met3 ;
        RECT 0.000 1108.440 4.000 1109.040 ;
    END
  END in_data[682]
  PIN in_data[683]
    DIRECTION INPUT ;
    USE SIGNAL ;
    ANTENNAGATEAREA 0.247500 ;
    PORT
      LAYER met2 ;
        RECT 682.730 0.000 683.010 4.000 ;
    END
  END in_data[683]
  PIN in_data[684]
    DIRECTION INPUT ;
    USE SIGNAL ;
    ANTENNAGATEAREA 0.742500 ;
    PORT
      LAYER met2 ;
        RECT 370.390 0.000 370.670 4.000 ;
    END
  END in_data[684]
  PIN in_data[685]
    DIRECTION INPUT ;
    USE SIGNAL ;
    ANTENNAGATEAREA 0.742500 ;
    PORT
      LAYER met3 ;
        RECT 1296.000 1183.240 1300.000 1183.840 ;
    END
  END in_data[685]
  PIN in_data[686]
    DIRECTION INPUT ;
    USE SIGNAL ;
    ANTENNAGATEAREA 0.742500 ;
    PORT
      LAYER met3 ;
        RECT 0.000 401.240 4.000 401.840 ;
    END
  END in_data[686]
  PIN in_data[687]
    DIRECTION INPUT ;
    USE SIGNAL ;
    ANTENNAGATEAREA 0.742500 ;
    PORT
      LAYER met3 ;
        RECT 0.000 299.240 4.000 299.840 ;
    END
  END in_data[687]
  PIN in_data[688]
    DIRECTION INPUT ;
    USE SIGNAL ;
    ANTENNAGATEAREA 0.742500 ;
    PORT
      LAYER met3 ;
        RECT 0.000 309.440 4.000 310.040 ;
    END
  END in_data[688]
  PIN in_data[689]
    DIRECTION INPUT ;
    USE SIGNAL ;
    ANTENNAGATEAREA 0.742500 ;
    PORT
      LAYER met2 ;
        RECT 1056.250 1296.000 1056.530 1300.000 ;
    END
  END in_data[689]
  PIN in_data[68]
    DIRECTION INPUT ;
    USE SIGNAL ;
    ANTENNAGATEAREA 0.426000 ;
    PORT
      LAYER met2 ;
        RECT 718.150 1296.000 718.430 1300.000 ;
    END
  END in_data[68]
  PIN in_data[690]
    DIRECTION INPUT ;
    USE SIGNAL ;
    ANTENNAGATEAREA 0.495000 ;
    PORT
      LAYER met3 ;
        RECT 1296.000 445.440 1300.000 446.040 ;
    END
  END in_data[690]
  PIN in_data[691]
    DIRECTION INPUT ;
    USE SIGNAL ;
    ANTENNAGATEAREA 0.852000 ;
    PORT
      LAYER met2 ;
        RECT 1284.870 0.000 1285.150 4.000 ;
    END
  END in_data[691]
  PIN in_data[692]
    DIRECTION INPUT ;
    USE SIGNAL ;
    ANTENNAGATEAREA 0.852000 ;
    PORT
      LAYER met3 ;
        RECT 1296.000 27.240 1300.000 27.840 ;
    END
  END in_data[692]
  PIN in_data[693]
    DIRECTION INPUT ;
    USE SIGNAL ;
    ANTENNAGATEAREA 0.495000 ;
    PORT
      LAYER met3 ;
        RECT 0.000 428.440 4.000 429.040 ;
    END
  END in_data[693]
  PIN in_data[694]
    DIRECTION INPUT ;
    USE SIGNAL ;
    ANTENNAGATEAREA 0.247500 ;
    PORT
      LAYER met2 ;
        RECT 685.950 1296.000 686.230 1300.000 ;
    END
  END in_data[694]
  PIN in_data[695]
    DIRECTION INPUT ;
    USE SIGNAL ;
    ANTENNAGATEAREA 0.247500 ;
    PORT
      LAYER met2 ;
        RECT 579.690 0.000 579.970 4.000 ;
    END
  END in_data[695]
  PIN in_data[696]
    DIRECTION INPUT ;
    USE SIGNAL ;
    ANTENNAGATEAREA 0.495000 ;
    PORT
      LAYER met3 ;
        RECT 0.000 799.040 4.000 799.640 ;
    END
  END in_data[696]
  PIN in_data[697]
    DIRECTION INPUT ;
    USE SIGNAL ;
    ANTENNAGATEAREA 0.742500 ;
    PORT
      LAYER met3 ;
        RECT 0.000 1105.040 4.000 1105.640 ;
    END
  END in_data[697]
  PIN in_data[698]
    DIRECTION INPUT ;
    USE SIGNAL ;
    ANTENNAGATEAREA 0.742500 ;
    PORT
      LAYER met2 ;
        RECT 1168.950 0.000 1169.230 4.000 ;
    END
  END in_data[698]
  PIN in_data[699]
    DIRECTION INPUT ;
    USE SIGNAL ;
    ANTENNAGATEAREA 0.426000 ;
    PORT
      LAYER met2 ;
        RECT 763.230 0.000 763.510 4.000 ;
    END
  END in_data[699]
  PIN in_data[69]
    DIRECTION INPUT ;
    USE SIGNAL ;
    ANTENNAGATEAREA 0.742500 ;
    PORT
      LAYER met2 ;
        RECT 1101.330 1296.000 1101.610 1300.000 ;
    END
  END in_data[69]
  PIN in_data[6]
    DIRECTION INPUT ;
    USE SIGNAL ;
    ANTENNAGATEAREA 0.247500 ;
    PORT
      LAYER met3 ;
        RECT 0.000 731.040 4.000 731.640 ;
    END
  END in_data[6]
  PIN in_data[700]
    DIRECTION INPUT ;
    USE SIGNAL ;
    ANTENNAGATEAREA 0.426000 ;
    PORT
      LAYER met3 ;
        RECT 0.000 639.240 4.000 639.840 ;
    END
  END in_data[700]
  PIN in_data[701]
    DIRECTION INPUT ;
    USE SIGNAL ;
    ANTENNAGATEAREA 0.852000 ;
    PORT
      LAYER met2 ;
        RECT 51.610 0.000 51.890 4.000 ;
    END
  END in_data[701]
  PIN in_data[702]
    DIRECTION INPUT ;
    USE SIGNAL ;
    ANTENNAGATEAREA 0.426000 ;
    PORT
      LAYER met2 ;
        RECT 743.910 0.000 744.190 4.000 ;
    END
  END in_data[702]
  PIN in_data[703]
    DIRECTION INPUT ;
    USE SIGNAL ;
    ANTENNAGATEAREA 0.742500 ;
    PORT
      LAYER met3 ;
        RECT 1296.000 1054.040 1300.000 1054.640 ;
    END
  END in_data[703]
  PIN in_data[704]
    DIRECTION INPUT ;
    USE SIGNAL ;
    ANTENNAGATEAREA 0.742500 ;
    PORT
      LAYER met2 ;
        RECT 1104.550 0.000 1104.830 4.000 ;
    END
  END in_data[704]
  PIN in_data[705]
    DIRECTION INPUT ;
    USE SIGNAL ;
    ANTENNAGATEAREA 0.426000 ;
    PORT
      LAYER met3 ;
        RECT 1296.000 751.440 1300.000 752.040 ;
    END
  END in_data[705]
  PIN in_data[706]
    DIRECTION INPUT ;
    USE SIGNAL ;
    ANTENNAGATEAREA 0.495000 ;
    PORT
      LAYER met2 ;
        RECT 901.690 1296.000 901.970 1300.000 ;
    END
  END in_data[706]
  PIN in_data[707]
    DIRECTION INPUT ;
    USE SIGNAL ;
    ANTENNAGATEAREA 0.742500 ;
    PORT
      LAYER met2 ;
        RECT 135.330 0.000 135.610 4.000 ;
    END
  END in_data[707]
  PIN in_data[708]
    DIRECTION INPUT ;
    USE SIGNAL ;
    ANTENNAGATEAREA 0.742500 ;
    PORT
      LAYER met3 ;
        RECT 1296.000 1142.440 1300.000 1143.040 ;
    END
  END in_data[708]
  PIN in_data[709]
    DIRECTION INPUT ;
    USE SIGNAL ;
    ANTENNAGATEAREA 0.247500 ;
    PORT
      LAYER met2 ;
        RECT 634.430 0.000 634.710 4.000 ;
    END
  END in_data[709]
  PIN in_data[70]
    DIRECTION INPUT ;
    USE SIGNAL ;
    ANTENNAGATEAREA 0.495000 ;
    PORT
      LAYER met2 ;
        RECT 267.350 1296.000 267.630 1300.000 ;
    END
  END in_data[70]
  PIN in_data[710]
    DIRECTION INPUT ;
    USE SIGNAL ;
    ANTENNAGATEAREA 0.742500 ;
    PORT
      LAYER met2 ;
        RECT 170.750 1296.000 171.030 1300.000 ;
    END
  END in_data[710]
  PIN in_data[711]
    DIRECTION INPUT ;
    USE SIGNAL ;
    ANTENNAGATEAREA 0.426000 ;
    PORT
      LAYER met2 ;
        RECT 518.510 0.000 518.790 4.000 ;
    END
  END in_data[711]
  PIN in_data[712]
    DIRECTION INPUT ;
    USE SIGNAL ;
    ANTENNAGATEAREA 0.742500 ;
    PORT
      LAYER met2 ;
        RECT 953.210 1296.000 953.490 1300.000 ;
    END
  END in_data[712]
  PIN in_data[713]
    DIRECTION INPUT ;
    USE SIGNAL ;
    ANTENNAGATEAREA 0.742500 ;
    PORT
      LAYER met2 ;
        RECT 1075.570 1296.000 1075.850 1300.000 ;
    END
  END in_data[713]
  PIN in_data[714]
    DIRECTION INPUT ;
    USE SIGNAL ;
    ANTENNAGATEAREA 0.495000 ;
    PORT
      LAYER met3 ;
        RECT 0.000 333.240 4.000 333.840 ;
    END
  END in_data[714]
  PIN in_data[715]
    DIRECTION INPUT ;
    USE SIGNAL ;
    ANTENNAGATEAREA 0.742500 ;
    PORT
      LAYER met2 ;
        RECT 1001.510 1296.000 1001.790 1300.000 ;
    END
  END in_data[715]
  PIN in_data[716]
    DIRECTION INPUT ;
    USE SIGNAL ;
    ANTENNAGATEAREA 0.426000 ;
    PORT
      LAYER met3 ;
        RECT 0.000 720.840 4.000 721.440 ;
    END
  END in_data[716]
  PIN in_data[717]
    DIRECTION INPUT ;
    USE SIGNAL ;
    ANTENNAGATEAREA 0.742500 ;
    PORT
      LAYER met3 ;
        RECT 1296.000 88.440 1300.000 89.040 ;
    END
  END in_data[717]
  PIN in_data[718]
    DIRECTION INPUT ;
    USE SIGNAL ;
    ANTENNAGATEAREA 0.495000 ;
    PORT
      LAYER met2 ;
        RECT 347.850 1296.000 348.130 1300.000 ;
    END
  END in_data[718]
  PIN in_data[719]
    DIRECTION INPUT ;
    USE SIGNAL ;
    ANTENNAGATEAREA 0.495000 ;
    PORT
      LAYER met2 ;
        RECT 405.810 1296.000 406.090 1300.000 ;
    END
  END in_data[719]
  PIN in_data[71]
    DIRECTION INPUT ;
    USE SIGNAL ;
    ANTENNAGATEAREA 0.742500 ;
    PORT
      LAYER met3 ;
        RECT 0.000 251.640 4.000 252.240 ;
    END
  END in_data[71]
  PIN in_data[720]
    DIRECTION INPUT ;
    USE SIGNAL ;
    ANTENNAGATEAREA 0.852000 ;
    PORT
      LAYER met3 ;
        RECT 0.000 1295.440 4.000 1296.040 ;
    END
  END in_data[720]
  PIN in_data[721]
    DIRECTION INPUT ;
    USE SIGNAL ;
    ANTENNAGATEAREA 0.742500 ;
    PORT
      LAYER met2 ;
        RECT 1281.650 0.000 1281.930 4.000 ;
    END
  END in_data[721]
  PIN in_data[722]
    DIRECTION INPUT ;
    USE SIGNAL ;
    ANTENNAGATEAREA 0.742500 ;
    PORT
      LAYER met3 ;
        RECT 0.000 1074.440 4.000 1075.040 ;
    END
  END in_data[722]
  PIN in_data[723]
    DIRECTION INPUT ;
    USE SIGNAL ;
    ANTENNAGATEAREA 0.742500 ;
    PORT
      LAYER met3 ;
        RECT 0.000 204.040 4.000 204.640 ;
    END
  END in_data[723]
  PIN in_data[724]
    DIRECTION INPUT ;
    USE SIGNAL ;
    ANTENNAGATEAREA 0.426000 ;
    PORT
      LAYER met3 ;
        RECT 0.000 510.040 4.000 510.640 ;
    END
  END in_data[724]
  PIN in_data[725]
    DIRECTION INPUT ;
    USE SIGNAL ;
    ANTENNAGATEAREA 0.426000 ;
    PORT
      LAYER met2 ;
        RECT 830.850 0.000 831.130 4.000 ;
    END
  END in_data[725]
  PIN in_data[726]
    DIRECTION INPUT ;
    USE SIGNAL ;
    ANTENNAGATEAREA 0.852000 ;
    PORT
      LAYER met3 ;
        RECT 1296.000 0.040 1300.000 0.640 ;
    END
  END in_data[726]
  PIN in_data[727]
    DIRECTION INPUT ;
    USE SIGNAL ;
    ANTENNAGATEAREA 0.426000 ;
    PORT
      LAYER met3 ;
        RECT 0.000 669.840 4.000 670.440 ;
    END
  END in_data[727]
  PIN in_data[728]
    DIRECTION INPUT ;
    USE SIGNAL ;
    ANTENNAGATEAREA 0.742500 ;
    PORT
      LAYER met2 ;
        RECT 283.450 0.000 283.730 4.000 ;
    END
  END in_data[728]
  PIN in_data[729]
    DIRECTION INPUT ;
    USE SIGNAL ;
    ANTENNAGATEAREA 0.742500 ;
    PORT
      LAYER met3 ;
        RECT 1296.000 1132.240 1300.000 1132.840 ;
    END
  END in_data[729]
  PIN in_data[72]
    DIRECTION INPUT ;
    USE SIGNAL ;
    ANTENNAGATEAREA 0.742500 ;
    PORT
      LAYER met3 ;
        RECT 0.000 1234.240 4.000 1234.840 ;
    END
  END in_data[72]
  PIN in_data[730]
    DIRECTION INPUT ;
    USE SIGNAL ;
    ANTENNAGATEAREA 0.742500 ;
    PORT
      LAYER met2 ;
        RECT 248.030 1296.000 248.310 1300.000 ;
    END
  END in_data[730]
  PIN in_data[731]
    DIRECTION INPUT ;
    USE SIGNAL ;
    ANTENNAGATEAREA 0.426000 ;
    PORT
      LAYER met3 ;
        RECT 1296.000 697.040 1300.000 697.640 ;
    END
  END in_data[731]
  PIN in_data[732]
    DIRECTION INPUT ;
    USE SIGNAL ;
    ANTENNAGATEAREA 0.852000 ;
    PORT
      LAYER met3 ;
        RECT 0.000 1271.640 4.000 1272.240 ;
    END
  END in_data[732]
  PIN in_data[733]
    DIRECTION INPUT ;
    USE SIGNAL ;
    ANTENNAGATEAREA 0.742500 ;
    PORT
      LAYER met3 ;
        RECT 1296.000 306.040 1300.000 306.640 ;
    END
  END in_data[733]
  PIN in_data[734]
    DIRECTION INPUT ;
    USE SIGNAL ;
    ANTENNAGATEAREA 0.426000 ;
    PORT
      LAYER met3 ;
        RECT 1296.000 465.840 1300.000 466.440 ;
    END
  END in_data[734]
  PIN in_data[735]
    DIRECTION INPUT ;
    USE SIGNAL ;
    ANTENNAGATEAREA 0.742500 ;
    PORT
      LAYER met3 ;
        RECT 0.000 3.440 4.000 4.040 ;
    END
  END in_data[735]
  PIN in_data[736]
    DIRECTION INPUT ;
    USE SIGNAL ;
    ANTENNAGATEAREA 0.426000 ;
    PORT
      LAYER met2 ;
        RECT 512.070 0.000 512.350 4.000 ;
    END
  END in_data[736]
  PIN in_data[737]
    DIRECTION INPUT ;
    USE SIGNAL ;
    ANTENNAGATEAREA 0.742500 ;
    PORT
      LAYER met3 ;
        RECT 0.000 10.240 4.000 10.840 ;
    END
  END in_data[737]
  PIN in_data[738]
    DIRECTION INPUT ;
    USE SIGNAL ;
    ANTENNAGATEAREA 0.495000 ;
    PORT
      LAYER met3 ;
        RECT 0.000 826.240 4.000 826.840 ;
    END
  END in_data[738]
  PIN in_data[739]
    DIRECTION INPUT ;
    USE SIGNAL ;
    ANTENNAGATEAREA 0.742500 ;
    PORT
      LAYER met3 ;
        RECT 1296.000 1030.240 1300.000 1030.840 ;
    END
  END in_data[739]
  PIN in_data[73]
    DIRECTION INPUT ;
    USE SIGNAL ;
    ANTENNAGATEAREA 0.247500 ;
    PORT
      LAYER met2 ;
        RECT 566.810 1296.000 567.090 1300.000 ;
    END
  END in_data[73]
  PIN in_data[740]
    DIRECTION INPUT ;
    USE SIGNAL ;
    ANTENNAGATEAREA 0.742500 ;
    PORT
      LAYER met2 ;
        RECT 1236.570 0.000 1236.850 4.000 ;
    END
  END in_data[740]
  PIN in_data[741]
    DIRECTION INPUT ;
    USE SIGNAL ;
    ANTENNAGATEAREA 0.742500 ;
    PORT
      LAYER met3 ;
        RECT 0.000 1088.040 4.000 1088.640 ;
    END
  END in_data[741]
  PIN in_data[742]
    DIRECTION INPUT ;
    USE SIGNAL ;
    ANTENNAGATEAREA 0.742500 ;
    PORT
      LAYER met2 ;
        RECT 116.010 0.000 116.290 4.000 ;
    END
  END in_data[742]
  PIN in_data[743]
    DIRECTION INPUT ;
    USE SIGNAL ;
    ANTENNAGATEAREA 0.742500 ;
    PORT
      LAYER met2 ;
        RECT 183.630 0.000 183.910 4.000 ;
    END
  END in_data[743]
  PIN in_data[744]
    DIRECTION INPUT ;
    USE SIGNAL ;
    ANTENNAGATEAREA 0.742500 ;
    PORT
      LAYER met3 ;
        RECT 1296.000 197.240 1300.000 197.840 ;
    END
  END in_data[744]
  PIN in_data[745]
    DIRECTION INPUT ;
    USE SIGNAL ;
    ANTENNAGATEAREA 0.426000 ;
    PORT
      LAYER met3 ;
        RECT 1296.000 547.440 1300.000 548.040 ;
    END
  END in_data[745]
  PIN in_data[746]
    DIRECTION INPUT ;
    USE SIGNAL ;
    ANTENNAGATEAREA 0.495000 ;
    PORT
      LAYER met3 ;
        RECT 0.000 758.240 4.000 758.840 ;
    END
  END in_data[746]
  PIN in_data[747]
    DIRECTION INPUT ;
    USE SIGNAL ;
    ANTENNAGATEAREA 0.742500 ;
    PORT
      LAYER met3 ;
        RECT 1296.000 962.240 1300.000 962.840 ;
    END
  END in_data[747]
  PIN in_data[748]
    DIRECTION INPUT ;
    USE SIGNAL ;
    ANTENNAGATEAREA 0.495000 ;
    PORT
      LAYER met2 ;
        RECT 969.310 0.000 969.590 4.000 ;
    END
  END in_data[748]
  PIN in_data[749]
    DIRECTION INPUT ;
    USE SIGNAL ;
    ANTENNAGATEAREA 0.742500 ;
    PORT
      LAYER met2 ;
        RECT 132.110 0.000 132.390 4.000 ;
    END
  END in_data[749]
  PIN in_data[74]
    DIRECTION INPUT ;
    USE SIGNAL ;
    ANTENNAGATEAREA 0.742500 ;
    PORT
      LAYER met2 ;
        RECT 190.070 1296.000 190.350 1300.000 ;
    END
  END in_data[74]
  PIN in_data[750]
    DIRECTION INPUT ;
    USE SIGNAL ;
    ANTENNAGATEAREA 0.495000 ;
    PORT
      LAYER met2 ;
        RECT 1036.930 0.000 1037.210 4.000 ;
    END
  END in_data[750]
  PIN in_data[751]
    DIRECTION INPUT ;
    USE SIGNAL ;
    ANTENNAGATEAREA 0.426000 ;
    PORT
      LAYER met2 ;
        RECT 537.830 0.000 538.110 4.000 ;
    END
  END in_data[751]
  PIN in_data[752]
    DIRECTION INPUT ;
    USE SIGNAL ;
    ANTENNAGATEAREA 0.742500 ;
    PORT
      LAYER met2 ;
        RECT 1101.330 0.000 1101.610 4.000 ;
    END
  END in_data[752]
  PIN in_data[753]
    DIRECTION INPUT ;
    USE SIGNAL ;
    ANTENNAGATEAREA 0.742500 ;
    PORT
      LAYER met2 ;
        RECT 112.790 1296.000 113.070 1300.000 ;
    END
  END in_data[753]
  PIN in_data[754]
    DIRECTION INPUT ;
    USE SIGNAL ;
    ANTENNAGATEAREA 0.247500 ;
    PORT
      LAYER met3 ;
        RECT 1296.000 554.240 1300.000 554.840 ;
    END
  END in_data[754]
  PIN in_data[755]
    DIRECTION INPUT ;
    USE SIGNAL ;
    ANTENNAGATEAREA 0.742500 ;
    PORT
      LAYER met2 ;
        RECT 1271.990 1296.000 1272.270 1300.000 ;
    END
  END in_data[755]
  PIN in_data[756]
    DIRECTION INPUT ;
    USE SIGNAL ;
    ANTENNAGATEAREA 0.852000 ;
    PORT
      LAYER met3 ;
        RECT 0.000 20.440 4.000 21.040 ;
    END
  END in_data[756]
  PIN in_data[757]
    DIRECTION INPUT ;
    USE SIGNAL ;
    ANTENNAGATEAREA 0.426000 ;
    PORT
      LAYER met2 ;
        RECT 908.130 0.000 908.410 4.000 ;
    END
  END in_data[757]
  PIN in_data[758]
    DIRECTION INPUT ;
    USE SIGNAL ;
    ANTENNAGATEAREA 0.742500 ;
    PORT
      LAYER met2 ;
        RECT 277.010 1296.000 277.290 1300.000 ;
    END
  END in_data[758]
  PIN in_data[759]
    DIRECTION INPUT ;
    USE SIGNAL ;
    ANTENNAGATEAREA 0.495000 ;
    PORT
      LAYER met2 ;
        RECT 933.890 0.000 934.170 4.000 ;
    END
  END in_data[759]
  PIN in_data[75]
    DIRECTION INPUT ;
    USE SIGNAL ;
    ANTENNAGATEAREA 0.495000 ;
    PORT
      LAYER met2 ;
        RECT 235.150 1296.000 235.430 1300.000 ;
    END
  END in_data[75]
  PIN in_data[760]
    DIRECTION INPUT ;
    USE SIGNAL ;
    ANTENNAGATEAREA 0.742500 ;
    PORT
      LAYER met2 ;
        RECT 238.370 0.000 238.650 4.000 ;
    END
  END in_data[760]
  PIN in_data[761]
    DIRECTION INPUT ;
    USE SIGNAL ;
    ANTENNAGATEAREA 0.852000 ;
    PORT
      LAYER met2 ;
        RECT 9.750 1296.000 10.030 1300.000 ;
    END
  END in_data[761]
  PIN in_data[762]
    DIRECTION INPUT ;
    USE SIGNAL ;
    ANTENNAGATEAREA 0.742500 ;
    PORT
      LAYER met3 ;
        RECT 1296.000 207.440 1300.000 208.040 ;
    END
  END in_data[762]
  PIN in_data[763]
    DIRECTION INPUT ;
    USE SIGNAL ;
    ANTENNAGATEAREA 0.742500 ;
    PORT
      LAYER met3 ;
        RECT 0.000 1125.440 4.000 1126.040 ;
    END
  END in_data[763]
  PIN in_data[764]
    DIRECTION INPUT ;
    USE SIGNAL ;
    ANTENNAGATEAREA 0.495000 ;
    PORT
      LAYER met3 ;
        RECT 1296.000 822.840 1300.000 823.440 ;
    END
  END in_data[764]
  PIN in_data[765]
    DIRECTION INPUT ;
    USE SIGNAL ;
    ANTENNAGATEAREA 0.495000 ;
    PORT
      LAYER met3 ;
        RECT 0.000 550.840 4.000 551.440 ;
    END
  END in_data[765]
  PIN in_data[766]
    DIRECTION INPUT ;
    USE SIGNAL ;
    ANTENNAGATEAREA 0.426000 ;
    PORT
      LAYER met2 ;
        RECT 814.750 0.000 815.030 4.000 ;
    END
  END in_data[766]
  PIN in_data[767]
    DIRECTION INPUT ;
    USE SIGNAL ;
    ANTENNAGATEAREA 0.495000 ;
    PORT
      LAYER met3 ;
        RECT 0.000 350.240 4.000 350.840 ;
    END
  END in_data[767]
  PIN in_data[768]
    DIRECTION INPUT ;
    USE SIGNAL ;
    ANTENNAGATEAREA 0.852000 ;
    PORT
      LAYER met2 ;
        RECT 29.070 1296.000 29.350 1300.000 ;
    END
  END in_data[768]
  PIN in_data[769]
    DIRECTION INPUT ;
    USE SIGNAL ;
    ANTENNAGATEAREA 0.742500 ;
    PORT
      LAYER met3 ;
        RECT 0.000 948.640 4.000 949.240 ;
    END
  END in_data[769]
  PIN in_data[76]
    DIRECTION INPUT ;
    USE SIGNAL ;
    ANTENNAGATEAREA 0.742500 ;
    PORT
      LAYER met3 ;
        RECT 0.000 1122.040 4.000 1122.640 ;
    END
  END in_data[76]
  PIN in_data[770]
    DIRECTION INPUT ;
    USE SIGNAL ;
    ANTENNAGATEAREA 0.742500 ;
    PORT
      LAYER met2 ;
        RECT 1265.550 0.000 1265.830 4.000 ;
    END
  END in_data[770]
  PIN in_data[771]
    DIRECTION INPUT ;
    USE SIGNAL ;
    ANTENNAGATEAREA 0.426000 ;
    PORT
      LAYER met2 ;
        RECT 1011.170 0.000 1011.450 4.000 ;
    END
  END in_data[771]
  PIN in_data[772]
    DIRECTION INPUT ;
    USE SIGNAL ;
    ANTENNAGATEAREA 0.247500 ;
    PORT
      LAYER met2 ;
        RECT 447.670 0.000 447.950 4.000 ;
    END
  END in_data[772]
  PIN in_data[773]
    DIRECTION INPUT ;
    USE SIGNAL ;
    ANTENNAGATEAREA 0.742500 ;
    PORT
      LAYER met3 ;
        RECT 0.000 795.640 4.000 796.240 ;
    END
  END in_data[773]
  PIN in_data[774]
    DIRECTION INPUT ;
    USE SIGNAL ;
    ANTENNAGATEAREA 0.247500 ;
    PORT
      LAYER met2 ;
        RECT 837.290 0.000 837.570 4.000 ;
    END
  END in_data[774]
  PIN in_data[775]
    DIRECTION INPUT ;
    USE SIGNAL ;
    ANTENNAGATEAREA 0.495000 ;
    PORT
      LAYER met3 ;
        RECT 0.000 278.840 4.000 279.440 ;
    END
  END in_data[775]
  PIN in_data[776]
    DIRECTION INPUT ;
    USE SIGNAL ;
    ANTENNAGATEAREA 0.495000 ;
    PORT
      LAYER met3 ;
        RECT 1296.000 295.840 1300.000 296.440 ;
    END
  END in_data[776]
  PIN in_data[777]
    DIRECTION INPUT ;
    USE SIGNAL ;
    ANTENNAGATEAREA 0.495000 ;
    PORT
      LAYER met3 ;
        RECT 1296.000 765.040 1300.000 765.640 ;
    END
  END in_data[777]
  PIN in_data[778]
    DIRECTION INPUT ;
    USE SIGNAL ;
    ANTENNAGATEAREA 0.495000 ;
    PORT
      LAYER met3 ;
        RECT 1296.000 673.240 1300.000 673.840 ;
    END
  END in_data[778]
  PIN in_data[779]
    DIRECTION INPUT ;
    USE SIGNAL ;
    ANTENNAGATEAREA 0.247500 ;
    PORT
      LAYER met2 ;
        RECT 624.770 0.000 625.050 4.000 ;
    END
  END in_data[779]
  PIN in_data[77]
    DIRECTION INPUT ;
    USE SIGNAL ;
    ANTENNAGATEAREA 0.852000 ;
    PORT
      LAYER met2 ;
        RECT 22.630 0.000 22.910 4.000 ;
    END
  END in_data[77]
  PIN in_data[780]
    DIRECTION INPUT ;
    USE SIGNAL ;
    ANTENNAGATEAREA 0.742500 ;
    PORT
      LAYER met2 ;
        RECT 1159.290 0.000 1159.570 4.000 ;
    END
  END in_data[780]
  PIN in_data[781]
    DIRECTION INPUT ;
    USE SIGNAL ;
    ANTENNAGATEAREA 0.495000 ;
    PORT
      LAYER met2 ;
        RECT 544.270 1296.000 544.550 1300.000 ;
    END
  END in_data[781]
  PIN in_data[782]
    DIRECTION INPUT ;
    USE SIGNAL ;
    ANTENNAGATEAREA 0.742500 ;
    PORT
      LAYER met3 ;
        RECT 1296.000 47.640 1300.000 48.240 ;
    END
  END in_data[782]
  PIN in_data[783]
    DIRECTION INPUT ;
    USE SIGNAL ;
    ANTENNAGATEAREA 0.426000 ;
    PORT
      LAYER met2 ;
        RECT 698.830 1296.000 699.110 1300.000 ;
    END
  END in_data[783]
  PIN in_data[784]
    DIRECTION INPUT ;
    USE SIGNAL ;
    ANTENNAGATEAREA 0.742500 ;
    PORT
      LAYER met3 ;
        RECT 0.000 142.840 4.000 143.440 ;
    END
  END in_data[784]
  PIN in_data[785]
    DIRECTION INPUT ;
    USE SIGNAL ;
    ANTENNAGATEAREA 0.426000 ;
    PORT
      LAYER met3 ;
        RECT 1296.000 357.040 1300.000 357.640 ;
    END
  END in_data[785]
  PIN in_data[786]
    DIRECTION INPUT ;
    USE SIGNAL ;
    ANTENNAGATEAREA 0.742500 ;
    PORT
      LAYER met3 ;
        RECT 0.000 897.640 4.000 898.240 ;
    END
  END in_data[786]
  PIN in_data[787]
    DIRECTION INPUT ;
    USE SIGNAL ;
    ANTENNAGATEAREA 0.247500 ;
    PORT
      LAYER met2 ;
        RECT 875.930 0.000 876.210 4.000 ;
    END
  END in_data[787]
  PIN in_data[788]
    DIRECTION INPUT ;
    USE SIGNAL ;
    ANTENNAGATEAREA 0.742500 ;
    PORT
      LAYER met3 ;
        RECT 0.000 139.440 4.000 140.040 ;
    END
  END in_data[788]
  PIN in_data[789]
    DIRECTION INPUT ;
    USE SIGNAL ;
    ANTENNAGATEAREA 0.426000 ;
    PORT
      LAYER met2 ;
        RECT 418.690 0.000 418.970 4.000 ;
    END
  END in_data[789]
  PIN in_data[78]
    DIRECTION INPUT ;
    USE SIGNAL ;
    ANTENNAGATEAREA 0.495000 ;
    PORT
      LAYER met2 ;
        RECT 328.530 1296.000 328.810 1300.000 ;
    END
  END in_data[78]
  PIN in_data[790]
    DIRECTION INPUT ;
    USE SIGNAL ;
    ANTENNAGATEAREA 0.742500 ;
    PORT
      LAYER met2 ;
        RECT 1226.910 0.000 1227.190 4.000 ;
    END
  END in_data[790]
  PIN in_data[791]
    DIRECTION INPUT ;
    USE SIGNAL ;
    ANTENNAGATEAREA 0.742500 ;
    PORT
      LAYER met3 ;
        RECT 1296.000 81.640 1300.000 82.240 ;
    END
  END in_data[791]
  PIN in_data[792]
    DIRECTION INPUT ;
    USE SIGNAL ;
    ANTENNAGATEAREA 0.742500 ;
    PORT
      LAYER met2 ;
        RECT 357.510 1296.000 357.790 1300.000 ;
    END
  END in_data[792]
  PIN in_data[793]
    DIRECTION INPUT ;
    USE SIGNAL ;
    ANTENNAGATEAREA 0.247500 ;
    PORT
      LAYER met2 ;
        RECT 466.990 0.000 467.270 4.000 ;
    END
  END in_data[793]
  PIN in_data[794]
    DIRECTION INPUT ;
    USE SIGNAL ;
    ANTENNAGATEAREA 0.426000 ;
    PORT
      LAYER met2 ;
        RECT 695.610 1296.000 695.890 1300.000 ;
    END
  END in_data[794]
  PIN in_data[795]
    DIRECTION INPUT ;
    USE SIGNAL ;
    ANTENNAGATEAREA 0.742500 ;
    PORT
      LAYER met2 ;
        RECT 1262.330 0.000 1262.610 4.000 ;
    END
  END in_data[795]
  PIN in_data[796]
    DIRECTION INPUT ;
    USE SIGNAL ;
    ANTENNAGATEAREA 0.742500 ;
    PORT
      LAYER met3 ;
        RECT 1296.000 843.240 1300.000 843.840 ;
    END
  END in_data[796]
  PIN in_data[797]
    DIRECTION INPUT ;
    USE SIGNAL ;
    ANTENNAGATEAREA 0.742500 ;
    PORT
      LAYER met2 ;
        RECT 386.490 1296.000 386.770 1300.000 ;
    END
  END in_data[797]
  PIN in_data[798]
    DIRECTION INPUT ;
    USE SIGNAL ;
    ANTENNAGATEAREA 0.426000 ;
    PORT
      LAYER met3 ;
        RECT 0.000 472.640 4.000 473.240 ;
    END
  END in_data[798]
  PIN in_data[799]
    DIRECTION INPUT ;
    USE SIGNAL ;
    ANTENNAGATEAREA 0.426000 ;
    PORT
      LAYER met3 ;
        RECT 1296.000 346.840 1300.000 347.440 ;
    END
  END in_data[799]
  PIN in_data[79]
    DIRECTION INPUT ;
    USE SIGNAL ;
    ANTENNAGATEAREA 0.426000 ;
    PORT
      LAYER met2 ;
        RECT 727.810 0.000 728.090 4.000 ;
    END
  END in_data[79]
  PIN in_data[7]
    DIRECTION INPUT ;
    USE SIGNAL ;
    ANTENNAGATEAREA 0.495000 ;
    PORT
      LAYER met2 ;
        RECT 856.610 0.000 856.890 4.000 ;
    END
  END in_data[7]
  PIN in_data[800]
    DIRECTION INPUT ;
    USE SIGNAL ;
    ANTENNAGATEAREA 0.742500 ;
    PORT
      LAYER met3 ;
        RECT 0.000 74.840 4.000 75.440 ;
    END
  END in_data[800]
  PIN in_data[801]
    DIRECTION INPUT ;
    USE SIGNAL ;
    ANTENNAGATEAREA 0.426000 ;
    PORT
      LAYER met3 ;
        RECT 0.000 547.440 4.000 548.040 ;
    END
  END in_data[801]
  PIN in_data[802]
    DIRECTION INPUT ;
    USE SIGNAL ;
    ANTENNAGATEAREA 0.742500 ;
    PORT
      LAYER met2 ;
        RECT 399.370 1296.000 399.650 1300.000 ;
    END
  END in_data[802]
  PIN in_data[803]
    DIRECTION INPUT ;
    USE SIGNAL ;
    ANTENNAGATEAREA 0.426000 ;
    PORT
      LAYER met2 ;
        RECT 415.470 0.000 415.750 4.000 ;
    END
  END in_data[803]
  PIN in_data[804]
    DIRECTION INPUT ;
    USE SIGNAL ;
    ANTENNAGATEAREA 0.852000 ;
    PORT
      LAYER met3 ;
        RECT 1296.000 1268.240 1300.000 1268.840 ;
    END
  END in_data[804]
  PIN in_data[805]
    DIRECTION INPUT ;
    USE SIGNAL ;
    ANTENNAGATEAREA 0.742500 ;
    PORT
      LAYER met2 ;
        RECT 1162.510 0.000 1162.790 4.000 ;
    END
  END in_data[805]
  PIN in_data[806]
    DIRECTION INPUT ;
    USE SIGNAL ;
    ANTENNAGATEAREA 0.742500 ;
    PORT
      LAYER met3 ;
        RECT 0.000 975.840 4.000 976.440 ;
    END
  END in_data[806]
  PIN in_data[807]
    DIRECTION INPUT ;
    USE SIGNAL ;
    ANTENNAGATEAREA 0.852000 ;
    PORT
      LAYER met3 ;
        RECT 1296.000 1234.240 1300.000 1234.840 ;
    END
  END in_data[807]
  PIN in_data[808]
    DIRECTION INPUT ;
    USE SIGNAL ;
    ANTENNAGATEAREA 0.742500 ;
    PORT
      LAYER met2 ;
        RECT 144.990 1296.000 145.270 1300.000 ;
    END
  END in_data[808]
  PIN in_data[809]
    DIRECTION INPUT ;
    USE SIGNAL ;
    ANTENNAGATEAREA 0.742500 ;
    PORT
      LAYER met2 ;
        RECT 338.190 1296.000 338.470 1300.000 ;
    END
  END in_data[809]
  PIN in_data[80]
    DIRECTION INPUT ;
    USE SIGNAL ;
    ANTENNAGATEAREA 0.426000 ;
    PORT
      LAYER met2 ;
        RECT 640.870 0.000 641.150 4.000 ;
    END
  END in_data[80]
  PIN in_data[810]
    DIRECTION INPUT ;
    USE SIGNAL ;
    ANTENNAGATEAREA 0.742500 ;
    PORT
      LAYER met2 ;
        RECT 1065.910 1296.000 1066.190 1300.000 ;
    END
  END in_data[810]
  PIN in_data[811]
    DIRECTION INPUT ;
    USE SIGNAL ;
    ANTENNAGATEAREA 0.247500 ;
    PORT
      LAYER met3 ;
        RECT 0.000 557.640 4.000 558.240 ;
    END
  END in_data[811]
  PIN in_data[812]
    DIRECTION INPUT ;
    USE SIGNAL ;
    ANTENNAGATEAREA 0.742500 ;
    PORT
      LAYER met3 ;
        RECT 1296.000 1149.240 1300.000 1149.840 ;
    END
  END in_data[812]
  PIN in_data[813]
    DIRECTION INPUT ;
    USE SIGNAL ;
    ANTENNAGATEAREA 0.495000 ;
    PORT
      LAYER met2 ;
        RECT 302.770 0.000 303.050 4.000 ;
    END
  END in_data[813]
  PIN in_data[814]
    DIRECTION INPUT ;
    USE SIGNAL ;
    ANTENNAGATEAREA 0.852000 ;
    PORT
      LAYER met2 ;
        RECT 58.050 1296.000 58.330 1300.000 ;
    END
  END in_data[814]
  PIN in_data[815]
    DIRECTION INPUT ;
    USE SIGNAL ;
    ANTENNAGATEAREA 0.426000 ;
    PORT
      LAYER met2 ;
        RECT 914.570 0.000 914.850 4.000 ;
    END
  END in_data[815]
  PIN in_data[816]
    DIRECTION INPUT ;
    USE SIGNAL ;
    ANTENNAGATEAREA 0.426000 ;
    PORT
      LAYER met2 ;
        RECT 811.530 0.000 811.810 4.000 ;
    END
  END in_data[816]
  PIN in_data[817]
    DIRECTION INPUT ;
    USE SIGNAL ;
    ANTENNAGATEAREA 0.495000 ;
    PORT
      LAYER met2 ;
        RECT 798.650 1296.000 798.930 1300.000 ;
    END
  END in_data[817]
  PIN in_data[818]
    DIRECTION INPUT ;
    USE SIGNAL ;
    ANTENNAGATEAREA 0.742500 ;
    PORT
      LAYER met3 ;
        RECT 1296.000 914.640 1300.000 915.240 ;
    END
  END in_data[818]
  PIN in_data[819]
    DIRECTION INPUT ;
    USE SIGNAL ;
    ANTENNAGATEAREA 0.495000 ;
    PORT
      LAYER met3 ;
        RECT 1296.000 367.240 1300.000 367.840 ;
    END
  END in_data[819]
  PIN in_data[81]
    DIRECTION INPUT ;
    USE SIGNAL ;
    ANTENNAGATEAREA 0.742500 ;
    PORT
      LAYER met3 ;
        RECT 1296.000 1200.240 1300.000 1200.840 ;
    END
  END in_data[81]
  PIN in_data[820]
    DIRECTION INPUT ;
    USE SIGNAL ;
    ANTENNAGATEAREA 0.495000 ;
    PORT
      LAYER met2 ;
        RECT 1001.510 0.000 1001.790 4.000 ;
    END
  END in_data[820]
  PIN in_data[821]
    DIRECTION INPUT ;
    USE SIGNAL ;
    ANTENNAGATEAREA 0.247500 ;
    PORT
      LAYER met2 ;
        RECT 560.370 0.000 560.650 4.000 ;
    END
  END in_data[821]
  PIN in_data[822]
    DIRECTION INPUT ;
    USE SIGNAL ;
    ANTENNAGATEAREA 0.742500 ;
    PORT
      LAYER met2 ;
        RECT 161.090 1296.000 161.370 1300.000 ;
    END
  END in_data[822]
  PIN in_data[823]
    DIRECTION INPUT ;
    USE SIGNAL ;
    ANTENNAGATEAREA 0.495000 ;
    PORT
      LAYER met3 ;
        RECT 0.000 887.440 4.000 888.040 ;
    END
  END in_data[823]
  PIN in_data[824]
    DIRECTION INPUT ;
    USE SIGNAL ;
    ANTENNAGATEAREA 0.495000 ;
    PORT
      LAYER met3 ;
        RECT 0.000 408.040 4.000 408.640 ;
    END
  END in_data[824]
  PIN in_data[825]
    DIRECTION INPUT ;
    USE SIGNAL ;
    ANTENNAGATEAREA 0.742500 ;
    PORT
      LAYER met3 ;
        RECT 1296.000 1040.440 1300.000 1041.040 ;
    END
  END in_data[825]
  PIN in_data[826]
    DIRECTION INPUT ;
    USE SIGNAL ;
    ANTENNAGATEAREA 0.495000 ;
    PORT
      LAYER met3 ;
        RECT 0.000 741.240 4.000 741.840 ;
    END
  END in_data[826]
  PIN in_data[827]
    DIRECTION INPUT ;
    USE SIGNAL ;
    ANTENNAGATEAREA 0.426000 ;
    PORT
      LAYER met3 ;
        RECT 1296.000 666.440 1300.000 667.040 ;
    END
  END in_data[827]
  PIN in_data[828]
    DIRECTION INPUT ;
    USE SIGNAL ;
    ANTENNAGATEAREA 0.852000 ;
    PORT
      LAYER met2 ;
        RECT 1236.570 1296.000 1236.850 1300.000 ;
    END
  END in_data[828]
  PIN in_data[829]
    DIRECTION INPUT ;
    USE SIGNAL ;
    ANTENNAGATEAREA 0.742500 ;
    PORT
      LAYER met2 ;
        RECT 173.970 1296.000 174.250 1300.000 ;
    END
  END in_data[829]
  PIN in_data[82]
    DIRECTION INPUT ;
    USE SIGNAL ;
    ANTENNAGATEAREA 0.742500 ;
    PORT
      LAYER met2 ;
        RECT 125.670 0.000 125.950 4.000 ;
    END
  END in_data[82]
  PIN in_data[830]
    DIRECTION INPUT ;
    USE SIGNAL ;
    ANTENNAGATEAREA 0.426000 ;
    PORT
      LAYER met2 ;
        RECT 821.190 0.000 821.470 4.000 ;
    END
  END in_data[830]
  PIN in_data[831]
    DIRECTION INPUT ;
    USE SIGNAL ;
    ANTENNAGATEAREA 0.426000 ;
    PORT
      LAYER met2 ;
        RECT 438.010 0.000 438.290 4.000 ;
    END
  END in_data[831]
  PIN in_data[832]
    DIRECTION INPUT ;
    USE SIGNAL ;
    ANTENNAGATEAREA 0.426000 ;
    PORT
      LAYER met3 ;
        RECT 1296.000 527.040 1300.000 527.640 ;
    END
  END in_data[832]
  PIN in_data[833]
    DIRECTION INPUT ;
    USE SIGNAL ;
    ANTENNAGATEAREA 0.742500 ;
    PORT
      LAYER met2 ;
        RECT 99.910 0.000 100.190 4.000 ;
    END
  END in_data[833]
  PIN in_data[834]
    DIRECTION INPUT ;
    USE SIGNAL ;
    ANTENNAGATEAREA 0.426000 ;
    PORT
      LAYER met3 ;
        RECT 0.000 387.640 4.000 388.240 ;
    END
  END in_data[834]
  PIN in_data[835]
    DIRECTION INPUT ;
    USE SIGNAL ;
    ANTENNAGATEAREA 0.426000 ;
    PORT
      LAYER met3 ;
        RECT 1296.000 479.440 1300.000 480.040 ;
    END
  END in_data[835]
  PIN in_data[836]
    DIRECTION INPUT ;
    USE SIGNAL ;
    ANTENNAGATEAREA 0.742500 ;
    PORT
      LAYER met2 ;
        RECT 904.910 1296.000 905.190 1300.000 ;
    END
  END in_data[836]
  PIN in_data[837]
    DIRECTION INPUT ;
    USE SIGNAL ;
    ANTENNAGATEAREA 0.742500 ;
    PORT
      LAYER met3 ;
        RECT 1296.000 901.040 1300.000 901.640 ;
    END
  END in_data[837]
  PIN in_data[838]
    DIRECTION INPUT ;
    USE SIGNAL ;
    ANTENNAGATEAREA 0.495000 ;
    PORT
      LAYER met2 ;
        RECT 164.310 0.000 164.590 4.000 ;
    END
  END in_data[838]
  PIN in_data[839]
    DIRECTION INPUT ;
    USE SIGNAL ;
    ANTENNAGATEAREA 0.495000 ;
    PORT
      LAYER met3 ;
        RECT 1296.000 782.040 1300.000 782.640 ;
    END
  END in_data[839]
  PIN in_data[83]
    DIRECTION INPUT ;
    USE SIGNAL ;
    ANTENNAGATEAREA 0.742500 ;
    PORT
      LAYER met2 ;
        RECT 1056.250 0.000 1056.530 4.000 ;
    END
  END in_data[83]
  PIN in_data[840]
    DIRECTION INPUT ;
    USE SIGNAL ;
    ANTENNAGATEAREA 0.426000 ;
    PORT
      LAYER met3 ;
        RECT 0.000 411.440 4.000 412.040 ;
    END
  END in_data[840]
  PIN in_data[841]
    DIRECTION INPUT ;
    USE SIGNAL ;
    ANTENNAGATEAREA 0.495000 ;
    PORT
      LAYER met2 ;
        RECT 978.970 0.000 979.250 4.000 ;
    END
  END in_data[841]
  PIN in_data[842]
    DIRECTION INPUT ;
    USE SIGNAL ;
    ANTENNAGATEAREA 0.742500 ;
    PORT
      LAYER met3 ;
        RECT 1296.000 1084.640 1300.000 1085.240 ;
    END
  END in_data[842]
  PIN in_data[843]
    DIRECTION INPUT ;
    USE SIGNAL ;
    ANTENNAGATEAREA 0.742500 ;
    PORT
      LAYER met3 ;
        RECT 0.000 40.840 4.000 41.440 ;
    END
  END in_data[843]
  PIN in_data[844]
    DIRECTION INPUT ;
    USE SIGNAL ;
    ANTENNAGATEAREA 0.495000 ;
    PORT
      LAYER met2 ;
        RECT 666.630 1296.000 666.910 1300.000 ;
    END
  END in_data[844]
  PIN in_data[845]
    DIRECTION INPUT ;
    USE SIGNAL ;
    ANTENNAGATEAREA 0.247500 ;
    PORT
      LAYER met3 ;
        RECT 0.000 530.440 4.000 531.040 ;
    END
  END in_data[845]
  PIN in_data[846]
    DIRECTION INPUT ;
    USE SIGNAL ;
    ANTENNAGATEAREA 0.495000 ;
    PORT
      LAYER met3 ;
        RECT 0.000 268.640 4.000 269.240 ;
    END
  END in_data[846]
  PIN in_data[847]
    DIRECTION INPUT ;
    USE SIGNAL ;
    ANTENNAGATEAREA 0.742500 ;
    PORT
      LAYER met3 ;
        RECT 0.000 1064.240 4.000 1064.840 ;
    END
  END in_data[847]
  PIN in_data[848]
    DIRECTION INPUT ;
    USE SIGNAL ;
    ANTENNAGATEAREA 0.742500 ;
    PORT
      LAYER met3 ;
        RECT 0.000 61.240 4.000 61.840 ;
    END
  END in_data[848]
  PIN in_data[849]
    DIRECTION INPUT ;
    USE SIGNAL ;
    ANTENNAGATEAREA 0.495000 ;
    PORT
      LAYER met3 ;
        RECT 1296.000 316.240 1300.000 316.840 ;
    END
  END in_data[849]
  PIN in_data[84]
    DIRECTION INPUT ;
    USE SIGNAL ;
    ANTENNAGATEAREA 0.247500 ;
    PORT
      LAYER met3 ;
        RECT 1296.000 714.040 1300.000 714.640 ;
    END
  END in_data[84]
  PIN in_data[850]
    DIRECTION INPUT ;
    USE SIGNAL ;
    ANTENNAGATEAREA 0.742500 ;
    PORT
      LAYER met3 ;
        RECT 1296.000 1111.840 1300.000 1112.440 ;
    END
  END in_data[850]
  PIN in_data[851]
    DIRECTION INPUT ;
    USE SIGNAL ;
    ANTENNAGATEAREA 0.742500 ;
    PORT
      LAYER met2 ;
        RECT 103.130 1296.000 103.410 1300.000 ;
    END
  END in_data[851]
  PIN in_data[852]
    DIRECTION INPUT ;
    USE SIGNAL ;
    ANTENNAGATEAREA 0.742500 ;
    PORT
      LAYER met2 ;
        RECT 1152.850 0.000 1153.130 4.000 ;
    END
  END in_data[852]
  PIN in_data[853]
    DIRECTION INPUT ;
    USE SIGNAL ;
    ANTENNAGATEAREA 0.742500 ;
    PORT
      LAYER met2 ;
        RECT 1149.630 1296.000 1149.910 1300.000 ;
    END
  END in_data[853]
  PIN in_data[854]
    DIRECTION INPUT ;
    USE SIGNAL ;
    ANTENNAGATEAREA 0.852000 ;
    PORT
      LAYER met3 ;
        RECT 1296.000 1258.040 1300.000 1258.640 ;
    END
  END in_data[854]
  PIN in_data[855]
    DIRECTION INPUT ;
    USE SIGNAL ;
    ANTENNAGATEAREA 0.495000 ;
    PORT
      LAYER met2 ;
        RECT 753.570 1296.000 753.850 1300.000 ;
    END
  END in_data[855]
  PIN in_data[856]
    DIRECTION INPUT ;
    USE SIGNAL ;
    ANTENNAGATEAREA 0.742500 ;
    PORT
      LAYER met2 ;
        RECT 1017.610 1296.000 1017.890 1300.000 ;
    END
  END in_data[856]
  PIN in_data[857]
    DIRECTION INPUT ;
    USE SIGNAL ;
    ANTENNAGATEAREA 0.742500 ;
    PORT
      LAYER met3 ;
        RECT 1296.000 78.240 1300.000 78.840 ;
    END
  END in_data[857]
  PIN in_data[858]
    DIRECTION INPUT ;
    USE SIGNAL ;
    ANTENNAGATEAREA 0.495000 ;
    PORT
      LAYER met3 ;
        RECT 0.000 292.440 4.000 293.040 ;
    END
  END in_data[858]
  PIN in_data[859]
    DIRECTION INPUT ;
    USE SIGNAL ;
    ANTENNAGATEAREA 0.742500 ;
    PORT
      LAYER met3 ;
        RECT 1296.000 17.040 1300.000 17.640 ;
    END
  END in_data[859]
  PIN in_data[85]
    DIRECTION INPUT ;
    USE SIGNAL ;
    ANTENNAGATEAREA 0.742500 ;
    PORT
      LAYER met3 ;
        RECT 1296.000 285.640 1300.000 286.240 ;
    END
  END in_data[85]
  PIN in_data[860]
    DIRECTION INPUT ;
    USE SIGNAL ;
    ANTENNAGATEAREA 0.495000 ;
    PORT
      LAYER met2 ;
        RECT 267.350 0.000 267.630 4.000 ;
    END
  END in_data[860]
  PIN in_data[861]
    DIRECTION INPUT ;
    USE SIGNAL ;
    ANTENNAGATEAREA 0.426000 ;
    PORT
      LAYER met2 ;
        RECT 405.810 0.000 406.090 4.000 ;
    END
  END in_data[861]
  PIN in_data[862]
    DIRECTION INPUT ;
    USE SIGNAL ;
    ANTENNAGATEAREA 0.742500 ;
    PORT
      LAYER met3 ;
        RECT 1296.000 112.240 1300.000 112.840 ;
    END
  END in_data[862]
  PIN in_data[863]
    DIRECTION INPUT ;
    USE SIGNAL ;
    ANTENNAGATEAREA 0.426000 ;
    PORT
      LAYER met3 ;
        RECT 1296.000 646.040 1300.000 646.640 ;
    END
  END in_data[863]
  PIN in_data[864]
    DIRECTION INPUT ;
    USE SIGNAL ;
    ANTENNAGATEAREA 0.426000 ;
    PORT
      LAYER met3 ;
        RECT 0.000 360.440 4.000 361.040 ;
    END
  END in_data[864]
  PIN in_data[865]
    DIRECTION INPUT ;
    USE SIGNAL ;
    ANTENNAGATEAREA 0.742500 ;
    PORT
      LAYER met2 ;
        RECT 199.730 1296.000 200.010 1300.000 ;
    END
  END in_data[865]
  PIN in_data[866]
    DIRECTION INPUT ;
    USE SIGNAL ;
    ANTENNAGATEAREA 0.742500 ;
    PORT
      LAYER met2 ;
        RECT 135.330 1296.000 135.610 1300.000 ;
    END
  END in_data[866]
  PIN in_data[867]
    DIRECTION INPUT ;
    USE SIGNAL ;
    ANTENNAGATEAREA 0.742500 ;
    PORT
      LAYER met3 ;
        RECT 0.000 1207.040 4.000 1207.640 ;
    END
  END in_data[867]
  PIN in_data[868]
    DIRECTION INPUT ;
    USE SIGNAL ;
    ANTENNAGATEAREA 0.247500 ;
    PORT
      LAYER met2 ;
        RECT 492.750 0.000 493.030 4.000 ;
    END
  END in_data[868]
  PIN in_data[869]
    DIRECTION INPUT ;
    USE SIGNAL ;
    ANTENNAGATEAREA 0.742500 ;
    PORT
      LAYER met2 ;
        RECT 1036.930 1296.000 1037.210 1300.000 ;
    END
  END in_data[869]
  PIN in_data[86]
    DIRECTION INPUT ;
    USE SIGNAL ;
    ANTENNAGATEAREA 0.742500 ;
    PORT
      LAYER met3 ;
        RECT 1296.000 255.040 1300.000 255.640 ;
    END
  END in_data[86]
  PIN in_data[870]
    DIRECTION INPUT ;
    USE SIGNAL ;
    ANTENNAGATEAREA 0.742500 ;
    PORT
      LAYER met3 ;
        RECT 0.000 1135.640 4.000 1136.240 ;
    END
  END in_data[870]
  PIN in_data[871]
    DIRECTION INPUT ;
    USE SIGNAL ;
    ANTENNAGATEAREA 0.426000 ;
    PORT
      LAYER met2 ;
        RECT 315.650 0.000 315.930 4.000 ;
    END
  END in_data[871]
  PIN in_data[872]
    DIRECTION INPUT ;
    USE SIGNAL ;
    ANTENNAGATEAREA 0.990000 ;
    PORT
      LAYER met2 ;
        RECT 1217.250 1296.000 1217.530 1300.000 ;
    END
  END in_data[872]
  PIN in_data[873]
    DIRECTION INPUT ;
    USE SIGNAL ;
    ANTENNAGATEAREA 0.495000 ;
    PORT
      LAYER met2 ;
        RECT 499.190 1296.000 499.470 1300.000 ;
    END
  END in_data[873]
  PIN in_data[874]
    DIRECTION INPUT ;
    USE SIGNAL ;
    ANTENNAGATEAREA 0.495000 ;
    PORT
      LAYER met2 ;
        RECT 415.470 1296.000 415.750 1300.000 ;
    END
  END in_data[874]
  PIN in_data[875]
    DIRECTION INPUT ;
    USE SIGNAL ;
    ANTENNAGATEAREA 0.426000 ;
    PORT
      LAYER met2 ;
        RECT 676.290 1296.000 676.570 1300.000 ;
    END
  END in_data[875]
  PIN in_data[876]
    DIRECTION INPUT ;
    USE SIGNAL ;
    ANTENNAGATEAREA 0.495000 ;
    PORT
      LAYER met2 ;
        RECT 747.130 1296.000 747.410 1300.000 ;
    END
  END in_data[876]
  PIN in_data[877]
    DIRECTION INPUT ;
    USE SIGNAL ;
    ANTENNAGATEAREA 0.426000 ;
    PORT
      LAYER met3 ;
        RECT 0.000 469.240 4.000 469.840 ;
    END
  END in_data[877]
  PIN in_data[878]
    DIRECTION INPUT ;
    USE SIGNAL ;
    ANTENNAGATEAREA 0.426000 ;
    PORT
      LAYER met2 ;
        RECT 859.830 0.000 860.110 4.000 ;
    END
  END in_data[878]
  PIN in_data[879]
    DIRECTION INPUT ;
    USE SIGNAL ;
    ANTENNAGATEAREA 0.742500 ;
    PORT
      LAYER met2 ;
        RECT 286.670 1296.000 286.950 1300.000 ;
    END
  END in_data[879]
  PIN in_data[87]
    DIRECTION INPUT ;
    USE SIGNAL ;
    ANTENNAGATEAREA 0.742500 ;
    PORT
      LAYER met3 ;
        RECT 0.000 340.040 4.000 340.640 ;
    END
  END in_data[87]
  PIN in_data[880]
    DIRECTION INPUT ;
    USE SIGNAL ;
    ANTENNAGATEAREA 0.742500 ;
    PORT
      LAYER met2 ;
        RECT 19.410 0.000 19.690 4.000 ;
    END
  END in_data[880]
  PIN in_data[881]
    DIRECTION INPUT ;
    USE SIGNAL ;
    ANTENNAGATEAREA 0.742500 ;
    PORT
      LAYER met2 ;
        RECT 1275.210 0.000 1275.490 4.000 ;
    END
  END in_data[881]
  PIN in_data[882]
    DIRECTION INPUT ;
    USE SIGNAL ;
    ANTENNAGATEAREA 0.426000 ;
    PORT
      LAYER met2 ;
        RECT 866.270 0.000 866.550 4.000 ;
    END
  END in_data[882]
  PIN in_data[883]
    DIRECTION INPUT ;
    USE SIGNAL ;
    ANTENNAGATEAREA 0.426000 ;
    PORT
      LAYER met3 ;
        RECT 1296.000 448.840 1300.000 449.440 ;
    END
  END in_data[883]
  PIN in_data[884]
    DIRECTION INPUT ;
    USE SIGNAL ;
    ANTENNAGATEAREA 0.742500 ;
    PORT
      LAYER met2 ;
        RECT 450.890 1296.000 451.170 1300.000 ;
    END
  END in_data[884]
  PIN in_data[885]
    DIRECTION INPUT ;
    USE SIGNAL ;
    ANTENNAGATEAREA 0.426000 ;
    PORT
      LAYER met3 ;
        RECT 1296.000 584.840 1300.000 585.440 ;
    END
  END in_data[885]
  PIN in_data[886]
    DIRECTION INPUT ;
    USE SIGNAL ;
    ANTENNAGATEAREA 0.742500 ;
    PORT
      LAYER met3 ;
        RECT 0.000 775.240 4.000 775.840 ;
    END
  END in_data[886]
  PIN in_data[887]
    DIRECTION INPUT ;
    USE SIGNAL ;
    ANTENNAGATEAREA 0.742500 ;
    PORT
      LAYER met2 ;
        RECT 67.710 0.000 67.990 4.000 ;
    END
  END in_data[887]
  PIN in_data[888]
    DIRECTION INPUT ;
    USE SIGNAL ;
    ANTENNAGATEAREA 0.495000 ;
    PORT
      LAYER met2 ;
        RECT 325.310 0.000 325.590 4.000 ;
    END
  END in_data[888]
  PIN in_data[889]
    DIRECTION INPUT ;
    USE SIGNAL ;
    ANTENNAGATEAREA 0.247500 ;
    PORT
      LAYER met2 ;
        RECT 724.590 0.000 724.870 4.000 ;
    END
  END in_data[889]
  PIN in_data[88]
    DIRECTION INPUT ;
    USE SIGNAL ;
    ANTENNAGATEAREA 0.742500 ;
    PORT
      LAYER met2 ;
        RECT 299.550 1296.000 299.830 1300.000 ;
    END
  END in_data[88]
  PIN in_data[890]
    DIRECTION INPUT ;
    USE SIGNAL ;
    ANTENNAGATEAREA 0.742500 ;
    PORT
      LAYER met3 ;
        RECT 1296.000 6.840 1300.000 7.440 ;
    END
  END in_data[890]
  PIN in_data[891]
    DIRECTION INPUT ;
    USE SIGNAL ;
    ANTENNAGATEAREA 0.247500 ;
    PORT
      LAYER met2 ;
        RECT 621.550 0.000 621.830 4.000 ;
    END
  END in_data[891]
  PIN in_data[892]
    DIRECTION INPUT ;
    USE SIGNAL ;
    ANTENNAGATEAREA 0.742500 ;
    PORT
      LAYER met2 ;
        RECT 1217.250 0.000 1217.530 4.000 ;
    END
  END in_data[892]
  PIN in_data[893]
    DIRECTION INPUT ;
    USE SIGNAL ;
    ANTENNAGATEAREA 0.742500 ;
    PORT
      LAYER met3 ;
        RECT 1296.000 1162.840 1300.000 1163.440 ;
    END
  END in_data[893]
  PIN in_data[894]
    DIRECTION INPUT ;
    USE SIGNAL ;
    ANTENNAGATEAREA 0.742500 ;
    PORT
      LAYER met2 ;
        RECT 1146.410 1296.000 1146.690 1300.000 ;
    END
  END in_data[894]
  PIN in_data[895]
    DIRECTION INPUT ;
    USE SIGNAL ;
    ANTENNAGATEAREA 0.742500 ;
    PORT
      LAYER met2 ;
        RECT 1243.010 0.000 1243.290 4.000 ;
    END
  END in_data[895]
  PIN in_data[896]
    DIRECTION INPUT ;
    USE SIGNAL ;
    ANTENNAGATEAREA 0.742500 ;
    PORT
      LAYER met3 ;
        RECT 0.000 819.440 4.000 820.040 ;
    END
  END in_data[896]
  PIN in_data[897]
    DIRECTION INPUT ;
    USE SIGNAL ;
    ANTENNAGATEAREA 0.495000 ;
    PORT
      LAYER met3 ;
        RECT 1296.000 299.240 1300.000 299.840 ;
    END
  END in_data[897]
  PIN in_data[898]
    DIRECTION INPUT ;
    USE SIGNAL ;
    ANTENNAGATEAREA 0.852000 ;
    PORT
      LAYER met2 ;
        RECT 1223.690 1296.000 1223.970 1300.000 ;
    END
  END in_data[898]
  PIN in_data[899]
    DIRECTION INPUT ;
    USE SIGNAL ;
    ANTENNAGATEAREA 0.742500 ;
    PORT
      LAYER met3 ;
        RECT 0.000 23.840 4.000 24.440 ;
    END
  END in_data[899]
  PIN in_data[89]
    DIRECTION INPUT ;
    USE SIGNAL ;
    ANTENNAGATEAREA 0.742500 ;
    PORT
      LAYER met3 ;
        RECT 1296.000 1169.640 1300.000 1170.240 ;
    END
  END in_data[89]
  PIN in_data[8]
    DIRECTION INPUT ;
    USE SIGNAL ;
    ANTENNAGATEAREA 0.852000 ;
    PORT
      LAYER met2 ;
        RECT 1207.590 0.000 1207.870 4.000 ;
    END
  END in_data[8]
  PIN in_data[900]
    DIRECTION INPUT ;
    USE SIGNAL ;
    ANTENNAGATEAREA 0.495000 ;
    PORT
      LAYER met2 ;
        RECT 489.530 1296.000 489.810 1300.000 ;
    END
  END in_data[900]
  PIN in_data[901]
    DIRECTION INPUT ;
    USE SIGNAL ;
    ANTENNAGATEAREA 0.426000 ;
    PORT
      LAYER met3 ;
        RECT 1296.000 459.040 1300.000 459.640 ;
    END
  END in_data[901]
  PIN in_data[902]
    DIRECTION INPUT ;
    USE SIGNAL ;
    ANTENNAGATEAREA 0.742500 ;
    PORT
      LAYER met3 ;
        RECT 0.000 261.840 4.000 262.440 ;
    END
  END in_data[902]
  PIN in_data[903]
    DIRECTION INPUT ;
    USE SIGNAL ;
    ANTENNAGATEAREA 0.742500 ;
    PORT
      LAYER met3 ;
        RECT 1296.000 166.640 1300.000 167.240 ;
    END
  END in_data[903]
  PIN in_data[904]
    DIRECTION INPUT ;
    USE SIGNAL ;
    ANTENNAGATEAREA 0.495000 ;
    PORT
      LAYER met3 ;
        RECT 0.000 788.840 4.000 789.440 ;
    END
  END in_data[904]
  PIN in_data[905]
    DIRECTION INPUT ;
    USE SIGNAL ;
    ANTENNAGATEAREA 0.742500 ;
    PORT
      LAYER met2 ;
        RECT 199.730 0.000 200.010 4.000 ;
    END
  END in_data[905]
  PIN in_data[906]
    DIRECTION INPUT ;
    USE SIGNAL ;
    ANTENNAGATEAREA 0.742500 ;
    PORT
      LAYER met3 ;
        RECT 1296.000 1101.640 1300.000 1102.240 ;
    END
  END in_data[906]
  PIN in_data[907]
    DIRECTION INPUT ;
    USE SIGNAL ;
    ANTENNAGATEAREA 0.426000 ;
    PORT
      LAYER met2 ;
        RECT 879.150 0.000 879.430 4.000 ;
    END
  END in_data[907]
  PIN in_data[908]
    DIRECTION INPUT ;
    USE SIGNAL ;
    ANTENNAGATEAREA 0.742500 ;
    PORT
      LAYER met3 ;
        RECT 0.000 180.240 4.000 180.840 ;
    END
  END in_data[908]
  PIN in_data[909]
    DIRECTION INPUT ;
    USE SIGNAL ;
    ANTENNAGATEAREA 0.426000 ;
    PORT
      LAYER met2 ;
        RECT 396.150 0.000 396.430 4.000 ;
    END
  END in_data[909]
  PIN in_data[90]
    DIRECTION INPUT ;
    USE SIGNAL ;
    ANTENNAGATEAREA 0.742500 ;
    PORT
      LAYER met3 ;
        RECT 1296.000 180.240 1300.000 180.840 ;
    END
  END in_data[90]
  PIN in_data[910]
    DIRECTION INPUT ;
    USE SIGNAL ;
    ANTENNAGATEAREA 0.742500 ;
    PORT
      LAYER met3 ;
        RECT 0.000 945.240 4.000 945.840 ;
    END
  END in_data[910]
  PIN in_data[911]
    DIRECTION INPUT ;
    USE SIGNAL ;
    ANTENNAGATEAREA 0.495000 ;
    PORT
      LAYER met2 ;
        RECT 537.830 1296.000 538.110 1300.000 ;
    END
  END in_data[911]
  PIN in_data[912]
    DIRECTION INPUT ;
    USE SIGNAL ;
    ANTENNAGATEAREA 0.742500 ;
    PORT
      LAYER met2 ;
        RECT 1120.650 1296.000 1120.930 1300.000 ;
    END
  END in_data[912]
  PIN in_data[913]
    DIRECTION INPUT ;
    USE SIGNAL ;
    ANTENNAGATEAREA 0.742500 ;
    PORT
      LAYER met3 ;
        RECT 0.000 907.840 4.000 908.440 ;
    END
  END in_data[913]
  PIN in_data[914]
    DIRECTION INPUT ;
    USE SIGNAL ;
    ANTENNAGATEAREA 0.742500 ;
    PORT
      LAYER met3 ;
        RECT 0.000 1054.040 4.000 1054.640 ;
    END
  END in_data[914]
  PIN in_data[915]
    DIRECTION INPUT ;
    USE SIGNAL ;
    ANTENNAGATEAREA 0.426000 ;
    PORT
      LAYER met3 ;
        RECT 1296.000 523.640 1300.000 524.240 ;
    END
  END in_data[915]
  PIN in_data[916]
    DIRECTION INPUT ;
    USE SIGNAL ;
    ANTENNAGATEAREA 0.495000 ;
    PORT
      LAYER met3 ;
        RECT 0.000 829.640 4.000 830.240 ;
    END
  END in_data[916]
  PIN in_data[917]
    DIRECTION INPUT ;
    USE SIGNAL ;
    ANTENNAGATEAREA 0.426000 ;
    PORT
      LAYER met3 ;
        RECT 1296.000 792.240 1300.000 792.840 ;
    END
  END in_data[917]
  PIN in_data[918]
    DIRECTION INPUT ;
    USE SIGNAL ;
    ANTENNAGATEAREA 0.742500 ;
    PORT
      LAYER met2 ;
        RECT 293.110 1296.000 293.390 1300.000 ;
    END
  END in_data[918]
  PIN in_data[919]
    DIRECTION INPUT ;
    USE SIGNAL ;
    ANTENNAGATEAREA 0.852000 ;
    PORT
      LAYER met3 ;
        RECT 0.000 1285.240 4.000 1285.840 ;
    END
  END in_data[919]
  PIN in_data[91]
    DIRECTION INPUT ;
    USE SIGNAL ;
    ANTENNAGATEAREA 0.426000 ;
    PORT
      LAYER met3 ;
        RECT 0.000 666.440 4.000 667.040 ;
    END
  END in_data[91]
  PIN in_data[920]
    DIRECTION INPUT ;
    USE SIGNAL ;
    ANTENNAGATEAREA 0.742500 ;
    PORT
      LAYER met2 ;
        RECT 141.770 0.000 142.050 4.000 ;
    END
  END in_data[920]
  PIN in_data[921]
    DIRECTION INPUT ;
    USE SIGNAL ;
    ANTENNAGATEAREA 0.426000 ;
    PORT
      LAYER met2 ;
        RECT 846.950 0.000 847.230 4.000 ;
    END
  END in_data[921]
  PIN in_data[922]
    DIRECTION INPUT ;
    USE SIGNAL ;
    ANTENNAGATEAREA 0.742500 ;
    PORT
      LAYER met2 ;
        RECT 1226.910 1296.000 1227.190 1300.000 ;
    END
  END in_data[922]
  PIN in_data[923]
    DIRECTION INPUT ;
    USE SIGNAL ;
    ANTENNAGATEAREA 0.852000 ;
    PORT
      LAYER met3 ;
        RECT 1296.000 1278.440 1300.000 1279.040 ;
    END
  END in_data[923]
  PIN in_data[924]
    DIRECTION INPUT ;
    USE SIGNAL ;
    ANTENNAGATEAREA 0.426000 ;
    PORT
      LAYER met2 ;
        RECT 953.210 0.000 953.490 4.000 ;
    END
  END in_data[924]
  PIN in_data[925]
    DIRECTION INPUT ;
    USE SIGNAL ;
    ANTENNAGATEAREA 0.742500 ;
    PORT
      LAYER met3 ;
        RECT 1296.000 1152.640 1300.000 1153.240 ;
    END
  END in_data[925]
  PIN in_data[926]
    DIRECTION INPUT ;
    USE SIGNAL ;
    ANTENNAGATEAREA 0.426000 ;
    PORT
      LAYER met3 ;
        RECT 1296.000 693.640 1300.000 694.240 ;
    END
  END in_data[926]
  PIN in_data[927]
    DIRECTION INPUT ;
    USE SIGNAL ;
    ANTENNAGATEAREA 0.495000 ;
    PORT
      LAYER met3 ;
        RECT 0.000 377.440 4.000 378.040 ;
    END
  END in_data[927]
  PIN in_data[928]
    DIRECTION INPUT ;
    USE SIGNAL ;
    ANTENNAGATEAREA 0.742500 ;
    PORT
      LAYER met2 ;
        RECT 341.410 1296.000 341.690 1300.000 ;
    END
  END in_data[928]
  PIN in_data[929]
    DIRECTION INPUT ;
    USE SIGNAL ;
    ANTENNAGATEAREA 0.426000 ;
    PORT
      LAYER met2 ;
        RECT 766.450 1296.000 766.730 1300.000 ;
    END
  END in_data[929]
  PIN in_data[92]
    DIRECTION INPUT ;
    USE SIGNAL ;
    ANTENNAGATEAREA 0.495000 ;
    PORT
      LAYER met2 ;
        RECT 840.510 0.000 840.790 4.000 ;
    END
  END in_data[92]
  PIN in_data[930]
    DIRECTION INPUT ;
    USE SIGNAL ;
    ANTENNAGATEAREA 0.742500 ;
    PORT
      LAYER met2 ;
        RECT 1197.930 0.000 1198.210 4.000 ;
    END
  END in_data[930]
  PIN in_data[931]
    DIRECTION INPUT ;
    USE SIGNAL ;
    ANTENNAGATEAREA 0.247500 ;
    PORT
      LAYER met3 ;
        RECT 1296.000 537.240 1300.000 537.840 ;
    END
  END in_data[931]
  PIN in_data[932]
    DIRECTION INPUT ;
    USE SIGNAL ;
    ANTENNAGATEAREA 0.742500 ;
    PORT
      LAYER met3 ;
        RECT 0.000 894.240 4.000 894.840 ;
    END
  END in_data[932]
  PIN in_data[933]
    DIRECTION INPUT ;
    USE SIGNAL ;
    ANTENNAGATEAREA 0.247500 ;
    PORT
      LAYER met2 ;
        RECT 801.870 0.000 802.150 4.000 ;
    END
  END in_data[933]
  PIN in_data[934]
    DIRECTION INPUT ;
    USE SIGNAL ;
    ANTENNAGATEAREA 0.742500 ;
    PORT
      LAYER met2 ;
        RECT 154.650 0.000 154.930 4.000 ;
    END
  END in_data[934]
  PIN in_data[935]
    DIRECTION INPUT ;
    USE SIGNAL ;
    ANTENNAGATEAREA 0.852000 ;
    PORT
      LAYER met3 ;
        RECT 0.000 1251.240 4.000 1251.840 ;
    END
  END in_data[935]
  PIN in_data[936]
    DIRECTION INPUT ;
    USE SIGNAL ;
    ANTENNAGATEAREA 0.742500 ;
    PORT
      LAYER met3 ;
        RECT 1296.000 1060.840 1300.000 1061.440 ;
    END
  END in_data[936]
  PIN in_data[937]
    DIRECTION INPUT ;
    USE SIGNAL ;
    ANTENNAGATEAREA 0.495000 ;
    PORT
      LAYER met2 ;
        RECT 988.630 1296.000 988.910 1300.000 ;
    END
  END in_data[937]
  PIN in_data[938]
    DIRECTION INPUT ;
    USE SIGNAL ;
    ANTENNAGATEAREA 0.426000 ;
    PORT
      LAYER met2 ;
        RECT 566.810 0.000 567.090 4.000 ;
    END
  END in_data[938]
  PIN in_data[939]
    DIRECTION INPUT ;
    USE SIGNAL ;
    ANTENNAGATEAREA 0.495000 ;
    PORT
      LAYER met2 ;
        RECT 634.430 1296.000 634.710 1300.000 ;
    END
  END in_data[939]
  PIN in_data[93]
    DIRECTION INPUT ;
    USE SIGNAL ;
    ANTENNAGATEAREA 0.426000 ;
    PORT
      LAYER met3 ;
        RECT 1296.000 802.440 1300.000 803.040 ;
    END
  END in_data[93]
  PIN in_data[940]
    DIRECTION INPUT ;
    USE SIGNAL ;
    ANTENNAGATEAREA 0.495000 ;
    PORT
      LAYER met2 ;
        RECT 1123.870 0.000 1124.150 4.000 ;
    END
  END in_data[940]
  PIN in_data[941]
    DIRECTION INPUT ;
    USE SIGNAL ;
    ANTENNAGATEAREA 0.426000 ;
    PORT
      LAYER met2 ;
        RECT 621.550 1296.000 621.830 1300.000 ;
    END
  END in_data[941]
  PIN in_data[942]
    DIRECTION INPUT ;
    USE SIGNAL ;
    ANTENNAGATEAREA 0.495000 ;
    PORT
      LAYER met2 ;
        RECT 1082.010 0.000 1082.290 4.000 ;
    END
  END in_data[942]
  PIN in_data[943]
    DIRECTION INPUT ;
    USE SIGNAL ;
    ANTENNAGATEAREA 0.426000 ;
    PORT
      LAYER met2 ;
        RECT 454.110 0.000 454.390 4.000 ;
    END
  END in_data[943]
  PIN in_data[944]
    DIRECTION INPUT ;
    USE SIGNAL ;
    ANTENNAGATEAREA 0.742500 ;
    PORT
      LAYER met2 ;
        RECT 70.930 0.000 71.210 4.000 ;
    END
  END in_data[944]
  PIN in_data[945]
    DIRECTION INPUT ;
    USE SIGNAL ;
    ANTENNAGATEAREA 0.495000 ;
    PORT
      LAYER met3 ;
        RECT 1296.000 139.440 1300.000 140.040 ;
    END
  END in_data[945]
  PIN in_data[946]
    DIRECTION INPUT ;
    USE SIGNAL ;
    ANTENNAGATEAREA 0.247500 ;
    PORT
      LAYER met3 ;
        RECT 1296.000 544.040 1300.000 544.640 ;
    END
  END in_data[946]
  PIN in_data[947]
    DIRECTION INPUT ;
    USE SIGNAL ;
    ANTENNAGATEAREA 0.852000 ;
    PORT
      LAYER met2 ;
        RECT 12.970 1296.000 13.250 1300.000 ;
    END
  END in_data[947]
  PIN in_data[948]
    DIRECTION INPUT ;
    USE SIGNAL ;
    ANTENNAGATEAREA 0.742500 ;
    PORT
      LAYER met2 ;
        RECT 1168.950 1296.000 1169.230 1300.000 ;
    END
  END in_data[948]
  PIN in_data[949]
    DIRECTION INPUT ;
    USE SIGNAL ;
    ANTENNAGATEAREA 0.426000 ;
    PORT
      LAYER met3 ;
        RECT 0.000 527.040 4.000 527.640 ;
    END
  END in_data[949]
  PIN in_data[94]
    DIRECTION INPUT ;
    USE SIGNAL ;
    ANTENNAGATEAREA 0.426000 ;
    PORT
      LAYER met3 ;
        RECT 0.000 635.840 4.000 636.440 ;
    END
  END in_data[94]
  PIN in_data[950]
    DIRECTION INPUT ;
    USE SIGNAL ;
    ANTENNAGATEAREA 0.495000 ;
    PORT
      LAYER met3 ;
        RECT 0.000 598.440 4.000 599.040 ;
    END
  END in_data[950]
  PIN in_data[951]
    DIRECTION INPUT ;
    USE SIGNAL ;
    ANTENNAGATEAREA 0.742500 ;
    PORT
      LAYER met2 ;
        RECT 58.050 0.000 58.330 4.000 ;
    END
  END in_data[951]
  PIN in_data[952]
    DIRECTION INPUT ;
    USE SIGNAL ;
    ANTENNAGATEAREA 0.495000 ;
    PORT
      LAYER met2 ;
        RECT 305.990 0.000 306.270 4.000 ;
    END
  END in_data[952]
  PIN in_data[953]
    DIRECTION INPUT ;
    USE SIGNAL ;
    ANTENNAGATEAREA 0.495000 ;
    PORT
      LAYER met3 ;
        RECT 1296.000 884.040 1300.000 884.640 ;
    END
  END in_data[953]
  PIN in_data[954]
    DIRECTION INPUT ;
    USE SIGNAL ;
    ANTENNAGATEAREA 0.247500 ;
    PORT
      LAYER met2 ;
        RECT 805.090 0.000 805.370 4.000 ;
    END
  END in_data[954]
  PIN in_data[955]
    DIRECTION INPUT ;
    USE SIGNAL ;
    ANTENNAGATEAREA 0.495000 ;
    PORT
      LAYER met2 ;
        RECT 592.570 1296.000 592.850 1300.000 ;
    END
  END in_data[955]
  PIN in_data[956]
    DIRECTION INPUT ;
    USE SIGNAL ;
    ANTENNAGATEAREA 0.495000 ;
    PORT
      LAYER met2 ;
        RECT 933.890 1296.000 934.170 1300.000 ;
    END
  END in_data[956]
  PIN in_data[957]
    DIRECTION INPUT ;
    USE SIGNAL ;
    ANTENNAGATEAREA 0.742500 ;
    PORT
      LAYER met3 ;
        RECT 0.000 1013.240 4.000 1013.840 ;
    END
  END in_data[957]
  PIN in_data[958]
    DIRECTION INPUT ;
    USE SIGNAL ;
    ANTENNAGATEAREA 0.742500 ;
    PORT
      LAYER met2 ;
        RECT 219.050 0.000 219.330 4.000 ;
    END
  END in_data[958]
  PIN in_data[959]
    DIRECTION INPUT ;
    USE SIGNAL ;
    ANTENNAGATEAREA 0.742500 ;
    PORT
      LAYER met3 ;
        RECT 1296.000 982.640 1300.000 983.240 ;
    END
  END in_data[959]
  PIN in_data[95]
    DIRECTION INPUT ;
    USE SIGNAL ;
    ANTENNAGATEAREA 0.495000 ;
    PORT
      LAYER met2 ;
        RECT 998.290 1296.000 998.570 1300.000 ;
    END
  END in_data[95]
  PIN in_data[960]
    DIRECTION INPUT ;
    USE SIGNAL ;
    ANTENNAGATEAREA 0.495000 ;
    PORT
      LAYER met3 ;
        RECT 0.000 370.640 4.000 371.240 ;
    END
  END in_data[960]
  PIN in_data[961]
    DIRECTION INPUT ;
    USE SIGNAL ;
    ANTENNAGATEAREA 0.742500 ;
    PORT
      LAYER met3 ;
        RECT 1296.000 1230.840 1300.000 1231.440 ;
    END
  END in_data[961]
  PIN in_data[962]
    DIRECTION INPUT ;
    USE SIGNAL ;
    ANTENNAGATEAREA 0.247500 ;
    PORT
      LAYER met3 ;
        RECT 1296.000 564.440 1300.000 565.040 ;
    END
  END in_data[962]
  PIN in_data[963]
    DIRECTION INPUT ;
    USE SIGNAL ;
    ANTENNAGATEAREA 0.426000 ;
    PORT
      LAYER met2 ;
        RECT 959.650 0.000 959.930 4.000 ;
    END
  END in_data[963]
  PIN in_data[964]
    DIRECTION INPUT ;
    USE SIGNAL ;
    ANTENNAGATEAREA 0.742500 ;
    PORT
      LAYER met3 ;
        RECT 0.000 210.840 4.000 211.440 ;
    END
  END in_data[964]
  PIN in_data[965]
    DIRECTION INPUT ;
    USE SIGNAL ;
    ANTENNAGATEAREA 0.852000 ;
    PORT
      LAYER met2 ;
        RECT 48.390 1296.000 48.670 1300.000 ;
    END
  END in_data[965]
  PIN in_data[966]
    DIRECTION INPUT ;
    USE SIGNAL ;
    ANTENNAGATEAREA 0.426000 ;
    PORT
      LAYER met2 ;
        RECT 434.790 0.000 435.070 4.000 ;
    END
  END in_data[966]
  PIN in_data[967]
    DIRECTION INPUT ;
    USE SIGNAL ;
    ANTENNAGATEAREA 0.742500 ;
    PORT
      LAYER met3 ;
        RECT 1296.000 952.040 1300.000 952.640 ;
    END
  END in_data[967]
  PIN in_data[968]
    DIRECTION INPUT ;
    USE SIGNAL ;
    ANTENNAGATEAREA 0.495000 ;
    PORT
      LAYER met2 ;
        RECT 1120.650 0.000 1120.930 4.000 ;
    END
  END in_data[968]
  PIN in_data[969]
    DIRECTION INPUT ;
    USE SIGNAL ;
    ANTENNAGATEAREA 0.247500 ;
    PORT
      LAYER met3 ;
        RECT 1296.000 496.440 1300.000 497.040 ;
    END
  END in_data[969]
  PIN in_data[96]
    DIRECTION INPUT ;
    USE SIGNAL ;
    ANTENNAGATEAREA 0.742500 ;
    PORT
      LAYER met3 ;
        RECT 0.000 363.840 4.000 364.440 ;
    END
  END in_data[96]
  PIN in_data[970]
    DIRECTION INPUT ;
    USE SIGNAL ;
    ANTENNAGATEAREA 0.495000 ;
    PORT
      LAYER met3 ;
        RECT 1296.000 119.040 1300.000 119.640 ;
    END
  END in_data[970]
  PIN in_data[971]
    DIRECTION INPUT ;
    USE SIGNAL ;
    ANTENNAGATEAREA 0.495000 ;
    PORT
      LAYER met2 ;
        RECT 222.270 0.000 222.550 4.000 ;
    END
  END in_data[971]
  PIN in_data[972]
    DIRECTION INPUT ;
    USE SIGNAL ;
    ANTENNAGATEAREA 0.247500 ;
    PORT
      LAYER met2 ;
        RECT 673.070 0.000 673.350 4.000 ;
    END
  END in_data[972]
  PIN in_data[973]
    DIRECTION INPUT ;
    USE SIGNAL ;
    ANTENNAGATEAREA 0.426000 ;
    PORT
      LAYER met3 ;
        RECT 1296.000 676.640 1300.000 677.240 ;
    END
  END in_data[973]
  PIN in_data[974]
    DIRECTION INPUT ;
    USE SIGNAL ;
    ANTENNAGATEAREA 0.495000 ;
    PORT
      LAYER met2 ;
        RECT 856.610 1296.000 856.890 1300.000 ;
    END
  END in_data[974]
  PIN in_data[975]
    DIRECTION INPUT ;
    USE SIGNAL ;
    ANTENNAGATEAREA 0.852000 ;
    PORT
      LAYER met2 ;
        RECT 1278.430 1296.000 1278.710 1300.000 ;
    END
  END in_data[975]
  PIN in_data[976]
    DIRECTION INPUT ;
    USE SIGNAL ;
    ANTENNAGATEAREA 0.495000 ;
    PORT
      LAYER met3 ;
        RECT 1296.000 125.840 1300.000 126.440 ;
    END
  END in_data[976]
  PIN in_data[977]
    DIRECTION INPUT ;
    USE SIGNAL ;
    ANTENNAGATEAREA 0.742500 ;
    PORT
      LAYER met2 ;
        RECT 109.570 0.000 109.850 4.000 ;
    END
  END in_data[977]
  PIN in_data[978]
    DIRECTION INPUT ;
    USE SIGNAL ;
    ANTENNAGATEAREA 0.495000 ;
    PORT
      LAYER met3 ;
        RECT 1296.000 853.440 1300.000 854.040 ;
    END
  END in_data[978]
  PIN in_data[979]
    DIRECTION INPUT ;
    USE SIGNAL ;
    ANTENNAGATEAREA 0.742500 ;
    PORT
      LAYER met2 ;
        RECT 32.290 0.000 32.570 4.000 ;
    END
  END in_data[979]
  PIN in_data[97]
    DIRECTION INPUT ;
    USE SIGNAL ;
    ANTENNAGATEAREA 0.742500 ;
    PORT
      LAYER met2 ;
        RECT 1262.330 1296.000 1262.610 1300.000 ;
    END
  END in_data[97]
  PIN in_data[980]
    DIRECTION INPUT ;
    USE SIGNAL ;
    ANTENNAGATEAREA 0.742500 ;
    PORT
      LAYER met3 ;
        RECT 0.000 85.040 4.000 85.640 ;
    END
  END in_data[980]
  PIN in_data[981]
    DIRECTION INPUT ;
    USE SIGNAL ;
    ANTENNAGATEAREA 0.495000 ;
    PORT
      LAYER met3 ;
        RECT 1296.000 200.640 1300.000 201.240 ;
    END
  END in_data[981]
  PIN in_data[982]
    DIRECTION INPUT ;
    USE SIGNAL ;
    ANTENNAGATEAREA 0.495000 ;
    PORT
      LAYER met2 ;
        RECT 801.870 1296.000 802.150 1300.000 ;
    END
  END in_data[982]
  PIN in_data[983]
    DIRECTION INPUT ;
    USE SIGNAL ;
    ANTENNAGATEAREA 0.426000 ;
    PORT
      LAYER met2 ;
        RECT 898.470 0.000 898.750 4.000 ;
    END
  END in_data[983]
  PIN in_data[984]
    DIRECTION INPUT ;
    USE SIGNAL ;
    ANTENNAGATEAREA 0.742500 ;
    PORT
      LAYER met3 ;
        RECT 0.000 190.440 4.000 191.040 ;
    END
  END in_data[984]
  PIN in_data[985]
    DIRECTION INPUT ;
    USE SIGNAL ;
    ANTENNAGATEAREA 0.426000 ;
    PORT
      LAYER met2 ;
        RECT 895.250 0.000 895.530 4.000 ;
    END
  END in_data[985]
  PIN in_data[986]
    DIRECTION INPUT ;
    USE SIGNAL ;
    ANTENNAGATEAREA 0.742500 ;
    PORT
      LAYER met2 ;
        RECT 0.090 0.000 0.370 4.000 ;
    END
  END in_data[986]
  PIN in_data[987]
    DIRECTION INPUT ;
    USE SIGNAL ;
    ANTENNAGATEAREA 0.495000 ;
    PORT
      LAYER met2 ;
        RECT 1046.590 0.000 1046.870 4.000 ;
    END
  END in_data[987]
  PIN in_data[988]
    DIRECTION INPUT ;
    USE SIGNAL ;
    ANTENNAGATEAREA 0.426000 ;
    PORT
      LAYER met3 ;
        RECT 0.000 452.240 4.000 452.840 ;
    END
  END in_data[988]
  PIN in_data[989]
    DIRECTION INPUT ;
    USE SIGNAL ;
    ANTENNAGATEAREA 0.742500 ;
    PORT
      LAYER met3 ;
        RECT 0.000 1003.040 4.000 1003.640 ;
    END
  END in_data[989]
  PIN in_data[98]
    DIRECTION INPUT ;
    USE SIGNAL ;
    ANTENNAGATEAREA 0.742500 ;
    PORT
      LAYER met2 ;
        RECT 257.690 1296.000 257.970 1300.000 ;
    END
  END in_data[98]
  PIN in_data[990]
    DIRECTION INPUT ;
    USE SIGNAL ;
    ANTENNAGATEAREA 0.742500 ;
    PORT
      LAYER met3 ;
        RECT 0.000 13.640 4.000 14.240 ;
    END
  END in_data[990]
  PIN in_data[991]
    DIRECTION INPUT ;
    USE SIGNAL ;
    ANTENNAGATEAREA 0.495000 ;
    PORT
      LAYER met2 ;
        RECT 277.010 0.000 277.290 4.000 ;
    END
  END in_data[991]
  PIN in_data[992]
    DIRECTION INPUT ;
    USE SIGNAL ;
    ANTENNAGATEAREA 0.742500 ;
    PORT
      LAYER met2 ;
        RECT 96.690 0.000 96.970 4.000 ;
    END
  END in_data[992]
  PIN in_data[993]
    DIRECTION INPUT ;
    USE SIGNAL ;
    ANTENNAGATEAREA 0.495000 ;
    PORT
      LAYER met2 ;
        RECT 595.790 1296.000 596.070 1300.000 ;
    END
  END in_data[993]
  PIN in_data[994]
    DIRECTION INPUT ;
    USE SIGNAL ;
    ANTENNAGATEAREA 0.742500 ;
    PORT
      LAYER met2 ;
        RECT 309.210 1296.000 309.490 1300.000 ;
    END
  END in_data[994]
  PIN in_data[995]
    DIRECTION INPUT ;
    USE SIGNAL ;
    ANTENNAGATEAREA 0.247500 ;
    PORT
      LAYER met2 ;
        RECT 708.490 0.000 708.770 4.000 ;
    END
  END in_data[995]
  PIN in_data[996]
    DIRECTION INPUT ;
    USE SIGNAL ;
    ANTENNAGATEAREA 0.495000 ;
    PORT
      LAYER met2 ;
        RECT 837.290 1296.000 837.570 1300.000 ;
    END
  END in_data[996]
  PIN in_data[997]
    DIRECTION INPUT ;
    USE SIGNAL ;
    ANTENNAGATEAREA 0.426000 ;
    PORT
      LAYER met3 ;
        RECT 1296.000 384.240 1300.000 384.840 ;
    END
  END in_data[997]
  PIN in_data[998]
    DIRECTION INPUT ;
    USE SIGNAL ;
    ANTENNAGATEAREA 0.495000 ;
    PORT
      LAYER met3 ;
        RECT 0.000 778.640 4.000 779.240 ;
    END
  END in_data[998]
  PIN in_data[999]
    DIRECTION INPUT ;
    USE SIGNAL ;
    ANTENNAGATEAREA 0.742500 ;
    PORT
      LAYER met3 ;
        RECT 1296.000 1050.640 1300.000 1051.240 ;
    END
  END in_data[999]
  PIN in_data[99]
    DIRECTION INPUT ;
    USE SIGNAL ;
    ANTENNAGATEAREA 0.742500 ;
    PORT
      LAYER met2 ;
        RECT 286.670 0.000 286.950 4.000 ;
    END
  END in_data[99]
  PIN in_data[9]
    DIRECTION INPUT ;
    USE SIGNAL ;
    ANTENNAGATEAREA 0.495000 ;
    PORT
      LAYER met2 ;
        RECT 499.190 0.000 499.470 4.000 ;
    END
  END in_data[9]
  PIN out_code[0]
    DIRECTION OUTPUT TRISTATE ;
    USE SIGNAL ;
    ANTENNADIFFAREA 0.795200 ;
    PORT
      LAYER met2 ;
        RECT 776.110 0.000 776.390 4.000 ;
    END
  END out_code[0]
  PIN out_code[1]
    DIRECTION OUTPUT TRISTATE ;
    USE SIGNAL ;
    ANTENNADIFFAREA 1.782000 ;
    PORT
      LAYER met3 ;
        RECT 1296.000 986.040 1300.000 986.640 ;
    END
  END out_code[1]
  PIN out_code[2]
    DIRECTION OUTPUT TRISTATE ;
    USE SIGNAL ;
    ANTENNADIFFAREA 0.795200 ;
    PORT
      LAYER met2 ;
        RECT 782.550 0.000 782.830 4.000 ;
    END
  END out_code[2]
  PIN out_code[3]
    DIRECTION OUTPUT TRISTATE ;
    USE SIGNAL ;
    ANTENNADIFFAREA 0.795200 ;
    PORT
      LAYER met2 ;
        RECT 830.850 1296.000 831.130 1300.000 ;
    END
  END out_code[3]
  PIN out_code[4]
    DIRECTION OUTPUT TRISTATE ;
    USE SIGNAL ;
    ANTENNADIFFAREA 0.795200 ;
    PORT
      LAYER met2 ;
        RECT 817.970 1296.000 818.250 1300.000 ;
    END
  END out_code[4]
  PIN out_code[5]
    DIRECTION OUTPUT TRISTATE ;
    USE SIGNAL ;
    ANTENNADIFFAREA 0.795200 ;
    PORT
      LAYER met3 ;
        RECT 0.000 1196.840 4.000 1197.440 ;
    END
  END out_code[5]
  PIN out_code[6]
    DIRECTION OUTPUT TRISTATE ;
    USE SIGNAL ;
    ANTENNADIFFAREA 0.795200 ;
    PORT
      LAYER met2 ;
        RECT 141.770 1296.000 142.050 1300.000 ;
    END
  END out_code[6]
  PIN out_code[7]
    DIRECTION OUTPUT TRISTATE ;
    USE SIGNAL ;
    ANTENNADIFFAREA 0.795200 ;
    PORT
      LAYER met2 ;
        RECT 924.230 0.000 924.510 4.000 ;
    END
  END out_code[7]
  PIN out_code[8]
    DIRECTION OUTPUT TRISTATE ;
    USE SIGNAL ;
    ANTENNADIFFAREA 0.795200 ;
    PORT
      LAYER met3 ;
        RECT 0.000 272.040 4.000 272.640 ;
    END
  END out_code[8]
  PIN out_code[9]
    DIRECTION OUTPUT TRISTATE ;
    USE SIGNAL ;
    ANTENNADIFFAREA 0.795200 ;
    PORT
      LAYER met3 ;
        RECT 0.000 1094.840 4.000 1095.440 ;
    END
  END out_code[9]
  PIN valid
    DIRECTION OUTPUT TRISTATE ;
    USE SIGNAL ;
    ANTENNADIFFAREA 0.445500 ;
    PORT
      LAYER met3 ;
        RECT 1296.000 625.640 1300.000 626.240 ;
    END
  END valid
  OBS
      LAYER li1 ;
        RECT 5.520 10.795 1294.440 1286.645 ;
      LAYER met1 ;
        RECT 0.070 8.200 1299.890 1288.220 ;
      LAYER met2 ;
        RECT 0.650 1295.720 3.030 1299.325 ;
        RECT 3.870 1295.720 9.470 1299.325 ;
        RECT 10.310 1295.720 12.690 1299.325 ;
        RECT 13.530 1295.720 19.130 1299.325 ;
        RECT 19.970 1295.720 22.350 1299.325 ;
        RECT 23.190 1295.720 28.790 1299.325 ;
        RECT 29.630 1295.720 32.010 1299.325 ;
        RECT 32.850 1295.720 38.450 1299.325 ;
        RECT 39.290 1295.720 41.670 1299.325 ;
        RECT 42.510 1295.720 48.110 1299.325 ;
        RECT 48.950 1295.720 51.330 1299.325 ;
        RECT 52.170 1295.720 57.770 1299.325 ;
        RECT 58.610 1295.720 64.210 1299.325 ;
        RECT 65.050 1295.720 67.430 1299.325 ;
        RECT 68.270 1295.720 73.870 1299.325 ;
        RECT 74.710 1295.720 77.090 1299.325 ;
        RECT 77.930 1295.720 83.530 1299.325 ;
        RECT 84.370 1295.720 86.750 1299.325 ;
        RECT 87.590 1295.720 93.190 1299.325 ;
        RECT 94.030 1295.720 96.410 1299.325 ;
        RECT 97.250 1295.720 102.850 1299.325 ;
        RECT 103.690 1295.720 106.070 1299.325 ;
        RECT 106.910 1295.720 112.510 1299.325 ;
        RECT 113.350 1295.720 115.730 1299.325 ;
        RECT 116.570 1295.720 122.170 1299.325 ;
        RECT 123.010 1295.720 125.390 1299.325 ;
        RECT 126.230 1295.720 131.830 1299.325 ;
        RECT 132.670 1295.720 135.050 1299.325 ;
        RECT 135.890 1295.720 141.490 1299.325 ;
        RECT 142.330 1295.720 144.710 1299.325 ;
        RECT 145.550 1295.720 151.150 1299.325 ;
        RECT 151.990 1295.720 154.370 1299.325 ;
        RECT 155.210 1295.720 160.810 1299.325 ;
        RECT 161.650 1295.720 164.030 1299.325 ;
        RECT 164.870 1295.720 170.470 1299.325 ;
        RECT 171.310 1295.720 173.690 1299.325 ;
        RECT 174.530 1295.720 180.130 1299.325 ;
        RECT 180.970 1295.720 186.570 1299.325 ;
        RECT 187.410 1295.720 189.790 1299.325 ;
        RECT 190.630 1295.720 196.230 1299.325 ;
        RECT 197.070 1295.720 199.450 1299.325 ;
        RECT 200.290 1295.720 205.890 1299.325 ;
        RECT 206.730 1295.720 209.110 1299.325 ;
        RECT 209.950 1295.720 215.550 1299.325 ;
        RECT 216.390 1295.720 218.770 1299.325 ;
        RECT 219.610 1295.720 225.210 1299.325 ;
        RECT 226.050 1295.720 228.430 1299.325 ;
        RECT 229.270 1295.720 234.870 1299.325 ;
        RECT 235.710 1295.720 238.090 1299.325 ;
        RECT 238.930 1295.720 244.530 1299.325 ;
        RECT 245.370 1295.720 247.750 1299.325 ;
        RECT 248.590 1295.720 254.190 1299.325 ;
        RECT 255.030 1295.720 257.410 1299.325 ;
        RECT 258.250 1295.720 263.850 1299.325 ;
        RECT 264.690 1295.720 267.070 1299.325 ;
        RECT 267.910 1295.720 273.510 1299.325 ;
        RECT 274.350 1295.720 276.730 1299.325 ;
        RECT 277.570 1295.720 283.170 1299.325 ;
        RECT 284.010 1295.720 286.390 1299.325 ;
        RECT 287.230 1295.720 292.830 1299.325 ;
        RECT 293.670 1295.720 299.270 1299.325 ;
        RECT 300.110 1295.720 302.490 1299.325 ;
        RECT 303.330 1295.720 308.930 1299.325 ;
        RECT 309.770 1295.720 312.150 1299.325 ;
        RECT 312.990 1295.720 318.590 1299.325 ;
        RECT 319.430 1295.720 321.810 1299.325 ;
        RECT 322.650 1295.720 328.250 1299.325 ;
        RECT 329.090 1295.720 331.470 1299.325 ;
        RECT 332.310 1295.720 337.910 1299.325 ;
        RECT 338.750 1295.720 341.130 1299.325 ;
        RECT 341.970 1295.720 347.570 1299.325 ;
        RECT 348.410 1295.720 350.790 1299.325 ;
        RECT 351.630 1295.720 357.230 1299.325 ;
        RECT 358.070 1295.720 360.450 1299.325 ;
        RECT 361.290 1295.720 366.890 1299.325 ;
        RECT 367.730 1295.720 370.110 1299.325 ;
        RECT 370.950 1295.720 376.550 1299.325 ;
        RECT 377.390 1295.720 379.770 1299.325 ;
        RECT 380.610 1295.720 386.210 1299.325 ;
        RECT 387.050 1295.720 389.430 1299.325 ;
        RECT 390.270 1295.720 395.870 1299.325 ;
        RECT 396.710 1295.720 399.090 1299.325 ;
        RECT 399.930 1295.720 405.530 1299.325 ;
        RECT 406.370 1295.720 408.750 1299.325 ;
        RECT 409.590 1295.720 415.190 1299.325 ;
        RECT 416.030 1295.720 421.630 1299.325 ;
        RECT 422.470 1295.720 424.850 1299.325 ;
        RECT 425.690 1295.720 431.290 1299.325 ;
        RECT 432.130 1295.720 434.510 1299.325 ;
        RECT 435.350 1295.720 440.950 1299.325 ;
        RECT 441.790 1295.720 444.170 1299.325 ;
        RECT 445.010 1295.720 450.610 1299.325 ;
        RECT 451.450 1295.720 453.830 1299.325 ;
        RECT 454.670 1295.720 460.270 1299.325 ;
        RECT 461.110 1295.720 463.490 1299.325 ;
        RECT 464.330 1295.720 469.930 1299.325 ;
        RECT 470.770 1295.720 473.150 1299.325 ;
        RECT 473.990 1295.720 479.590 1299.325 ;
        RECT 480.430 1295.720 482.810 1299.325 ;
        RECT 483.650 1295.720 489.250 1299.325 ;
        RECT 490.090 1295.720 492.470 1299.325 ;
        RECT 493.310 1295.720 498.910 1299.325 ;
        RECT 499.750 1295.720 502.130 1299.325 ;
        RECT 502.970 1295.720 508.570 1299.325 ;
        RECT 509.410 1295.720 511.790 1299.325 ;
        RECT 512.630 1295.720 518.230 1299.325 ;
        RECT 519.070 1295.720 521.450 1299.325 ;
        RECT 522.290 1295.720 527.890 1299.325 ;
        RECT 528.730 1295.720 531.110 1299.325 ;
        RECT 531.950 1295.720 537.550 1299.325 ;
        RECT 538.390 1295.720 543.990 1299.325 ;
        RECT 544.830 1295.720 547.210 1299.325 ;
        RECT 548.050 1295.720 553.650 1299.325 ;
        RECT 554.490 1295.720 556.870 1299.325 ;
        RECT 557.710 1295.720 563.310 1299.325 ;
        RECT 564.150 1295.720 566.530 1299.325 ;
        RECT 567.370 1295.720 572.970 1299.325 ;
        RECT 573.810 1295.720 576.190 1299.325 ;
        RECT 577.030 1295.720 582.630 1299.325 ;
        RECT 583.470 1295.720 585.850 1299.325 ;
        RECT 586.690 1295.720 592.290 1299.325 ;
        RECT 593.130 1295.720 595.510 1299.325 ;
        RECT 596.350 1295.720 601.950 1299.325 ;
        RECT 602.790 1295.720 605.170 1299.325 ;
        RECT 606.010 1295.720 611.610 1299.325 ;
        RECT 612.450 1295.720 614.830 1299.325 ;
        RECT 615.670 1295.720 621.270 1299.325 ;
        RECT 622.110 1295.720 624.490 1299.325 ;
        RECT 625.330 1295.720 630.930 1299.325 ;
        RECT 631.770 1295.720 634.150 1299.325 ;
        RECT 634.990 1295.720 640.590 1299.325 ;
        RECT 641.430 1295.720 643.810 1299.325 ;
        RECT 644.650 1295.720 650.250 1299.325 ;
        RECT 651.090 1295.720 656.690 1299.325 ;
        RECT 657.530 1295.720 659.910 1299.325 ;
        RECT 660.750 1295.720 666.350 1299.325 ;
        RECT 667.190 1295.720 669.570 1299.325 ;
        RECT 670.410 1295.720 676.010 1299.325 ;
        RECT 676.850 1295.720 679.230 1299.325 ;
        RECT 680.070 1295.720 685.670 1299.325 ;
        RECT 686.510 1295.720 688.890 1299.325 ;
        RECT 689.730 1295.720 695.330 1299.325 ;
        RECT 696.170 1295.720 698.550 1299.325 ;
        RECT 699.390 1295.720 704.990 1299.325 ;
        RECT 705.830 1295.720 708.210 1299.325 ;
        RECT 709.050 1295.720 714.650 1299.325 ;
        RECT 715.490 1295.720 717.870 1299.325 ;
        RECT 718.710 1295.720 724.310 1299.325 ;
        RECT 725.150 1295.720 727.530 1299.325 ;
        RECT 728.370 1295.720 733.970 1299.325 ;
        RECT 734.810 1295.720 737.190 1299.325 ;
        RECT 738.030 1295.720 743.630 1299.325 ;
        RECT 744.470 1295.720 746.850 1299.325 ;
        RECT 747.690 1295.720 753.290 1299.325 ;
        RECT 754.130 1295.720 756.510 1299.325 ;
        RECT 757.350 1295.720 762.950 1299.325 ;
        RECT 763.790 1295.720 766.170 1299.325 ;
        RECT 767.010 1295.720 772.610 1299.325 ;
        RECT 773.450 1295.720 779.050 1299.325 ;
        RECT 779.890 1295.720 782.270 1299.325 ;
        RECT 783.110 1295.720 788.710 1299.325 ;
        RECT 789.550 1295.720 791.930 1299.325 ;
        RECT 792.770 1295.720 798.370 1299.325 ;
        RECT 799.210 1295.720 801.590 1299.325 ;
        RECT 802.430 1295.720 808.030 1299.325 ;
        RECT 808.870 1295.720 811.250 1299.325 ;
        RECT 812.090 1295.720 817.690 1299.325 ;
        RECT 818.530 1295.720 820.910 1299.325 ;
        RECT 821.750 1295.720 827.350 1299.325 ;
        RECT 828.190 1295.720 830.570 1299.325 ;
        RECT 831.410 1295.720 837.010 1299.325 ;
        RECT 837.850 1295.720 840.230 1299.325 ;
        RECT 841.070 1295.720 846.670 1299.325 ;
        RECT 847.510 1295.720 849.890 1299.325 ;
        RECT 850.730 1295.720 856.330 1299.325 ;
        RECT 857.170 1295.720 859.550 1299.325 ;
        RECT 860.390 1295.720 865.990 1299.325 ;
        RECT 866.830 1295.720 869.210 1299.325 ;
        RECT 870.050 1295.720 875.650 1299.325 ;
        RECT 876.490 1295.720 878.870 1299.325 ;
        RECT 879.710 1295.720 885.310 1299.325 ;
        RECT 886.150 1295.720 891.750 1299.325 ;
        RECT 892.590 1295.720 894.970 1299.325 ;
        RECT 895.810 1295.720 901.410 1299.325 ;
        RECT 902.250 1295.720 904.630 1299.325 ;
        RECT 905.470 1295.720 911.070 1299.325 ;
        RECT 911.910 1295.720 914.290 1299.325 ;
        RECT 915.130 1295.720 920.730 1299.325 ;
        RECT 921.570 1295.720 923.950 1299.325 ;
        RECT 924.790 1295.720 930.390 1299.325 ;
        RECT 931.230 1295.720 933.610 1299.325 ;
        RECT 934.450 1295.720 940.050 1299.325 ;
        RECT 940.890 1295.720 943.270 1299.325 ;
        RECT 944.110 1295.720 949.710 1299.325 ;
        RECT 950.550 1295.720 952.930 1299.325 ;
        RECT 953.770 1295.720 959.370 1299.325 ;
        RECT 960.210 1295.720 962.590 1299.325 ;
        RECT 963.430 1295.720 969.030 1299.325 ;
        RECT 969.870 1295.720 972.250 1299.325 ;
        RECT 973.090 1295.720 978.690 1299.325 ;
        RECT 979.530 1295.720 981.910 1299.325 ;
        RECT 982.750 1295.720 988.350 1299.325 ;
        RECT 989.190 1295.720 991.570 1299.325 ;
        RECT 992.410 1295.720 998.010 1299.325 ;
        RECT 998.850 1295.720 1001.230 1299.325 ;
        RECT 1002.070 1295.720 1007.670 1299.325 ;
        RECT 1008.510 1295.720 1014.110 1299.325 ;
        RECT 1014.950 1295.720 1017.330 1299.325 ;
        RECT 1018.170 1295.720 1023.770 1299.325 ;
        RECT 1024.610 1295.720 1026.990 1299.325 ;
        RECT 1027.830 1295.720 1033.430 1299.325 ;
        RECT 1034.270 1295.720 1036.650 1299.325 ;
        RECT 1037.490 1295.720 1043.090 1299.325 ;
        RECT 1043.930 1295.720 1046.310 1299.325 ;
        RECT 1047.150 1295.720 1052.750 1299.325 ;
        RECT 1053.590 1295.720 1055.970 1299.325 ;
        RECT 1056.810 1295.720 1062.410 1299.325 ;
        RECT 1063.250 1295.720 1065.630 1299.325 ;
        RECT 1066.470 1295.720 1072.070 1299.325 ;
        RECT 1072.910 1295.720 1075.290 1299.325 ;
        RECT 1076.130 1295.720 1081.730 1299.325 ;
        RECT 1082.570 1295.720 1084.950 1299.325 ;
        RECT 1085.790 1295.720 1091.390 1299.325 ;
        RECT 1092.230 1295.720 1094.610 1299.325 ;
        RECT 1095.450 1295.720 1101.050 1299.325 ;
        RECT 1101.890 1295.720 1104.270 1299.325 ;
        RECT 1105.110 1295.720 1110.710 1299.325 ;
        RECT 1111.550 1295.720 1113.930 1299.325 ;
        RECT 1114.770 1295.720 1120.370 1299.325 ;
        RECT 1121.210 1295.720 1126.810 1299.325 ;
        RECT 1127.650 1295.720 1130.030 1299.325 ;
        RECT 1130.870 1295.720 1136.470 1299.325 ;
        RECT 1137.310 1295.720 1139.690 1299.325 ;
        RECT 1140.530 1295.720 1146.130 1299.325 ;
        RECT 1146.970 1295.720 1149.350 1299.325 ;
        RECT 1150.190 1295.720 1155.790 1299.325 ;
        RECT 1156.630 1295.720 1159.010 1299.325 ;
        RECT 1159.850 1295.720 1165.450 1299.325 ;
        RECT 1166.290 1295.720 1168.670 1299.325 ;
        RECT 1169.510 1295.720 1175.110 1299.325 ;
        RECT 1175.950 1295.720 1178.330 1299.325 ;
        RECT 1179.170 1295.720 1184.770 1299.325 ;
        RECT 1185.610 1295.720 1187.990 1299.325 ;
        RECT 1188.830 1295.720 1194.430 1299.325 ;
        RECT 1195.270 1295.720 1197.650 1299.325 ;
        RECT 1198.490 1295.720 1204.090 1299.325 ;
        RECT 1204.930 1295.720 1207.310 1299.325 ;
        RECT 1208.150 1295.720 1213.750 1299.325 ;
        RECT 1214.590 1295.720 1216.970 1299.325 ;
        RECT 1217.810 1295.720 1223.410 1299.325 ;
        RECT 1224.250 1295.720 1226.630 1299.325 ;
        RECT 1227.470 1295.720 1233.070 1299.325 ;
        RECT 1233.910 1295.720 1236.290 1299.325 ;
        RECT 1237.130 1295.720 1242.730 1299.325 ;
        RECT 1243.570 1295.720 1249.170 1299.325 ;
        RECT 1250.010 1295.720 1252.390 1299.325 ;
        RECT 1253.230 1295.720 1258.830 1299.325 ;
        RECT 1259.670 1295.720 1262.050 1299.325 ;
        RECT 1262.890 1295.720 1268.490 1299.325 ;
        RECT 1269.330 1295.720 1271.710 1299.325 ;
        RECT 1272.550 1295.720 1278.150 1299.325 ;
        RECT 1278.990 1295.720 1281.370 1299.325 ;
        RECT 1282.210 1295.720 1287.810 1299.325 ;
        RECT 1288.650 1295.720 1291.030 1299.325 ;
        RECT 1291.870 1295.720 1297.470 1299.325 ;
        RECT 1298.310 1295.720 1299.860 1299.325 ;
        RECT 0.100 4.280 1299.860 1295.720 ;
        RECT 0.650 0.155 3.030 4.280 ;
        RECT 3.870 0.155 9.470 4.280 ;
        RECT 10.310 0.155 12.690 4.280 ;
        RECT 13.530 0.155 19.130 4.280 ;
        RECT 19.970 0.155 22.350 4.280 ;
        RECT 23.190 0.155 28.790 4.280 ;
        RECT 29.630 0.155 32.010 4.280 ;
        RECT 32.850 0.155 38.450 4.280 ;
        RECT 39.290 0.155 41.670 4.280 ;
        RECT 42.510 0.155 48.110 4.280 ;
        RECT 48.950 0.155 51.330 4.280 ;
        RECT 52.170 0.155 57.770 4.280 ;
        RECT 58.610 0.155 60.990 4.280 ;
        RECT 61.830 0.155 67.430 4.280 ;
        RECT 68.270 0.155 70.650 4.280 ;
        RECT 71.490 0.155 77.090 4.280 ;
        RECT 77.930 0.155 80.310 4.280 ;
        RECT 81.150 0.155 86.750 4.280 ;
        RECT 87.590 0.155 89.970 4.280 ;
        RECT 90.810 0.155 96.410 4.280 ;
        RECT 97.250 0.155 99.630 4.280 ;
        RECT 100.470 0.155 106.070 4.280 ;
        RECT 106.910 0.155 109.290 4.280 ;
        RECT 110.130 0.155 115.730 4.280 ;
        RECT 116.570 0.155 122.170 4.280 ;
        RECT 123.010 0.155 125.390 4.280 ;
        RECT 126.230 0.155 131.830 4.280 ;
        RECT 132.670 0.155 135.050 4.280 ;
        RECT 135.890 0.155 141.490 4.280 ;
        RECT 142.330 0.155 144.710 4.280 ;
        RECT 145.550 0.155 151.150 4.280 ;
        RECT 151.990 0.155 154.370 4.280 ;
        RECT 155.210 0.155 160.810 4.280 ;
        RECT 161.650 0.155 164.030 4.280 ;
        RECT 164.870 0.155 170.470 4.280 ;
        RECT 171.310 0.155 173.690 4.280 ;
        RECT 174.530 0.155 180.130 4.280 ;
        RECT 180.970 0.155 183.350 4.280 ;
        RECT 184.190 0.155 189.790 4.280 ;
        RECT 190.630 0.155 193.010 4.280 ;
        RECT 193.850 0.155 199.450 4.280 ;
        RECT 200.290 0.155 202.670 4.280 ;
        RECT 203.510 0.155 209.110 4.280 ;
        RECT 209.950 0.155 212.330 4.280 ;
        RECT 213.170 0.155 218.770 4.280 ;
        RECT 219.610 0.155 221.990 4.280 ;
        RECT 222.830 0.155 228.430 4.280 ;
        RECT 229.270 0.155 231.650 4.280 ;
        RECT 232.490 0.155 238.090 4.280 ;
        RECT 238.930 0.155 244.530 4.280 ;
        RECT 245.370 0.155 247.750 4.280 ;
        RECT 248.590 0.155 254.190 4.280 ;
        RECT 255.030 0.155 257.410 4.280 ;
        RECT 258.250 0.155 263.850 4.280 ;
        RECT 264.690 0.155 267.070 4.280 ;
        RECT 267.910 0.155 273.510 4.280 ;
        RECT 274.350 0.155 276.730 4.280 ;
        RECT 277.570 0.155 283.170 4.280 ;
        RECT 284.010 0.155 286.390 4.280 ;
        RECT 287.230 0.155 292.830 4.280 ;
        RECT 293.670 0.155 296.050 4.280 ;
        RECT 296.890 0.155 302.490 4.280 ;
        RECT 303.330 0.155 305.710 4.280 ;
        RECT 306.550 0.155 312.150 4.280 ;
        RECT 312.990 0.155 315.370 4.280 ;
        RECT 316.210 0.155 321.810 4.280 ;
        RECT 322.650 0.155 325.030 4.280 ;
        RECT 325.870 0.155 331.470 4.280 ;
        RECT 332.310 0.155 334.690 4.280 ;
        RECT 335.530 0.155 341.130 4.280 ;
        RECT 341.970 0.155 344.350 4.280 ;
        RECT 345.190 0.155 350.790 4.280 ;
        RECT 351.630 0.155 357.230 4.280 ;
        RECT 358.070 0.155 360.450 4.280 ;
        RECT 361.290 0.155 366.890 4.280 ;
        RECT 367.730 0.155 370.110 4.280 ;
        RECT 370.950 0.155 376.550 4.280 ;
        RECT 377.390 0.155 379.770 4.280 ;
        RECT 380.610 0.155 386.210 4.280 ;
        RECT 387.050 0.155 389.430 4.280 ;
        RECT 390.270 0.155 395.870 4.280 ;
        RECT 396.710 0.155 399.090 4.280 ;
        RECT 399.930 0.155 405.530 4.280 ;
        RECT 406.370 0.155 408.750 4.280 ;
        RECT 409.590 0.155 415.190 4.280 ;
        RECT 416.030 0.155 418.410 4.280 ;
        RECT 419.250 0.155 424.850 4.280 ;
        RECT 425.690 0.155 428.070 4.280 ;
        RECT 428.910 0.155 434.510 4.280 ;
        RECT 435.350 0.155 437.730 4.280 ;
        RECT 438.570 0.155 444.170 4.280 ;
        RECT 445.010 0.155 447.390 4.280 ;
        RECT 448.230 0.155 453.830 4.280 ;
        RECT 454.670 0.155 457.050 4.280 ;
        RECT 457.890 0.155 463.490 4.280 ;
        RECT 464.330 0.155 466.710 4.280 ;
        RECT 467.550 0.155 473.150 4.280 ;
        RECT 473.990 0.155 479.590 4.280 ;
        RECT 480.430 0.155 482.810 4.280 ;
        RECT 483.650 0.155 489.250 4.280 ;
        RECT 490.090 0.155 492.470 4.280 ;
        RECT 493.310 0.155 498.910 4.280 ;
        RECT 499.750 0.155 502.130 4.280 ;
        RECT 502.970 0.155 508.570 4.280 ;
        RECT 509.410 0.155 511.790 4.280 ;
        RECT 512.630 0.155 518.230 4.280 ;
        RECT 519.070 0.155 521.450 4.280 ;
        RECT 522.290 0.155 527.890 4.280 ;
        RECT 528.730 0.155 531.110 4.280 ;
        RECT 531.950 0.155 537.550 4.280 ;
        RECT 538.390 0.155 540.770 4.280 ;
        RECT 541.610 0.155 547.210 4.280 ;
        RECT 548.050 0.155 550.430 4.280 ;
        RECT 551.270 0.155 556.870 4.280 ;
        RECT 557.710 0.155 560.090 4.280 ;
        RECT 560.930 0.155 566.530 4.280 ;
        RECT 567.370 0.155 569.750 4.280 ;
        RECT 570.590 0.155 576.190 4.280 ;
        RECT 577.030 0.155 579.410 4.280 ;
        RECT 580.250 0.155 585.850 4.280 ;
        RECT 586.690 0.155 592.290 4.280 ;
        RECT 593.130 0.155 595.510 4.280 ;
        RECT 596.350 0.155 601.950 4.280 ;
        RECT 602.790 0.155 605.170 4.280 ;
        RECT 606.010 0.155 611.610 4.280 ;
        RECT 612.450 0.155 614.830 4.280 ;
        RECT 615.670 0.155 621.270 4.280 ;
        RECT 622.110 0.155 624.490 4.280 ;
        RECT 625.330 0.155 630.930 4.280 ;
        RECT 631.770 0.155 634.150 4.280 ;
        RECT 634.990 0.155 640.590 4.280 ;
        RECT 641.430 0.155 643.810 4.280 ;
        RECT 644.650 0.155 650.250 4.280 ;
        RECT 651.090 0.155 653.470 4.280 ;
        RECT 654.310 0.155 659.910 4.280 ;
        RECT 660.750 0.155 663.130 4.280 ;
        RECT 663.970 0.155 669.570 4.280 ;
        RECT 670.410 0.155 672.790 4.280 ;
        RECT 673.630 0.155 679.230 4.280 ;
        RECT 680.070 0.155 682.450 4.280 ;
        RECT 683.290 0.155 688.890 4.280 ;
        RECT 689.730 0.155 692.110 4.280 ;
        RECT 692.950 0.155 698.550 4.280 ;
        RECT 699.390 0.155 701.770 4.280 ;
        RECT 702.610 0.155 708.210 4.280 ;
        RECT 709.050 0.155 714.650 4.280 ;
        RECT 715.490 0.155 717.870 4.280 ;
        RECT 718.710 0.155 724.310 4.280 ;
        RECT 725.150 0.155 727.530 4.280 ;
        RECT 728.370 0.155 733.970 4.280 ;
        RECT 734.810 0.155 737.190 4.280 ;
        RECT 738.030 0.155 743.630 4.280 ;
        RECT 744.470 0.155 746.850 4.280 ;
        RECT 747.690 0.155 753.290 4.280 ;
        RECT 754.130 0.155 756.510 4.280 ;
        RECT 757.350 0.155 762.950 4.280 ;
        RECT 763.790 0.155 766.170 4.280 ;
        RECT 767.010 0.155 772.610 4.280 ;
        RECT 773.450 0.155 775.830 4.280 ;
        RECT 776.670 0.155 782.270 4.280 ;
        RECT 783.110 0.155 785.490 4.280 ;
        RECT 786.330 0.155 791.930 4.280 ;
        RECT 792.770 0.155 795.150 4.280 ;
        RECT 795.990 0.155 801.590 4.280 ;
        RECT 802.430 0.155 804.810 4.280 ;
        RECT 805.650 0.155 811.250 4.280 ;
        RECT 812.090 0.155 814.470 4.280 ;
        RECT 815.310 0.155 820.910 4.280 ;
        RECT 821.750 0.155 827.350 4.280 ;
        RECT 828.190 0.155 830.570 4.280 ;
        RECT 831.410 0.155 837.010 4.280 ;
        RECT 837.850 0.155 840.230 4.280 ;
        RECT 841.070 0.155 846.670 4.280 ;
        RECT 847.510 0.155 849.890 4.280 ;
        RECT 850.730 0.155 856.330 4.280 ;
        RECT 857.170 0.155 859.550 4.280 ;
        RECT 860.390 0.155 865.990 4.280 ;
        RECT 866.830 0.155 869.210 4.280 ;
        RECT 870.050 0.155 875.650 4.280 ;
        RECT 876.490 0.155 878.870 4.280 ;
        RECT 879.710 0.155 885.310 4.280 ;
        RECT 886.150 0.155 888.530 4.280 ;
        RECT 889.370 0.155 894.970 4.280 ;
        RECT 895.810 0.155 898.190 4.280 ;
        RECT 899.030 0.155 904.630 4.280 ;
        RECT 905.470 0.155 907.850 4.280 ;
        RECT 908.690 0.155 914.290 4.280 ;
        RECT 915.130 0.155 917.510 4.280 ;
        RECT 918.350 0.155 923.950 4.280 ;
        RECT 924.790 0.155 927.170 4.280 ;
        RECT 928.010 0.155 933.610 4.280 ;
        RECT 934.450 0.155 936.830 4.280 ;
        RECT 937.670 0.155 943.270 4.280 ;
        RECT 944.110 0.155 949.710 4.280 ;
        RECT 950.550 0.155 952.930 4.280 ;
        RECT 953.770 0.155 959.370 4.280 ;
        RECT 960.210 0.155 962.590 4.280 ;
        RECT 963.430 0.155 969.030 4.280 ;
        RECT 969.870 0.155 972.250 4.280 ;
        RECT 973.090 0.155 978.690 4.280 ;
        RECT 979.530 0.155 981.910 4.280 ;
        RECT 982.750 0.155 988.350 4.280 ;
        RECT 989.190 0.155 991.570 4.280 ;
        RECT 992.410 0.155 998.010 4.280 ;
        RECT 998.850 0.155 1001.230 4.280 ;
        RECT 1002.070 0.155 1007.670 4.280 ;
        RECT 1008.510 0.155 1010.890 4.280 ;
        RECT 1011.730 0.155 1017.330 4.280 ;
        RECT 1018.170 0.155 1020.550 4.280 ;
        RECT 1021.390 0.155 1026.990 4.280 ;
        RECT 1027.830 0.155 1030.210 4.280 ;
        RECT 1031.050 0.155 1036.650 4.280 ;
        RECT 1037.490 0.155 1039.870 4.280 ;
        RECT 1040.710 0.155 1046.310 4.280 ;
        RECT 1047.150 0.155 1049.530 4.280 ;
        RECT 1050.370 0.155 1055.970 4.280 ;
        RECT 1056.810 0.155 1062.410 4.280 ;
        RECT 1063.250 0.155 1065.630 4.280 ;
        RECT 1066.470 0.155 1072.070 4.280 ;
        RECT 1072.910 0.155 1075.290 4.280 ;
        RECT 1076.130 0.155 1081.730 4.280 ;
        RECT 1082.570 0.155 1084.950 4.280 ;
        RECT 1085.790 0.155 1091.390 4.280 ;
        RECT 1092.230 0.155 1094.610 4.280 ;
        RECT 1095.450 0.155 1101.050 4.280 ;
        RECT 1101.890 0.155 1104.270 4.280 ;
        RECT 1105.110 0.155 1110.710 4.280 ;
        RECT 1111.550 0.155 1113.930 4.280 ;
        RECT 1114.770 0.155 1120.370 4.280 ;
        RECT 1121.210 0.155 1123.590 4.280 ;
        RECT 1124.430 0.155 1130.030 4.280 ;
        RECT 1130.870 0.155 1133.250 4.280 ;
        RECT 1134.090 0.155 1139.690 4.280 ;
        RECT 1140.530 0.155 1142.910 4.280 ;
        RECT 1143.750 0.155 1149.350 4.280 ;
        RECT 1150.190 0.155 1152.570 4.280 ;
        RECT 1153.410 0.155 1159.010 4.280 ;
        RECT 1159.850 0.155 1162.230 4.280 ;
        RECT 1163.070 0.155 1168.670 4.280 ;
        RECT 1169.510 0.155 1171.890 4.280 ;
        RECT 1172.730 0.155 1178.330 4.280 ;
        RECT 1179.170 0.155 1184.770 4.280 ;
        RECT 1185.610 0.155 1187.990 4.280 ;
        RECT 1188.830 0.155 1194.430 4.280 ;
        RECT 1195.270 0.155 1197.650 4.280 ;
        RECT 1198.490 0.155 1204.090 4.280 ;
        RECT 1204.930 0.155 1207.310 4.280 ;
        RECT 1208.150 0.155 1213.750 4.280 ;
        RECT 1214.590 0.155 1216.970 4.280 ;
        RECT 1217.810 0.155 1223.410 4.280 ;
        RECT 1224.250 0.155 1226.630 4.280 ;
        RECT 1227.470 0.155 1233.070 4.280 ;
        RECT 1233.910 0.155 1236.290 4.280 ;
        RECT 1237.130 0.155 1242.730 4.280 ;
        RECT 1243.570 0.155 1245.950 4.280 ;
        RECT 1246.790 0.155 1252.390 4.280 ;
        RECT 1253.230 0.155 1255.610 4.280 ;
        RECT 1256.450 0.155 1262.050 4.280 ;
        RECT 1262.890 0.155 1265.270 4.280 ;
        RECT 1266.110 0.155 1271.710 4.280 ;
        RECT 1272.550 0.155 1274.930 4.280 ;
        RECT 1275.770 0.155 1281.370 4.280 ;
        RECT 1282.210 0.155 1284.590 4.280 ;
        RECT 1285.430 0.155 1291.030 4.280 ;
        RECT 1291.870 0.155 1297.470 4.280 ;
        RECT 1298.310 0.155 1299.860 4.280 ;
      LAYER met3 ;
        RECT 3.990 1298.440 1295.600 1299.305 ;
        RECT 3.990 1296.440 1299.435 1298.440 ;
        RECT 4.400 1295.040 1299.435 1296.440 ;
        RECT 3.990 1293.040 1299.435 1295.040 ;
        RECT 4.400 1291.640 1295.600 1293.040 ;
        RECT 3.990 1289.640 1299.435 1291.640 ;
        RECT 3.990 1288.240 1295.600 1289.640 ;
        RECT 3.990 1286.240 1299.435 1288.240 ;
        RECT 4.400 1284.840 1299.435 1286.240 ;
        RECT 3.990 1282.840 1299.435 1284.840 ;
        RECT 4.400 1281.440 1295.600 1282.840 ;
        RECT 3.990 1279.440 1299.435 1281.440 ;
        RECT 3.990 1278.040 1295.600 1279.440 ;
        RECT 3.990 1276.040 1299.435 1278.040 ;
        RECT 4.400 1274.640 1299.435 1276.040 ;
        RECT 3.990 1272.640 1299.435 1274.640 ;
        RECT 4.400 1271.240 1295.600 1272.640 ;
        RECT 3.990 1269.240 1299.435 1271.240 ;
        RECT 3.990 1267.840 1295.600 1269.240 ;
        RECT 3.990 1265.840 1299.435 1267.840 ;
        RECT 4.400 1264.440 1299.435 1265.840 ;
        RECT 3.990 1262.440 1299.435 1264.440 ;
        RECT 4.400 1261.040 1295.600 1262.440 ;
        RECT 3.990 1259.040 1299.435 1261.040 ;
        RECT 3.990 1257.640 1295.600 1259.040 ;
        RECT 3.990 1255.640 1299.435 1257.640 ;
        RECT 4.400 1254.240 1299.435 1255.640 ;
        RECT 3.990 1252.240 1299.435 1254.240 ;
        RECT 4.400 1250.840 1295.600 1252.240 ;
        RECT 3.990 1248.840 1299.435 1250.840 ;
        RECT 3.990 1247.440 1295.600 1248.840 ;
        RECT 3.990 1245.440 1299.435 1247.440 ;
        RECT 4.400 1244.040 1299.435 1245.440 ;
        RECT 3.990 1242.040 1299.435 1244.040 ;
        RECT 3.990 1240.640 1295.600 1242.040 ;
        RECT 3.990 1238.640 1299.435 1240.640 ;
        RECT 4.400 1237.240 1299.435 1238.640 ;
        RECT 3.990 1235.240 1299.435 1237.240 ;
        RECT 4.400 1233.840 1295.600 1235.240 ;
        RECT 3.990 1231.840 1299.435 1233.840 ;
        RECT 3.990 1230.440 1295.600 1231.840 ;
        RECT 3.990 1228.440 1299.435 1230.440 ;
        RECT 4.400 1227.040 1299.435 1228.440 ;
        RECT 3.990 1225.040 1299.435 1227.040 ;
        RECT 4.400 1223.640 1295.600 1225.040 ;
        RECT 3.990 1221.640 1299.435 1223.640 ;
        RECT 3.990 1220.240 1295.600 1221.640 ;
        RECT 3.990 1218.240 1299.435 1220.240 ;
        RECT 4.400 1216.840 1299.435 1218.240 ;
        RECT 3.990 1214.840 1299.435 1216.840 ;
        RECT 4.400 1213.440 1295.600 1214.840 ;
        RECT 3.990 1211.440 1299.435 1213.440 ;
        RECT 3.990 1210.040 1295.600 1211.440 ;
        RECT 3.990 1208.040 1299.435 1210.040 ;
        RECT 4.400 1206.640 1299.435 1208.040 ;
        RECT 3.990 1204.640 1299.435 1206.640 ;
        RECT 4.400 1203.240 1295.600 1204.640 ;
        RECT 3.990 1201.240 1299.435 1203.240 ;
        RECT 3.990 1199.840 1295.600 1201.240 ;
        RECT 3.990 1197.840 1299.435 1199.840 ;
        RECT 4.400 1196.440 1299.435 1197.840 ;
        RECT 3.990 1194.440 1299.435 1196.440 ;
        RECT 4.400 1193.040 1295.600 1194.440 ;
        RECT 3.990 1191.040 1299.435 1193.040 ;
        RECT 3.990 1189.640 1295.600 1191.040 ;
        RECT 3.990 1187.640 1299.435 1189.640 ;
        RECT 4.400 1186.240 1299.435 1187.640 ;
        RECT 3.990 1184.240 1299.435 1186.240 ;
        RECT 4.400 1182.840 1295.600 1184.240 ;
        RECT 3.990 1180.840 1299.435 1182.840 ;
        RECT 3.990 1179.440 1295.600 1180.840 ;
        RECT 3.990 1177.440 1299.435 1179.440 ;
        RECT 4.400 1176.040 1299.435 1177.440 ;
        RECT 3.990 1174.040 1299.435 1176.040 ;
        RECT 4.400 1172.640 1295.600 1174.040 ;
        RECT 3.990 1170.640 1299.435 1172.640 ;
        RECT 3.990 1169.240 1295.600 1170.640 ;
        RECT 3.990 1167.240 1299.435 1169.240 ;
        RECT 4.400 1165.840 1299.435 1167.240 ;
        RECT 3.990 1163.840 1299.435 1165.840 ;
        RECT 4.400 1162.440 1295.600 1163.840 ;
        RECT 3.990 1160.440 1299.435 1162.440 ;
        RECT 3.990 1159.040 1295.600 1160.440 ;
        RECT 3.990 1157.040 1299.435 1159.040 ;
        RECT 4.400 1155.640 1299.435 1157.040 ;
        RECT 3.990 1153.640 1299.435 1155.640 ;
        RECT 4.400 1152.240 1295.600 1153.640 ;
        RECT 3.990 1150.240 1299.435 1152.240 ;
        RECT 3.990 1148.840 1295.600 1150.240 ;
        RECT 3.990 1146.840 1299.435 1148.840 ;
        RECT 4.400 1145.440 1299.435 1146.840 ;
        RECT 3.990 1143.440 1299.435 1145.440 ;
        RECT 4.400 1142.040 1295.600 1143.440 ;
        RECT 3.990 1140.040 1299.435 1142.040 ;
        RECT 3.990 1138.640 1295.600 1140.040 ;
        RECT 3.990 1136.640 1299.435 1138.640 ;
        RECT 4.400 1135.240 1299.435 1136.640 ;
        RECT 3.990 1133.240 1299.435 1135.240 ;
        RECT 4.400 1131.840 1295.600 1133.240 ;
        RECT 3.990 1129.840 1299.435 1131.840 ;
        RECT 3.990 1128.440 1295.600 1129.840 ;
        RECT 3.990 1126.440 1299.435 1128.440 ;
        RECT 4.400 1125.040 1299.435 1126.440 ;
        RECT 3.990 1123.040 1299.435 1125.040 ;
        RECT 4.400 1121.640 1295.600 1123.040 ;
        RECT 3.990 1119.640 1299.435 1121.640 ;
        RECT 3.990 1118.240 1295.600 1119.640 ;
        RECT 3.990 1116.240 1299.435 1118.240 ;
        RECT 4.400 1114.840 1299.435 1116.240 ;
        RECT 3.990 1112.840 1299.435 1114.840 ;
        RECT 3.990 1111.440 1295.600 1112.840 ;
        RECT 3.990 1109.440 1299.435 1111.440 ;
        RECT 4.400 1108.040 1299.435 1109.440 ;
        RECT 3.990 1106.040 1299.435 1108.040 ;
        RECT 4.400 1104.640 1295.600 1106.040 ;
        RECT 3.990 1102.640 1299.435 1104.640 ;
        RECT 3.990 1101.240 1295.600 1102.640 ;
        RECT 3.990 1099.240 1299.435 1101.240 ;
        RECT 4.400 1097.840 1299.435 1099.240 ;
        RECT 3.990 1095.840 1299.435 1097.840 ;
        RECT 4.400 1094.440 1295.600 1095.840 ;
        RECT 3.990 1092.440 1299.435 1094.440 ;
        RECT 3.990 1091.040 1295.600 1092.440 ;
        RECT 3.990 1089.040 1299.435 1091.040 ;
        RECT 4.400 1087.640 1299.435 1089.040 ;
        RECT 3.990 1085.640 1299.435 1087.640 ;
        RECT 4.400 1084.240 1295.600 1085.640 ;
        RECT 3.990 1082.240 1299.435 1084.240 ;
        RECT 3.990 1080.840 1295.600 1082.240 ;
        RECT 3.990 1078.840 1299.435 1080.840 ;
        RECT 4.400 1077.440 1299.435 1078.840 ;
        RECT 3.990 1075.440 1299.435 1077.440 ;
        RECT 4.400 1074.040 1295.600 1075.440 ;
        RECT 3.990 1072.040 1299.435 1074.040 ;
        RECT 3.990 1070.640 1295.600 1072.040 ;
        RECT 3.990 1068.640 1299.435 1070.640 ;
        RECT 4.400 1067.240 1299.435 1068.640 ;
        RECT 3.990 1065.240 1299.435 1067.240 ;
        RECT 4.400 1063.840 1295.600 1065.240 ;
        RECT 3.990 1061.840 1299.435 1063.840 ;
        RECT 3.990 1060.440 1295.600 1061.840 ;
        RECT 3.990 1058.440 1299.435 1060.440 ;
        RECT 4.400 1057.040 1299.435 1058.440 ;
        RECT 3.990 1055.040 1299.435 1057.040 ;
        RECT 4.400 1053.640 1295.600 1055.040 ;
        RECT 3.990 1051.640 1299.435 1053.640 ;
        RECT 3.990 1050.240 1295.600 1051.640 ;
        RECT 3.990 1048.240 1299.435 1050.240 ;
        RECT 4.400 1046.840 1299.435 1048.240 ;
        RECT 3.990 1044.840 1299.435 1046.840 ;
        RECT 4.400 1043.440 1295.600 1044.840 ;
        RECT 3.990 1041.440 1299.435 1043.440 ;
        RECT 3.990 1040.040 1295.600 1041.440 ;
        RECT 3.990 1038.040 1299.435 1040.040 ;
        RECT 4.400 1036.640 1299.435 1038.040 ;
        RECT 3.990 1034.640 1299.435 1036.640 ;
        RECT 4.400 1033.240 1295.600 1034.640 ;
        RECT 3.990 1031.240 1299.435 1033.240 ;
        RECT 3.990 1029.840 1295.600 1031.240 ;
        RECT 3.990 1027.840 1299.435 1029.840 ;
        RECT 4.400 1026.440 1299.435 1027.840 ;
        RECT 3.990 1024.440 1299.435 1026.440 ;
        RECT 4.400 1023.040 1295.600 1024.440 ;
        RECT 3.990 1021.040 1299.435 1023.040 ;
        RECT 3.990 1019.640 1295.600 1021.040 ;
        RECT 3.990 1017.640 1299.435 1019.640 ;
        RECT 4.400 1016.240 1299.435 1017.640 ;
        RECT 3.990 1014.240 1299.435 1016.240 ;
        RECT 4.400 1012.840 1295.600 1014.240 ;
        RECT 3.990 1010.840 1299.435 1012.840 ;
        RECT 3.990 1009.440 1295.600 1010.840 ;
        RECT 3.990 1007.440 1299.435 1009.440 ;
        RECT 4.400 1006.040 1299.435 1007.440 ;
        RECT 3.990 1004.040 1299.435 1006.040 ;
        RECT 4.400 1002.640 1295.600 1004.040 ;
        RECT 3.990 1000.640 1299.435 1002.640 ;
        RECT 3.990 999.240 1295.600 1000.640 ;
        RECT 3.990 997.240 1299.435 999.240 ;
        RECT 4.400 995.840 1299.435 997.240 ;
        RECT 3.990 993.840 1299.435 995.840 ;
        RECT 3.990 992.440 1295.600 993.840 ;
        RECT 3.990 990.440 1299.435 992.440 ;
        RECT 4.400 989.040 1299.435 990.440 ;
        RECT 3.990 987.040 1299.435 989.040 ;
        RECT 4.400 985.640 1295.600 987.040 ;
        RECT 3.990 983.640 1299.435 985.640 ;
        RECT 3.990 982.240 1295.600 983.640 ;
        RECT 3.990 980.240 1299.435 982.240 ;
        RECT 4.400 978.840 1299.435 980.240 ;
        RECT 3.990 976.840 1299.435 978.840 ;
        RECT 4.400 975.440 1295.600 976.840 ;
        RECT 3.990 973.440 1299.435 975.440 ;
        RECT 3.990 972.040 1295.600 973.440 ;
        RECT 3.990 970.040 1299.435 972.040 ;
        RECT 4.400 968.640 1299.435 970.040 ;
        RECT 3.990 966.640 1299.435 968.640 ;
        RECT 4.400 965.240 1295.600 966.640 ;
        RECT 3.990 963.240 1299.435 965.240 ;
        RECT 3.990 961.840 1295.600 963.240 ;
        RECT 3.990 959.840 1299.435 961.840 ;
        RECT 4.400 958.440 1299.435 959.840 ;
        RECT 3.990 956.440 1299.435 958.440 ;
        RECT 4.400 955.040 1295.600 956.440 ;
        RECT 3.990 953.040 1299.435 955.040 ;
        RECT 3.990 951.640 1295.600 953.040 ;
        RECT 3.990 949.640 1299.435 951.640 ;
        RECT 4.400 948.240 1299.435 949.640 ;
        RECT 3.990 946.240 1299.435 948.240 ;
        RECT 4.400 944.840 1295.600 946.240 ;
        RECT 3.990 942.840 1299.435 944.840 ;
        RECT 3.990 941.440 1295.600 942.840 ;
        RECT 3.990 939.440 1299.435 941.440 ;
        RECT 4.400 938.040 1299.435 939.440 ;
        RECT 3.990 936.040 1299.435 938.040 ;
        RECT 4.400 934.640 1295.600 936.040 ;
        RECT 3.990 932.640 1299.435 934.640 ;
        RECT 3.990 931.240 1295.600 932.640 ;
        RECT 3.990 929.240 1299.435 931.240 ;
        RECT 4.400 927.840 1299.435 929.240 ;
        RECT 3.990 925.840 1299.435 927.840 ;
        RECT 4.400 924.440 1295.600 925.840 ;
        RECT 3.990 922.440 1299.435 924.440 ;
        RECT 3.990 921.040 1295.600 922.440 ;
        RECT 3.990 919.040 1299.435 921.040 ;
        RECT 4.400 917.640 1299.435 919.040 ;
        RECT 3.990 915.640 1299.435 917.640 ;
        RECT 4.400 914.240 1295.600 915.640 ;
        RECT 3.990 912.240 1299.435 914.240 ;
        RECT 3.990 910.840 1295.600 912.240 ;
        RECT 3.990 908.840 1299.435 910.840 ;
        RECT 4.400 907.440 1299.435 908.840 ;
        RECT 3.990 905.440 1299.435 907.440 ;
        RECT 4.400 904.040 1295.600 905.440 ;
        RECT 3.990 902.040 1299.435 904.040 ;
        RECT 3.990 900.640 1295.600 902.040 ;
        RECT 3.990 898.640 1299.435 900.640 ;
        RECT 4.400 897.240 1299.435 898.640 ;
        RECT 3.990 895.240 1299.435 897.240 ;
        RECT 4.400 893.840 1295.600 895.240 ;
        RECT 3.990 891.840 1299.435 893.840 ;
        RECT 3.990 890.440 1295.600 891.840 ;
        RECT 3.990 888.440 1299.435 890.440 ;
        RECT 4.400 887.040 1299.435 888.440 ;
        RECT 3.990 885.040 1299.435 887.040 ;
        RECT 4.400 883.640 1295.600 885.040 ;
        RECT 3.990 881.640 1299.435 883.640 ;
        RECT 3.990 880.240 1295.600 881.640 ;
        RECT 3.990 878.240 1299.435 880.240 ;
        RECT 4.400 876.840 1299.435 878.240 ;
        RECT 3.990 874.840 1299.435 876.840 ;
        RECT 4.400 873.440 1295.600 874.840 ;
        RECT 3.990 871.440 1299.435 873.440 ;
        RECT 3.990 870.040 1295.600 871.440 ;
        RECT 3.990 868.040 1299.435 870.040 ;
        RECT 4.400 866.640 1299.435 868.040 ;
        RECT 3.990 864.640 1299.435 866.640 ;
        RECT 3.990 863.240 1295.600 864.640 ;
        RECT 3.990 861.240 1299.435 863.240 ;
        RECT 4.400 859.840 1299.435 861.240 ;
        RECT 3.990 857.840 1299.435 859.840 ;
        RECT 4.400 856.440 1295.600 857.840 ;
        RECT 3.990 854.440 1299.435 856.440 ;
        RECT 3.990 853.040 1295.600 854.440 ;
        RECT 3.990 851.040 1299.435 853.040 ;
        RECT 4.400 849.640 1299.435 851.040 ;
        RECT 3.990 847.640 1299.435 849.640 ;
        RECT 4.400 846.240 1295.600 847.640 ;
        RECT 3.990 844.240 1299.435 846.240 ;
        RECT 3.990 842.840 1295.600 844.240 ;
        RECT 3.990 840.840 1299.435 842.840 ;
        RECT 4.400 839.440 1299.435 840.840 ;
        RECT 3.990 837.440 1299.435 839.440 ;
        RECT 4.400 836.040 1295.600 837.440 ;
        RECT 3.990 834.040 1299.435 836.040 ;
        RECT 3.990 832.640 1295.600 834.040 ;
        RECT 3.990 830.640 1299.435 832.640 ;
        RECT 4.400 829.240 1299.435 830.640 ;
        RECT 3.990 827.240 1299.435 829.240 ;
        RECT 4.400 825.840 1295.600 827.240 ;
        RECT 3.990 823.840 1299.435 825.840 ;
        RECT 3.990 822.440 1295.600 823.840 ;
        RECT 3.990 820.440 1299.435 822.440 ;
        RECT 4.400 819.040 1299.435 820.440 ;
        RECT 3.990 817.040 1299.435 819.040 ;
        RECT 4.400 815.640 1295.600 817.040 ;
        RECT 3.990 813.640 1299.435 815.640 ;
        RECT 3.990 812.240 1295.600 813.640 ;
        RECT 3.990 810.240 1299.435 812.240 ;
        RECT 4.400 808.840 1299.435 810.240 ;
        RECT 3.990 806.840 1299.435 808.840 ;
        RECT 4.400 805.440 1295.600 806.840 ;
        RECT 3.990 803.440 1299.435 805.440 ;
        RECT 3.990 802.040 1295.600 803.440 ;
        RECT 3.990 800.040 1299.435 802.040 ;
        RECT 4.400 798.640 1299.435 800.040 ;
        RECT 3.990 796.640 1299.435 798.640 ;
        RECT 4.400 795.240 1295.600 796.640 ;
        RECT 3.990 793.240 1299.435 795.240 ;
        RECT 3.990 791.840 1295.600 793.240 ;
        RECT 3.990 789.840 1299.435 791.840 ;
        RECT 4.400 788.440 1299.435 789.840 ;
        RECT 3.990 786.440 1299.435 788.440 ;
        RECT 4.400 785.040 1295.600 786.440 ;
        RECT 3.990 783.040 1299.435 785.040 ;
        RECT 3.990 781.640 1295.600 783.040 ;
        RECT 3.990 779.640 1299.435 781.640 ;
        RECT 4.400 778.240 1299.435 779.640 ;
        RECT 3.990 776.240 1299.435 778.240 ;
        RECT 4.400 774.840 1295.600 776.240 ;
        RECT 3.990 772.840 1299.435 774.840 ;
        RECT 3.990 771.440 1295.600 772.840 ;
        RECT 3.990 769.440 1299.435 771.440 ;
        RECT 4.400 768.040 1299.435 769.440 ;
        RECT 3.990 766.040 1299.435 768.040 ;
        RECT 4.400 764.640 1295.600 766.040 ;
        RECT 3.990 762.640 1299.435 764.640 ;
        RECT 3.990 761.240 1295.600 762.640 ;
        RECT 3.990 759.240 1299.435 761.240 ;
        RECT 4.400 757.840 1299.435 759.240 ;
        RECT 3.990 755.840 1299.435 757.840 ;
        RECT 4.400 754.440 1295.600 755.840 ;
        RECT 3.990 752.440 1299.435 754.440 ;
        RECT 3.990 751.040 1295.600 752.440 ;
        RECT 3.990 749.040 1299.435 751.040 ;
        RECT 4.400 747.640 1299.435 749.040 ;
        RECT 3.990 745.640 1299.435 747.640 ;
        RECT 3.990 744.240 1295.600 745.640 ;
        RECT 3.990 742.240 1299.435 744.240 ;
        RECT 4.400 740.840 1299.435 742.240 ;
        RECT 3.990 738.840 1299.435 740.840 ;
        RECT 4.400 737.440 1295.600 738.840 ;
        RECT 3.990 735.440 1299.435 737.440 ;
        RECT 3.990 734.040 1295.600 735.440 ;
        RECT 3.990 732.040 1299.435 734.040 ;
        RECT 4.400 730.640 1299.435 732.040 ;
        RECT 3.990 728.640 1299.435 730.640 ;
        RECT 4.400 727.240 1295.600 728.640 ;
        RECT 3.990 725.240 1299.435 727.240 ;
        RECT 3.990 723.840 1295.600 725.240 ;
        RECT 3.990 721.840 1299.435 723.840 ;
        RECT 4.400 720.440 1299.435 721.840 ;
        RECT 3.990 718.440 1299.435 720.440 ;
        RECT 4.400 717.040 1295.600 718.440 ;
        RECT 3.990 715.040 1299.435 717.040 ;
        RECT 3.990 713.640 1295.600 715.040 ;
        RECT 3.990 711.640 1299.435 713.640 ;
        RECT 4.400 710.240 1299.435 711.640 ;
        RECT 3.990 708.240 1299.435 710.240 ;
        RECT 4.400 706.840 1295.600 708.240 ;
        RECT 3.990 704.840 1299.435 706.840 ;
        RECT 3.990 703.440 1295.600 704.840 ;
        RECT 3.990 701.440 1299.435 703.440 ;
        RECT 4.400 700.040 1299.435 701.440 ;
        RECT 3.990 698.040 1299.435 700.040 ;
        RECT 4.400 696.640 1295.600 698.040 ;
        RECT 3.990 694.640 1299.435 696.640 ;
        RECT 3.990 693.240 1295.600 694.640 ;
        RECT 3.990 691.240 1299.435 693.240 ;
        RECT 4.400 689.840 1299.435 691.240 ;
        RECT 3.990 687.840 1299.435 689.840 ;
        RECT 4.400 686.440 1295.600 687.840 ;
        RECT 3.990 684.440 1299.435 686.440 ;
        RECT 3.990 683.040 1295.600 684.440 ;
        RECT 3.990 681.040 1299.435 683.040 ;
        RECT 4.400 679.640 1299.435 681.040 ;
        RECT 3.990 677.640 1299.435 679.640 ;
        RECT 4.400 676.240 1295.600 677.640 ;
        RECT 3.990 674.240 1299.435 676.240 ;
        RECT 3.990 672.840 1295.600 674.240 ;
        RECT 3.990 670.840 1299.435 672.840 ;
        RECT 4.400 669.440 1299.435 670.840 ;
        RECT 3.990 667.440 1299.435 669.440 ;
        RECT 4.400 666.040 1295.600 667.440 ;
        RECT 3.990 664.040 1299.435 666.040 ;
        RECT 3.990 662.640 1295.600 664.040 ;
        RECT 3.990 660.640 1299.435 662.640 ;
        RECT 4.400 659.240 1299.435 660.640 ;
        RECT 3.990 657.240 1299.435 659.240 ;
        RECT 4.400 655.840 1295.600 657.240 ;
        RECT 3.990 653.840 1299.435 655.840 ;
        RECT 3.990 652.440 1295.600 653.840 ;
        RECT 3.990 650.440 1299.435 652.440 ;
        RECT 4.400 649.040 1299.435 650.440 ;
        RECT 3.990 647.040 1299.435 649.040 ;
        RECT 4.400 645.640 1295.600 647.040 ;
        RECT 3.990 643.640 1299.435 645.640 ;
        RECT 3.990 642.240 1295.600 643.640 ;
        RECT 3.990 640.240 1299.435 642.240 ;
        RECT 4.400 638.840 1299.435 640.240 ;
        RECT 3.990 636.840 1299.435 638.840 ;
        RECT 4.400 635.440 1295.600 636.840 ;
        RECT 3.990 633.440 1299.435 635.440 ;
        RECT 3.990 632.040 1295.600 633.440 ;
        RECT 3.990 630.040 1299.435 632.040 ;
        RECT 4.400 628.640 1299.435 630.040 ;
        RECT 3.990 626.640 1299.435 628.640 ;
        RECT 4.400 625.240 1295.600 626.640 ;
        RECT 3.990 623.240 1299.435 625.240 ;
        RECT 3.990 621.840 1295.600 623.240 ;
        RECT 3.990 619.840 1299.435 621.840 ;
        RECT 4.400 618.440 1299.435 619.840 ;
        RECT 3.990 616.440 1299.435 618.440 ;
        RECT 3.990 615.040 1295.600 616.440 ;
        RECT 3.990 613.040 1299.435 615.040 ;
        RECT 4.400 611.640 1299.435 613.040 ;
        RECT 3.990 609.640 1299.435 611.640 ;
        RECT 4.400 608.240 1295.600 609.640 ;
        RECT 3.990 606.240 1299.435 608.240 ;
        RECT 3.990 604.840 1295.600 606.240 ;
        RECT 3.990 602.840 1299.435 604.840 ;
        RECT 4.400 601.440 1299.435 602.840 ;
        RECT 3.990 599.440 1299.435 601.440 ;
        RECT 4.400 598.040 1295.600 599.440 ;
        RECT 3.990 596.040 1299.435 598.040 ;
        RECT 3.990 594.640 1295.600 596.040 ;
        RECT 3.990 592.640 1299.435 594.640 ;
        RECT 4.400 591.240 1299.435 592.640 ;
        RECT 3.990 589.240 1299.435 591.240 ;
        RECT 4.400 587.840 1295.600 589.240 ;
        RECT 3.990 585.840 1299.435 587.840 ;
        RECT 3.990 584.440 1295.600 585.840 ;
        RECT 3.990 582.440 1299.435 584.440 ;
        RECT 4.400 581.040 1299.435 582.440 ;
        RECT 3.990 579.040 1299.435 581.040 ;
        RECT 4.400 577.640 1295.600 579.040 ;
        RECT 3.990 575.640 1299.435 577.640 ;
        RECT 3.990 574.240 1295.600 575.640 ;
        RECT 3.990 572.240 1299.435 574.240 ;
        RECT 4.400 570.840 1299.435 572.240 ;
        RECT 3.990 568.840 1299.435 570.840 ;
        RECT 4.400 567.440 1295.600 568.840 ;
        RECT 3.990 565.440 1299.435 567.440 ;
        RECT 3.990 564.040 1295.600 565.440 ;
        RECT 3.990 562.040 1299.435 564.040 ;
        RECT 4.400 560.640 1299.435 562.040 ;
        RECT 3.990 558.640 1299.435 560.640 ;
        RECT 4.400 557.240 1295.600 558.640 ;
        RECT 3.990 555.240 1299.435 557.240 ;
        RECT 3.990 553.840 1295.600 555.240 ;
        RECT 3.990 551.840 1299.435 553.840 ;
        RECT 4.400 550.440 1299.435 551.840 ;
        RECT 3.990 548.440 1299.435 550.440 ;
        RECT 4.400 547.040 1295.600 548.440 ;
        RECT 3.990 545.040 1299.435 547.040 ;
        RECT 3.990 543.640 1295.600 545.040 ;
        RECT 3.990 541.640 1299.435 543.640 ;
        RECT 4.400 540.240 1299.435 541.640 ;
        RECT 3.990 538.240 1299.435 540.240 ;
        RECT 4.400 536.840 1295.600 538.240 ;
        RECT 3.990 534.840 1299.435 536.840 ;
        RECT 3.990 533.440 1295.600 534.840 ;
        RECT 3.990 531.440 1299.435 533.440 ;
        RECT 4.400 530.040 1299.435 531.440 ;
        RECT 3.990 528.040 1299.435 530.040 ;
        RECT 4.400 526.640 1295.600 528.040 ;
        RECT 3.990 524.640 1299.435 526.640 ;
        RECT 3.990 523.240 1295.600 524.640 ;
        RECT 3.990 521.240 1299.435 523.240 ;
        RECT 4.400 519.840 1299.435 521.240 ;
        RECT 3.990 517.840 1299.435 519.840 ;
        RECT 4.400 516.440 1295.600 517.840 ;
        RECT 3.990 514.440 1299.435 516.440 ;
        RECT 3.990 513.040 1295.600 514.440 ;
        RECT 3.990 511.040 1299.435 513.040 ;
        RECT 4.400 509.640 1299.435 511.040 ;
        RECT 3.990 507.640 1299.435 509.640 ;
        RECT 4.400 506.240 1295.600 507.640 ;
        RECT 3.990 504.240 1299.435 506.240 ;
        RECT 3.990 502.840 1295.600 504.240 ;
        RECT 3.990 500.840 1299.435 502.840 ;
        RECT 4.400 499.440 1299.435 500.840 ;
        RECT 3.990 497.440 1299.435 499.440 ;
        RECT 3.990 496.040 1295.600 497.440 ;
        RECT 3.990 494.040 1299.435 496.040 ;
        RECT 4.400 492.640 1299.435 494.040 ;
        RECT 3.990 490.640 1299.435 492.640 ;
        RECT 4.400 489.240 1295.600 490.640 ;
        RECT 3.990 487.240 1299.435 489.240 ;
        RECT 3.990 485.840 1295.600 487.240 ;
        RECT 3.990 483.840 1299.435 485.840 ;
        RECT 4.400 482.440 1299.435 483.840 ;
        RECT 3.990 480.440 1299.435 482.440 ;
        RECT 4.400 479.040 1295.600 480.440 ;
        RECT 3.990 477.040 1299.435 479.040 ;
        RECT 3.990 475.640 1295.600 477.040 ;
        RECT 3.990 473.640 1299.435 475.640 ;
        RECT 4.400 472.240 1299.435 473.640 ;
        RECT 3.990 470.240 1299.435 472.240 ;
        RECT 4.400 468.840 1295.600 470.240 ;
        RECT 3.990 466.840 1299.435 468.840 ;
        RECT 3.990 465.440 1295.600 466.840 ;
        RECT 3.990 463.440 1299.435 465.440 ;
        RECT 4.400 462.040 1299.435 463.440 ;
        RECT 3.990 460.040 1299.435 462.040 ;
        RECT 4.400 458.640 1295.600 460.040 ;
        RECT 3.990 456.640 1299.435 458.640 ;
        RECT 3.990 455.240 1295.600 456.640 ;
        RECT 3.990 453.240 1299.435 455.240 ;
        RECT 4.400 451.840 1299.435 453.240 ;
        RECT 3.990 449.840 1299.435 451.840 ;
        RECT 4.400 448.440 1295.600 449.840 ;
        RECT 3.990 446.440 1299.435 448.440 ;
        RECT 3.990 445.040 1295.600 446.440 ;
        RECT 3.990 443.040 1299.435 445.040 ;
        RECT 4.400 441.640 1299.435 443.040 ;
        RECT 3.990 439.640 1299.435 441.640 ;
        RECT 4.400 438.240 1295.600 439.640 ;
        RECT 3.990 436.240 1299.435 438.240 ;
        RECT 3.990 434.840 1295.600 436.240 ;
        RECT 3.990 432.840 1299.435 434.840 ;
        RECT 4.400 431.440 1299.435 432.840 ;
        RECT 3.990 429.440 1299.435 431.440 ;
        RECT 4.400 428.040 1295.600 429.440 ;
        RECT 3.990 426.040 1299.435 428.040 ;
        RECT 3.990 424.640 1295.600 426.040 ;
        RECT 3.990 422.640 1299.435 424.640 ;
        RECT 4.400 421.240 1299.435 422.640 ;
        RECT 3.990 419.240 1299.435 421.240 ;
        RECT 4.400 417.840 1295.600 419.240 ;
        RECT 3.990 415.840 1299.435 417.840 ;
        RECT 3.990 414.440 1295.600 415.840 ;
        RECT 3.990 412.440 1299.435 414.440 ;
        RECT 4.400 411.040 1299.435 412.440 ;
        RECT 3.990 409.040 1299.435 411.040 ;
        RECT 4.400 407.640 1295.600 409.040 ;
        RECT 3.990 405.640 1299.435 407.640 ;
        RECT 3.990 404.240 1295.600 405.640 ;
        RECT 3.990 402.240 1299.435 404.240 ;
        RECT 4.400 400.840 1299.435 402.240 ;
        RECT 3.990 398.840 1299.435 400.840 ;
        RECT 4.400 397.440 1295.600 398.840 ;
        RECT 3.990 395.440 1299.435 397.440 ;
        RECT 3.990 394.040 1295.600 395.440 ;
        RECT 3.990 392.040 1299.435 394.040 ;
        RECT 4.400 390.640 1299.435 392.040 ;
        RECT 3.990 388.640 1299.435 390.640 ;
        RECT 4.400 387.240 1295.600 388.640 ;
        RECT 3.990 385.240 1299.435 387.240 ;
        RECT 3.990 383.840 1295.600 385.240 ;
        RECT 3.990 381.840 1299.435 383.840 ;
        RECT 4.400 380.440 1299.435 381.840 ;
        RECT 3.990 378.440 1299.435 380.440 ;
        RECT 4.400 377.040 1295.600 378.440 ;
        RECT 3.990 375.040 1299.435 377.040 ;
        RECT 3.990 373.640 1295.600 375.040 ;
        RECT 3.990 371.640 1299.435 373.640 ;
        RECT 4.400 370.240 1299.435 371.640 ;
        RECT 3.990 368.240 1299.435 370.240 ;
        RECT 3.990 366.840 1295.600 368.240 ;
        RECT 3.990 364.840 1299.435 366.840 ;
        RECT 4.400 363.440 1299.435 364.840 ;
        RECT 3.990 361.440 1299.435 363.440 ;
        RECT 4.400 360.040 1295.600 361.440 ;
        RECT 3.990 358.040 1299.435 360.040 ;
        RECT 3.990 356.640 1295.600 358.040 ;
        RECT 3.990 354.640 1299.435 356.640 ;
        RECT 4.400 353.240 1299.435 354.640 ;
        RECT 3.990 351.240 1299.435 353.240 ;
        RECT 4.400 349.840 1295.600 351.240 ;
        RECT 3.990 347.840 1299.435 349.840 ;
        RECT 3.990 346.440 1295.600 347.840 ;
        RECT 3.990 344.440 1299.435 346.440 ;
        RECT 4.400 343.040 1299.435 344.440 ;
        RECT 3.990 341.040 1299.435 343.040 ;
        RECT 4.400 339.640 1295.600 341.040 ;
        RECT 3.990 337.640 1299.435 339.640 ;
        RECT 3.990 336.240 1295.600 337.640 ;
        RECT 3.990 334.240 1299.435 336.240 ;
        RECT 4.400 332.840 1299.435 334.240 ;
        RECT 3.990 330.840 1299.435 332.840 ;
        RECT 4.400 329.440 1295.600 330.840 ;
        RECT 3.990 327.440 1299.435 329.440 ;
        RECT 3.990 326.040 1295.600 327.440 ;
        RECT 3.990 324.040 1299.435 326.040 ;
        RECT 4.400 322.640 1299.435 324.040 ;
        RECT 3.990 320.640 1299.435 322.640 ;
        RECT 4.400 319.240 1295.600 320.640 ;
        RECT 3.990 317.240 1299.435 319.240 ;
        RECT 3.990 315.840 1295.600 317.240 ;
        RECT 3.990 313.840 1299.435 315.840 ;
        RECT 4.400 312.440 1299.435 313.840 ;
        RECT 3.990 310.440 1299.435 312.440 ;
        RECT 4.400 309.040 1295.600 310.440 ;
        RECT 3.990 307.040 1299.435 309.040 ;
        RECT 3.990 305.640 1295.600 307.040 ;
        RECT 3.990 303.640 1299.435 305.640 ;
        RECT 4.400 302.240 1299.435 303.640 ;
        RECT 3.990 300.240 1299.435 302.240 ;
        RECT 4.400 298.840 1295.600 300.240 ;
        RECT 3.990 296.840 1299.435 298.840 ;
        RECT 3.990 295.440 1295.600 296.840 ;
        RECT 3.990 293.440 1299.435 295.440 ;
        RECT 4.400 292.040 1299.435 293.440 ;
        RECT 3.990 290.040 1299.435 292.040 ;
        RECT 4.400 288.640 1295.600 290.040 ;
        RECT 3.990 286.640 1299.435 288.640 ;
        RECT 3.990 285.240 1295.600 286.640 ;
        RECT 3.990 283.240 1299.435 285.240 ;
        RECT 4.400 281.840 1299.435 283.240 ;
        RECT 3.990 279.840 1299.435 281.840 ;
        RECT 4.400 278.440 1295.600 279.840 ;
        RECT 3.990 276.440 1299.435 278.440 ;
        RECT 3.990 275.040 1295.600 276.440 ;
        RECT 3.990 273.040 1299.435 275.040 ;
        RECT 4.400 271.640 1299.435 273.040 ;
        RECT 3.990 269.640 1299.435 271.640 ;
        RECT 4.400 268.240 1295.600 269.640 ;
        RECT 3.990 266.240 1299.435 268.240 ;
        RECT 3.990 264.840 1295.600 266.240 ;
        RECT 3.990 262.840 1299.435 264.840 ;
        RECT 4.400 261.440 1299.435 262.840 ;
        RECT 3.990 259.440 1299.435 261.440 ;
        RECT 4.400 258.040 1295.600 259.440 ;
        RECT 3.990 256.040 1299.435 258.040 ;
        RECT 3.990 254.640 1295.600 256.040 ;
        RECT 3.990 252.640 1299.435 254.640 ;
        RECT 4.400 251.240 1299.435 252.640 ;
        RECT 3.990 249.240 1299.435 251.240 ;
        RECT 3.990 247.840 1295.600 249.240 ;
        RECT 3.990 245.840 1299.435 247.840 ;
        RECT 4.400 244.440 1295.600 245.840 ;
        RECT 3.990 242.440 1299.435 244.440 ;
        RECT 4.400 241.040 1299.435 242.440 ;
        RECT 3.990 239.040 1299.435 241.040 ;
        RECT 3.990 237.640 1295.600 239.040 ;
        RECT 3.990 235.640 1299.435 237.640 ;
        RECT 4.400 234.240 1299.435 235.640 ;
        RECT 3.990 232.240 1299.435 234.240 ;
        RECT 4.400 230.840 1295.600 232.240 ;
        RECT 3.990 228.840 1299.435 230.840 ;
        RECT 3.990 227.440 1295.600 228.840 ;
        RECT 3.990 225.440 1299.435 227.440 ;
        RECT 4.400 224.040 1299.435 225.440 ;
        RECT 3.990 222.040 1299.435 224.040 ;
        RECT 4.400 220.640 1295.600 222.040 ;
        RECT 3.990 218.640 1299.435 220.640 ;
        RECT 3.990 217.240 1295.600 218.640 ;
        RECT 3.990 215.240 1299.435 217.240 ;
        RECT 4.400 213.840 1299.435 215.240 ;
        RECT 3.990 211.840 1299.435 213.840 ;
        RECT 4.400 210.440 1295.600 211.840 ;
        RECT 3.990 208.440 1299.435 210.440 ;
        RECT 3.990 207.040 1295.600 208.440 ;
        RECT 3.990 205.040 1299.435 207.040 ;
        RECT 4.400 203.640 1299.435 205.040 ;
        RECT 3.990 201.640 1299.435 203.640 ;
        RECT 4.400 200.240 1295.600 201.640 ;
        RECT 3.990 198.240 1299.435 200.240 ;
        RECT 3.990 196.840 1295.600 198.240 ;
        RECT 3.990 194.840 1299.435 196.840 ;
        RECT 4.400 193.440 1299.435 194.840 ;
        RECT 3.990 191.440 1299.435 193.440 ;
        RECT 4.400 190.040 1295.600 191.440 ;
        RECT 3.990 188.040 1299.435 190.040 ;
        RECT 3.990 186.640 1295.600 188.040 ;
        RECT 3.990 184.640 1299.435 186.640 ;
        RECT 4.400 183.240 1299.435 184.640 ;
        RECT 3.990 181.240 1299.435 183.240 ;
        RECT 4.400 179.840 1295.600 181.240 ;
        RECT 3.990 177.840 1299.435 179.840 ;
        RECT 3.990 176.440 1295.600 177.840 ;
        RECT 3.990 174.440 1299.435 176.440 ;
        RECT 4.400 173.040 1299.435 174.440 ;
        RECT 3.990 171.040 1299.435 173.040 ;
        RECT 4.400 169.640 1295.600 171.040 ;
        RECT 3.990 167.640 1299.435 169.640 ;
        RECT 3.990 166.240 1295.600 167.640 ;
        RECT 3.990 164.240 1299.435 166.240 ;
        RECT 4.400 162.840 1299.435 164.240 ;
        RECT 3.990 160.840 1299.435 162.840 ;
        RECT 4.400 159.440 1295.600 160.840 ;
        RECT 3.990 157.440 1299.435 159.440 ;
        RECT 3.990 156.040 1295.600 157.440 ;
        RECT 3.990 154.040 1299.435 156.040 ;
        RECT 4.400 152.640 1299.435 154.040 ;
        RECT 3.990 150.640 1299.435 152.640 ;
        RECT 4.400 149.240 1295.600 150.640 ;
        RECT 3.990 147.240 1299.435 149.240 ;
        RECT 3.990 145.840 1295.600 147.240 ;
        RECT 3.990 143.840 1299.435 145.840 ;
        RECT 4.400 142.440 1299.435 143.840 ;
        RECT 3.990 140.440 1299.435 142.440 ;
        RECT 4.400 139.040 1295.600 140.440 ;
        RECT 3.990 137.040 1299.435 139.040 ;
        RECT 3.990 135.640 1295.600 137.040 ;
        RECT 3.990 133.640 1299.435 135.640 ;
        RECT 4.400 132.240 1299.435 133.640 ;
        RECT 3.990 130.240 1299.435 132.240 ;
        RECT 4.400 128.840 1295.600 130.240 ;
        RECT 3.990 126.840 1299.435 128.840 ;
        RECT 3.990 125.440 1295.600 126.840 ;
        RECT 3.990 123.440 1299.435 125.440 ;
        RECT 4.400 122.040 1299.435 123.440 ;
        RECT 3.990 120.040 1299.435 122.040 ;
        RECT 3.990 118.640 1295.600 120.040 ;
        RECT 3.990 116.640 1299.435 118.640 ;
        RECT 4.400 115.240 1299.435 116.640 ;
        RECT 3.990 113.240 1299.435 115.240 ;
        RECT 4.400 111.840 1295.600 113.240 ;
        RECT 3.990 109.840 1299.435 111.840 ;
        RECT 3.990 108.440 1295.600 109.840 ;
        RECT 3.990 106.440 1299.435 108.440 ;
        RECT 4.400 105.040 1299.435 106.440 ;
        RECT 3.990 103.040 1299.435 105.040 ;
        RECT 4.400 101.640 1295.600 103.040 ;
        RECT 3.990 99.640 1299.435 101.640 ;
        RECT 3.990 98.240 1295.600 99.640 ;
        RECT 3.990 96.240 1299.435 98.240 ;
        RECT 4.400 94.840 1299.435 96.240 ;
        RECT 3.990 92.840 1299.435 94.840 ;
        RECT 4.400 91.440 1295.600 92.840 ;
        RECT 3.990 89.440 1299.435 91.440 ;
        RECT 3.990 88.040 1295.600 89.440 ;
        RECT 3.990 86.040 1299.435 88.040 ;
        RECT 4.400 84.640 1299.435 86.040 ;
        RECT 3.990 82.640 1299.435 84.640 ;
        RECT 4.400 81.240 1295.600 82.640 ;
        RECT 3.990 79.240 1299.435 81.240 ;
        RECT 3.990 77.840 1295.600 79.240 ;
        RECT 3.990 75.840 1299.435 77.840 ;
        RECT 4.400 74.440 1299.435 75.840 ;
        RECT 3.990 72.440 1299.435 74.440 ;
        RECT 4.400 71.040 1295.600 72.440 ;
        RECT 3.990 69.040 1299.435 71.040 ;
        RECT 3.990 67.640 1295.600 69.040 ;
        RECT 3.990 65.640 1299.435 67.640 ;
        RECT 4.400 64.240 1299.435 65.640 ;
        RECT 3.990 62.240 1299.435 64.240 ;
        RECT 4.400 60.840 1295.600 62.240 ;
        RECT 3.990 58.840 1299.435 60.840 ;
        RECT 3.990 57.440 1295.600 58.840 ;
        RECT 3.990 55.440 1299.435 57.440 ;
        RECT 4.400 54.040 1299.435 55.440 ;
        RECT 3.990 52.040 1299.435 54.040 ;
        RECT 4.400 50.640 1295.600 52.040 ;
        RECT 3.990 48.640 1299.435 50.640 ;
        RECT 3.990 47.240 1295.600 48.640 ;
        RECT 3.990 45.240 1299.435 47.240 ;
        RECT 4.400 43.840 1299.435 45.240 ;
        RECT 3.990 41.840 1299.435 43.840 ;
        RECT 4.400 40.440 1295.600 41.840 ;
        RECT 3.990 38.440 1299.435 40.440 ;
        RECT 3.990 37.040 1295.600 38.440 ;
        RECT 3.990 35.040 1299.435 37.040 ;
        RECT 4.400 33.640 1299.435 35.040 ;
        RECT 3.990 31.640 1299.435 33.640 ;
        RECT 4.400 30.240 1295.600 31.640 ;
        RECT 3.990 28.240 1299.435 30.240 ;
        RECT 3.990 26.840 1295.600 28.240 ;
        RECT 3.990 24.840 1299.435 26.840 ;
        RECT 4.400 23.440 1299.435 24.840 ;
        RECT 3.990 21.440 1299.435 23.440 ;
        RECT 4.400 20.040 1295.600 21.440 ;
        RECT 3.990 18.040 1299.435 20.040 ;
        RECT 3.990 16.640 1295.600 18.040 ;
        RECT 3.990 14.640 1299.435 16.640 ;
        RECT 4.400 13.240 1299.435 14.640 ;
        RECT 3.990 11.240 1299.435 13.240 ;
        RECT 4.400 9.840 1295.600 11.240 ;
        RECT 3.990 7.840 1299.435 9.840 ;
        RECT 3.990 6.440 1295.600 7.840 ;
        RECT 3.990 4.440 1299.435 6.440 ;
        RECT 4.400 3.040 1299.435 4.440 ;
        RECT 3.990 1.040 1299.435 3.040 ;
        RECT 3.990 0.175 1295.600 1.040 ;
      LAYER met4 ;
        RECT 499.855 1287.200 1279.425 1287.745 ;
        RECT 499.855 11.735 558.240 1287.200 ;
        RECT 560.640 11.735 635.040 1287.200 ;
        RECT 637.440 11.735 711.840 1287.200 ;
        RECT 714.240 11.735 788.640 1287.200 ;
        RECT 791.040 11.735 865.440 1287.200 ;
        RECT 867.840 11.735 942.240 1287.200 ;
        RECT 944.640 11.735 1019.040 1287.200 ;
        RECT 1021.440 11.735 1095.840 1287.200 ;
        RECT 1098.240 11.735 1172.640 1287.200 ;
        RECT 1175.040 11.735 1249.440 1287.200 ;
        RECT 1251.840 11.735 1279.425 1287.200 ;
  END
END encoder_1024_10
END LIBRARY

